VERSION 5.8 ;
BUSBITCHARS "[]" ;
DIVIDERCHAR "/" ;

UNITS
  DATABASE MICRONS 1000 ;
END UNITS
MANUFACTURINGGRID 0.001 ;

SITE FSFET
  CLASS CORE ;
  SIZE 0.050 BY 0.168 ;
  SYMMETRY X Y ;
END FSFET

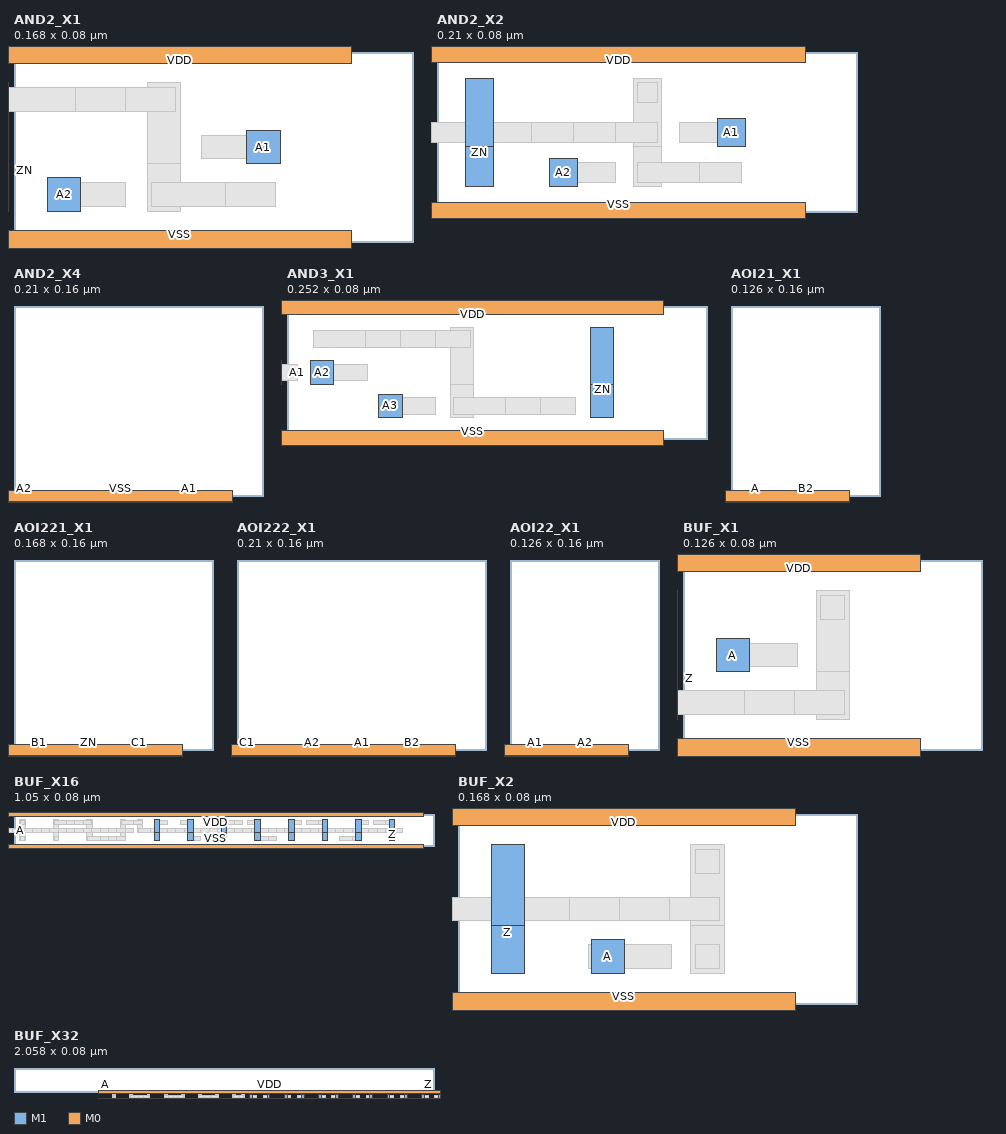
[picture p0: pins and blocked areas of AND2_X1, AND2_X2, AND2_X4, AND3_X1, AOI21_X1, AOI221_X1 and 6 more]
MACRO AND2_X1
  CLASS CORE ;
  FOREIGN AND2_X1 0 0 ;
  ORIGIN -0.0210 0.0000 ;
  SIZE 0.1680 BY 0.0800 ;
  SITE FSFET ;
  SYMMETRY X Y ;
  PIN A1
    DIRECTION INPUT ;
    USE SIGNAL ;
    PORT
      LAYER M1 ;
        RECT 0.1190 0.0330 0.1330 0.0470 ;
    END
  END A1
  PIN A2
    DIRECTION INPUT ;
    USE SIGNAL ;
    PORT
      LAYER M1 ;
        RECT 0.0350 0.0130 0.0490 0.0270 ;
    END
  END A2
  PIN ZN
    DIRECTION OUTPUT ;
    USE SIGNAL ;
    PORT
      LAYER M1 ;
        RECT -0.0070 0.0130 0.0070 0.0470 ;
        RECT -0.0070 0.0330 0.0070 0.0670 ;
    END
  END ZN
  PIN VSS
    DIRECTION INOUT ;
    USE GROUND ;
    PORT
      LAYER M0 ;
        RECT -0.0370 -0.0050 0.1630 0.0050 ;
    END
  END VSS
  PIN VDD
    DIRECTION INOUT ;
    USE POWER ;
    PORT
      LAYER M0 ;
        RECT -0.0370 0.0750 0.1630 0.0850 ;
    END
  END VDD
  OBS
    LAYER M1 ;
      RECT 0.0770 0.0130 0.0910 0.0470 ;
      RECT 0.0770 0.0330 0.0910 0.0670 ;
    LAYER M0 ;
      RECT 0.1000 0.0350 0.1310 0.0450 ;
      RECT 0.0370 0.0150 0.0680 0.0250 ;
      RECT -0.0050 0.0150 0.0050 0.0250 ;
      RECT -0.0050 0.0550 0.0050 0.0650 ;
      RECT 0.1000 0.0150 0.1310 0.0250 ;
      RECT 0.0790 0.0150 0.1100 0.0250 ;
      RECT 0.0580 0.0550 0.0890 0.0650 ;
      RECT 0.0370 0.0550 0.0680 0.0650 ;
      RECT 0.0160 0.0550 0.0470 0.0650 ;
  END
END AND2_X1

MACRO AND2_X2
  CLASS CORE ;
  FOREIGN AND2_X2 0 0 ;
  ORIGIN -0.0210 0.0000 ;
  SIZE 0.2100 BY 0.0800 ;
  SITE FSFET ;
  SYMMETRY X Y ;
  PIN A1
    DIRECTION INPUT ;
    USE SIGNAL ;
    PORT
      LAYER M1 ;
        RECT 0.1610 0.0330 0.1750 0.0470 ;
    END
  END A1
  PIN A2
    DIRECTION INPUT ;
    USE SIGNAL ;
    PORT
      LAYER M1 ;
        RECT 0.0770 0.0130 0.0910 0.0270 ;
    END
  END A2
  PIN ZN
    DIRECTION OUTPUT ;
    USE SIGNAL ;
    PORT
      LAYER M1 ;
        RECT 0.0350 0.0130 0.0490 0.0470 ;
        RECT 0.0350 0.0330 0.0490 0.0670 ;
    END
  END ZN
  PIN VDD
    DIRECTION INOUT ;
    USE POWER ;
    PORT
      LAYER M0 ;
        RECT -0.0370 0.0750 0.2050 0.0850 ;
    END
  END VDD
  PIN VSS
    DIRECTION INOUT ;
    USE GROUND ;
    PORT
      LAYER M0 ;
        RECT -0.0370 -0.0050 0.2050 0.0050 ;
    END
  END VSS
  OBS
    LAYER M1 ;
      RECT 0.1190 0.0130 0.1330 0.0470 ;
      RECT 0.1190 0.0330 0.1330 0.0670 ;
    LAYER M0 ;
      RECT 0.1420 0.0350 0.1730 0.0450 ;
      RECT 0.0790 0.0150 0.1100 0.0250 ;
      RECT 0.1210 0.0550 0.1310 0.0650 ;
      RECT 0.0370 0.0150 0.0470 0.0250 ;
      RECT 0.0370 0.0550 0.0470 0.0650 ;
      RECT 0.1420 0.0150 0.1730 0.0250 ;
      RECT 0.1210 0.0150 0.1520 0.0250 ;
      RECT 0.1000 0.0350 0.1310 0.0450 ;
      RECT 0.0790 0.0350 0.1100 0.0450 ;
      RECT 0.0580 0.0350 0.0890 0.0450 ;
      RECT 0.0370 0.0350 0.0680 0.0450 ;
      RECT 0.0160 0.0350 0.0470 0.0450 ;
  END
END AND2_X2

MACRO AND2_X4
  CLASS CORE ;
  FOREIGN AND2_X4 0 0 ;
  ORIGIN -0.0210 -0.0800 ;
  SIZE 0.2100 BY 0.1600 ;
  SITE FSFET ;
  SYMMETRY X Y ;
  PIN ZN
    DIRECTION OUTPUT ;
    USE SIGNAL ;
    PORT
      LAYER M1 ;
        RECT -0.0070 -0.0670 0.0070 -0.0330 ;
        RECT -0.0070 -0.0470 0.0070 -0.0130 ;
    END
  END ZN
  PIN A1
    DIRECTION INPUT ;
    USE SIGNAL ;
    PORT
      LAYER M1 ;
        RECT 0.1610 0.0130 0.1750 0.0270 ;
    END
  END A1
  PIN A2
    DIRECTION INPUT ;
    USE SIGNAL ;
    PORT
      LAYER M1 ;
        RECT -0.0070 0.0330 0.0070 0.0470 ;
    END
  END A2
  PIN VSS
    DIRECTION INOUT ;
    USE GROUND ;
    PORT
      LAYER M0 ;
        RECT -0.0370 -0.0050 0.2050 0.0050 ;
    END
  END VSS
  PIN VDD
    DIRECTION INOUT ;
    USE POWER ;
    PORT
      LAYER M0 ;
        RECT -0.0370 -0.0850 0.2050 -0.0750 ;
    END
  END VDD
  PIN VDD
    DIRECTION INOUT ;
    USE POWER ;
    PORT
      LAYER M0 ;
        RECT -0.0370 0.0750 0.2050 0.0850 ;
    END
  END VDD
  OBS
    LAYER M1 ;
      RECT 0.1190 -0.0470 0.1330 -0.0130 ;
      RECT 0.1190 -0.0270 0.1330 0.0070 ;
      RECT 0.1190 -0.0070 0.1330 0.0270 ;
      RECT 0.1190 0.0130 0.1330 0.0470 ;
      RECT 0.1190 0.0330 0.1330 0.0670 ;
      RECT 0.0770 -0.0470 0.0910 -0.0130 ;
      RECT 0.0770 -0.0270 0.0910 0.0070 ;
      RECT 0.0770 -0.0070 0.0910 0.0270 ;
      RECT 0.0350 -0.0470 0.0490 -0.0130 ;
      RECT 0.0350 -0.0270 0.0490 0.0070 ;
      RECT 0.0350 -0.0070 0.0490 0.0270 ;
      RECT 0.0350 0.0130 0.0490 0.0470 ;
      RECT 0.0350 0.0330 0.0490 0.0670 ;
    LAYER M0 ;
      RECT 0.1000 0.0150 0.1730 0.0250 ;
      RECT 0.0790 0.0150 0.0890 0.0250 ;
      RECT 0.1210 0.0550 0.1310 0.0650 ;
      RECT 0.0370 0.0550 0.0470 0.0650 ;
      RECT 0.0790 0.0550 0.1100 0.0650 ;
      RECT 0.0580 0.0550 0.0890 0.0650 ;
      RECT 0.1210 0.0350 0.1520 0.0450 ;
      RECT 0.1000 0.0350 0.1310 0.0450 ;
      RECT 0.0790 0.0350 0.1100 0.0450 ;
      RECT 0.0580 0.0350 0.0890 0.0450 ;
      RECT 0.0370 0.0350 0.0680 0.0450 ;
      RECT -0.0050 0.0350 0.0470 0.0450 ;
      RECT 0.1000 -0.0650 0.1310 -0.0550 ;
      RECT 0.0790 -0.0650 0.1100 -0.0550 ;
      RECT 0.0580 -0.0650 0.0890 -0.0550 ;
      RECT 0.0370 -0.0650 0.0680 -0.0550 ;
      RECT 0.0160 -0.0650 0.0470 -0.0550 ;
      RECT -0.0050 -0.0650 0.0260 -0.0550 ;
      RECT 0.1000 -0.0250 0.1310 -0.0150 ;
      RECT 0.0790 -0.0250 0.1100 -0.0150 ;
      RECT 0.0580 -0.0250 0.0890 -0.0150 ;
      RECT 0.0370 -0.0250 0.0680 -0.0150 ;
      RECT 0.0160 -0.0250 0.0470 -0.0150 ;
      RECT -0.0050 -0.0250 0.0260 -0.0150 ;
      RECT 0.1210 -0.0450 0.1520 -0.0350 ;
      RECT 0.1000 -0.0450 0.1310 -0.0350 ;
      RECT 0.0790 -0.0450 0.1100 -0.0350 ;
      RECT 0.0580 -0.0450 0.0890 -0.0350 ;
      RECT 0.0370 -0.0450 0.0680 -0.0350 ;
      RECT 0.0160 -0.0450 0.0470 -0.0350 ;
  END
END AND2_X4

MACRO AND3_X1
  CLASS CORE ;
  FOREIGN AND3_X1 0 0 ;
  ORIGIN -0.0210 0.0000 ;
  SIZE 0.2520 BY 0.0800 ;
  SITE FSFET ;
  SYMMETRY X Y ;
  PIN A3
    DIRECTION INPUT ;
    USE SIGNAL ;
    PORT
      LAYER M1 ;
        RECT 0.0760 0.0130 0.0900 0.0270 ;
    END
  END A3
  PIN A2
    DIRECTION INPUT ;
    USE SIGNAL ;
    PORT
      LAYER M1 ;
        RECT 0.0350 0.0330 0.0490 0.0470 ;
    END
  END A2
  PIN A1
    DIRECTION INPUT ;
    USE SIGNAL ;
    PORT
      LAYER M1 ;
        RECT -0.0070 0.0330 0.0070 0.0470 ;
    END
  END A1
  PIN ZN
    DIRECTION OUTPUT ;
    USE SIGNAL ;
    PORT
      LAYER M1 ;
        RECT 0.2030 0.0130 0.2170 0.0470 ;
        RECT 0.2030 0.0330 0.2170 0.0670 ;
    END
  END ZN
  PIN VSS
    DIRECTION INOUT ;
    USE GROUND ;
    PORT
      LAYER M0 ;
        RECT -0.0370 -0.0050 0.2470 0.0050 ;
    END
  END VSS
  PIN VDD
    DIRECTION INOUT ;
    USE POWER ;
    PORT
      LAYER M0 ;
        RECT -0.0370 0.0750 0.2470 0.0850 ;
    END
  END VDD
  OBS
    LAYER M1 ;
      RECT 0.1190 0.0130 0.1330 0.0470 ;
      RECT 0.1190 0.0330 0.1330 0.0670 ;
    LAYER M0 ;
      RECT 0.0780 0.0150 0.1100 0.0250 ;
      RECT 0.0370 0.0350 0.0690 0.0450 ;
      RECT -0.0050 0.0350 0.0270 0.0450 ;
      RECT 0.2050 0.0150 0.2150 0.0250 ;
      RECT 0.2050 0.0550 0.2150 0.0650 ;
      RECT 0.1630 0.0150 0.1940 0.0250 ;
      RECT 0.1420 0.0150 0.1730 0.0250 ;
      RECT 0.1210 0.0150 0.1520 0.0250 ;
      RECT 0.1000 0.0550 0.1310 0.0650 ;
      RECT 0.0790 0.0550 0.1100 0.0650 ;
      RECT 0.0580 0.0550 0.0890 0.0650 ;
      RECT 0.0370 0.0550 0.0680 0.0650 ;
  END
END AND3_X1

MACRO AOI21_X1
  CLASS CORE ;
  FOREIGN AOI21_X1 0 0 ;
  ORIGIN -0.0210 -0.0800 ;
  SIZE 0.1260 BY 0.1600 ;
  SITE FSFET ;
  SYMMETRY X Y ;
  PIN A
    DIRECTION INPUT ;
    USE SIGNAL ;
    PORT
      LAYER M1 ;
        RECT 0.0350 -0.0470 0.0490 -0.0330 ;
    END
  END A
  PIN ZN
    DIRECTION OUTPUT ;
    USE SIGNAL ;
    PORT
      LAYER M1 ;
        RECT 0.0770 0.0130 0.0910 0.0470 ;
    END
  END ZN
  PIN B2
    DIRECTION INPUT ;
    USE SIGNAL ;
    PORT
      LAYER M1 ;
        RECT 0.0770 0.0530 0.0910 0.0670 ;
    END
  END B2
  PIN B1
    DIRECTION INPUT ;
    USE SIGNAL ;
    PORT
      LAYER M1 ;
        RECT 0.0350 0.0530 0.0490 0.0670 ;
    END
  END B1
  PIN VDD
    DIRECTION INOUT ;
    USE POWER ;
    PORT
      LAYER M0 ;
        RECT -0.0370 -0.0050 0.1210 0.0050 ;
    END
  END VDD
  PIN VSS
    DIRECTION INOUT ;
    USE GROUND ;
    PORT
      LAYER M0 ;
        RECT -0.0370 -0.0850 0.1210 -0.0750 ;
    END
  END VSS
  PIN VSS
    DIRECTION INOUT ;
    USE GROUND ;
    PORT
      LAYER M0 ;
        RECT -0.0370 0.0750 0.1210 0.0850 ;
    END
  END VSS
  OBS
    LAYER M1 ;
      RECT -0.0070 -0.0670 0.0070 -0.0330 ;
      RECT -0.0070 -0.0470 0.0070 -0.0130 ;
      RECT -0.0070 -0.0270 0.0070 0.0070 ;
      RECT -0.0070 -0.0070 0.0070 0.0270 ;
      RECT -0.0070 0.0130 0.0070 0.0470 ;
      RECT -0.0070 0.0330 0.0070 0.0670 ;
      RECT 0.0350 -0.0270 0.0490 0.0070 ;
      RECT 0.0350 -0.0070 0.0490 0.0270 ;
    LAYER M0 ;
      RECT 0.0160 -0.0450 0.0470 -0.0350 ;
      RECT 0.0580 0.0550 0.0890 0.0650 ;
      RECT 0.0160 0.0550 0.0470 0.0650 ;
      RECT -0.0050 -0.0650 0.0050 -0.0550 ;
      RECT 0.0790 0.0150 0.0890 0.0250 ;
      RECT -0.0050 0.0150 0.0050 0.0250 ;
      RECT -0.0050 0.0550 0.0050 0.0650 ;
      RECT 0.0370 -0.0250 0.0470 -0.0150 ;
      RECT 0.0370 0.0150 0.0470 0.0250 ;
      RECT 0.0580 0.0350 0.0890 0.0450 ;
      RECT 0.0370 0.0350 0.0680 0.0450 ;
      RECT 0.0160 0.0350 0.0470 0.0450 ;
      RECT -0.0050 0.0350 0.0260 0.0450 ;
  END
END AOI21_X1

MACRO AOI221_X1
  CLASS CORE ;
  FOREIGN AOI221_X1 0 0 ;
  ORIGIN -0.0210 -0.0800 ;
  SIZE 0.1680 BY 0.1600 ;
  SITE FSFET ;
  SYMMETRY X Y ;
  PIN ZN
    DIRECTION OUTPUT ;
    USE SIGNAL ;
    PORT
      LAYER M1 ;
        RECT 0.0770 0.0330 0.0910 0.0670 ;
    END
  END ZN
  PIN C2
    DIRECTION INPUT ;
    USE SIGNAL ;
    PORT
      LAYER M1 ;
        RECT 0.0350 -0.0670 0.0490 -0.0530 ;
    END
  END C2
  PIN B2
    DIRECTION INPUT ;
    USE SIGNAL ;
    PORT
      LAYER M1 ;
        RECT -0.0070 0.0530 0.0070 0.0670 ;
    END
  END B2
  PIN B1
    DIRECTION INPUT ;
    USE SIGNAL ;
    PORT
      LAYER M1 ;
        RECT 0.0350 0.0530 0.0490 0.0670 ;
    END
  END B1
  PIN A
    DIRECTION INPUT ;
    USE SIGNAL ;
    PORT
      LAYER M1 ;
        RECT 0.1190 0.0530 0.1330 0.0670 ;
    END
  END A
  PIN C1
    DIRECTION INPUT ;
    USE SIGNAL ;
    PORT
      LAYER M1 ;
        RECT 0.1190 -0.0470 0.1330 -0.0330 ;
    END
  END C1
  PIN VDD
    DIRECTION INOUT ;
    USE POWER ;
    PORT
      LAYER M0 ;
        RECT -0.0370 -0.0050 0.1630 0.0050 ;
    END
  END VDD
  PIN VSS
    DIRECTION INOUT ;
    USE GROUND ;
    PORT
      LAYER M0 ;
        RECT -0.0370 -0.0850 0.1630 -0.0750 ;
    END
  END VSS
  PIN VSS
    DIRECTION INOUT ;
    USE GROUND ;
    PORT
      LAYER M0 ;
        RECT -0.0370 0.0750 0.1630 0.0850 ;
    END
  END VSS
  OBS
    LAYER M1 ;
      RECT 0.0770 -0.0670 0.0910 -0.0330 ;
      RECT 0.0770 -0.0470 0.0910 -0.0130 ;
      RECT 0.0770 -0.0270 0.0910 0.0070 ;
      RECT 0.0770 -0.0070 0.0910 0.0270 ;
      RECT 0.0770 0.0130 0.0910 0.0470 ;
      RECT 0.1190 0.0130 0.1330 0.0470 ;
      RECT 0.1190 -0.0270 0.1330 0.0070 ;
      RECT 0.1190 -0.0070 0.1330 0.0270 ;
      RECT 0.0350 -0.0270 0.0490 0.0470 ;
    LAYER M0 ;
      RECT 0.0370 -0.0650 0.0680 -0.0550 ;
      RECT -0.0050 0.0550 0.0260 0.0650 ;
      RECT 0.0370 0.0550 0.0680 0.0650 ;
      RECT 0.1000 0.0550 0.1310 0.0650 ;
      RECT 0.0790 -0.0250 0.0890 -0.0150 ;
      RECT 0.0790 0.0550 0.0890 0.0650 ;
      RECT 0.1210 -0.0250 0.1310 -0.0150 ;
      RECT 0.0370 -0.0250 0.0470 -0.0150 ;
      RECT 0.1210 0.0150 0.1310 0.0250 ;
      RECT 0.1000 -0.0650 0.1310 -0.0550 ;
      RECT 0.0790 -0.0650 0.1100 -0.0550 ;
      RECT 0.1000 0.0350 0.1310 0.0450 ;
      RECT 0.0790 0.0350 0.1100 0.0450 ;
      RECT 0.0580 0.0350 0.0890 0.0450 ;
      RECT 0.0370 0.0350 0.0680 0.0450 ;
      RECT 0.0580 0.0150 0.0890 0.0250 ;
      RECT 0.0370 0.0150 0.0680 0.0250 ;
      RECT 0.0160 0.0150 0.0470 0.0250 ;
      RECT -0.0050 0.0150 0.0260 0.0250 ;
      RECT 0.1000 -0.0450 0.1310 -0.0350 ;
  END
END AOI221_X1

MACRO AOI222_X1
  CLASS CORE ;
  FOREIGN AOI222_X1 0 0 ;
  ORIGIN -0.0210 -0.0800 ;
  SIZE 0.2100 BY 0.1600 ;
  SITE FSFET ;
  SYMMETRY X Y ;
  PIN A2
    DIRECTION INPUT ;
    USE SIGNAL ;
    PORT
      LAYER M1 ;
        RECT 0.0770 -0.0670 0.0910 -0.0530 ;
    END
  END A2
  PIN ZN
    DIRECTION OUTPUT ;
    USE SIGNAL ;
    PORT
      LAYER M1 ;
        RECT 0.0350 0.0330 0.0490 0.0670 ;
    END
  END ZN
  PIN A1
    DIRECTION INPUT ;
    USE SIGNAL ;
    PORT
      LAYER M1 ;
        RECT 0.1190 -0.0670 0.1330 -0.0530 ;
    END
  END A1
  PIN B2
    DIRECTION INPUT ;
    USE SIGNAL ;
    PORT
      LAYER M1 ;
        RECT 0.1610 0.0530 0.1750 0.0670 ;
    END
  END B2
  PIN B1
    DIRECTION INPUT ;
    USE SIGNAL ;
    PORT
      LAYER M1 ;
        RECT 0.1190 0.0530 0.1330 0.0670 ;
    END
  END B1
  PIN C1
    DIRECTION INPUT ;
    USE SIGNAL ;
    PORT
      LAYER M1 ;
        RECT -0.0070 0.0330 0.0070 0.0470 ;
    END
  END C1
  PIN C2
    DIRECTION INPUT ;
    USE SIGNAL ;
    PORT
      LAYER M1 ;
        RECT -0.0070 0.0530 0.0070 0.0670 ;
    END
  END C2
  PIN VDD
    DIRECTION INOUT ;
    USE POWER ;
    PORT
      LAYER M0 ;
        RECT -0.0370 -0.0050 0.2050 0.0050 ;
    END
  END VDD
  PIN VSS
    DIRECTION INOUT ;
    USE GROUND ;
    PORT
      LAYER M0 ;
        RECT -0.0370 0.0750 0.2050 0.0850 ;
    END
  END VSS
  PIN VSS
    DIRECTION INOUT ;
    USE GROUND ;
    PORT
      LAYER M0 ;
        RECT -0.0370 -0.0850 0.2050 -0.0750 ;
    END
  END VSS
  OBS
    LAYER M1 ;
      RECT 0.1610 -0.0670 0.1750 -0.0330 ;
      RECT 0.1610 -0.0470 0.1750 -0.0130 ;
      RECT 0.0770 -0.0470 0.0910 -0.0130 ;
      RECT 0.0350 -0.0270 0.0490 0.0070 ;
      RECT 0.0350 -0.0070 0.0490 0.0270 ;
      RECT 0.0350 0.0130 0.0490 0.0470 ;
      RECT 0.1190 -0.0270 0.1330 0.0070 ;
      RECT 0.1190 -0.0070 0.1330 0.0270 ;
      RECT 0.1610 0.0130 0.1750 0.0470 ;
      RECT 0.0770 0.0130 0.0910 0.0470 ;
    LAYER M0 ;
      RECT 0.0790 -0.0650 0.1100 -0.0550 ;
      RECT 0.1210 -0.0650 0.1520 -0.0550 ;
      RECT 0.1420 0.0550 0.1730 0.0650 ;
      RECT 0.1000 0.0550 0.1310 0.0650 ;
      RECT -0.0050 0.0350 0.0680 0.0450 ;
      RECT 0.1630 -0.0650 0.1730 -0.0550 ;
      RECT 0.1630 -0.0250 0.1730 -0.0150 ;
      RECT 0.1210 -0.0250 0.1310 -0.0150 ;
      RECT 0.1210 0.0150 0.1310 0.0250 ;
      RECT 0.1630 0.0150 0.1730 0.0250 ;
      RECT 0.1420 -0.0450 0.1730 -0.0350 ;
      RECT 0.1210 -0.0450 0.1520 -0.0350 ;
      RECT 0.1000 -0.0450 0.1310 -0.0350 ;
      RECT 0.0790 -0.0450 0.1100 -0.0350 ;
      RECT 0.0580 -0.0250 0.0890 -0.0150 ;
      RECT 0.0370 -0.0250 0.0680 -0.0150 ;
      RECT 0.0580 0.0550 0.0890 0.0650 ;
      RECT 0.0370 0.0550 0.0680 0.0650 ;
      RECT 0.0580 0.0150 0.0890 0.0250 ;
      RECT 0.0370 0.0150 0.0680 0.0250 ;
      RECT 0.0160 0.0150 0.0470 0.0250 ;
      RECT -0.0050 0.0150 0.0260 0.0250 ;
      RECT 0.1420 0.0350 0.1730 0.0450 ;
      RECT 0.1210 0.0350 0.1520 0.0450 ;
      RECT 0.1000 0.0350 0.1310 0.0450 ;
      RECT 0.0790 0.0350 0.1100 0.0450 ;
      RECT -0.0050 0.0550 0.0260 0.0650 ;
  END
END AOI222_X1

MACRO AOI22_X1
  CLASS CORE ;
  FOREIGN AOI22_X1 0 0 ;
  ORIGIN -0.0210 -0.0800 ;
  SIZE 0.1260 BY 0.1600 ;
  SITE FSFET ;
  SYMMETRY X Y ;
  PIN A2
    DIRECTION INPUT ;
    USE SIGNAL ;
    PORT
      LAYER M1 ;
        RECT 0.0770 -0.0670 0.0910 -0.0530 ;
    END
  END A2
  PIN A1
    DIRECTION INPUT ;
    USE SIGNAL ;
    PORT
      LAYER M1 ;
        RECT 0.0350 -0.0670 0.0490 -0.0530 ;
    END
  END A1
  PIN ZN
    DIRECTION OUTPUT ;
    USE SIGNAL ;
    PORT
      LAYER M1 ;
        RECT 0.0770 0.0330 0.0910 0.0670 ;
    END
  END ZN
  PIN B1
    DIRECTION INPUT ;
    USE SIGNAL ;
    PORT
      LAYER M1 ;
        RECT 0.0350 0.0530 0.0490 0.0670 ;
    END
  END B1
  PIN B2
    DIRECTION INPUT ;
    USE SIGNAL ;
    PORT
      LAYER M1 ;
        RECT -0.0070 0.0530 0.0070 0.0670 ;
    END
  END B2
  PIN VDD
    DIRECTION INOUT ;
    USE POWER ;
    PORT
      LAYER M0 ;
        RECT -0.0370 -0.0050 0.1210 0.0050 ;
    END
  END VDD
  PIN VSS
    DIRECTION INOUT ;
    USE GROUND ;
    PORT
      LAYER M0 ;
        RECT -0.0370 -0.0850 0.1210 -0.0750 ;
    END
  END VSS
  PIN VSS
    DIRECTION INOUT ;
    USE GROUND ;
    PORT
      LAYER M0 ;
        RECT -0.0370 0.0750 0.1210 0.0850 ;
    END
  END VSS
  OBS
    LAYER M1 ;
      RECT 0.0770 -0.0470 0.0910 -0.0130 ;
      RECT 0.0770 -0.0270 0.0910 0.0070 ;
      RECT 0.0770 -0.0070 0.0910 0.0270 ;
      RECT 0.0770 0.0130 0.0910 0.0470 ;
      RECT -0.0070 -0.0670 0.0070 -0.0330 ;
      RECT -0.0070 -0.0470 0.0070 -0.0130 ;
      RECT 0.0350 -0.0270 0.0490 0.0070 ;
      RECT 0.0350 -0.0070 0.0490 0.0270 ;
    LAYER M0 ;
      RECT 0.0580 -0.0650 0.0890 -0.0550 ;
      RECT 0.0160 -0.0650 0.0470 -0.0550 ;
      RECT 0.0370 0.0550 0.0680 0.0650 ;
      RECT -0.0050 0.0550 0.0260 0.0650 ;
      RECT -0.0050 -0.0650 0.0050 -0.0550 ;
      RECT 0.0790 -0.0250 0.0890 -0.0150 ;
      RECT -0.0050 -0.0250 0.0050 -0.0150 ;
      RECT 0.0790 0.0550 0.0890 0.0650 ;
      RECT 0.0370 -0.0250 0.0470 -0.0150 ;
      RECT 0.0370 0.0150 0.0470 0.0250 ;
      RECT 0.0580 -0.0450 0.0890 -0.0350 ;
      RECT 0.0370 -0.0450 0.0680 -0.0350 ;
      RECT 0.0160 -0.0450 0.0470 -0.0350 ;
      RECT -0.0050 -0.0450 0.0260 -0.0350 ;
  END
END AOI22_X1

MACRO BUF_X1
  CLASS CORE ;
  FOREIGN BUF_X1 0 0 ;
  ORIGIN -0.0210 0.0000 ;
  SIZE 0.1260 BY 0.0800 ;
  SITE FSFET ;
  SYMMETRY X Y ;
  PIN A
    DIRECTION INPUT ;
    USE SIGNAL ;
    PORT
      LAYER M1 ;
        RECT 0.0350 0.0330 0.0490 0.0470 ;
    END
  END A
  PIN Z
    DIRECTION OUTPUT ;
    USE SIGNAL ;
    PORT
      LAYER M1 ;
        RECT -0.0070 0.0130 0.0070 0.0470 ;
        RECT -0.0070 0.0330 0.0070 0.0670 ;
    END
  END Z
  PIN VSS
    DIRECTION INOUT ;
    USE GROUND ;
    PORT
      LAYER M0 ;
        RECT -0.0370 -0.0050 0.1210 0.0050 ;
    END
  END VSS
  PIN VDD
    DIRECTION INOUT ;
    USE POWER ;
    PORT
      LAYER M0 ;
        RECT -0.0370 0.0750 0.1210 0.0850 ;
    END
  END VDD
  OBS
    LAYER M1 ;
      RECT 0.0770 0.0130 0.0910 0.0470 ;
      RECT 0.0770 0.0330 0.0910 0.0670 ;
    LAYER M0 ;
      RECT 0.0370 0.0350 0.0690 0.0450 ;
      RECT 0.0790 0.0550 0.0890 0.0650 ;
      RECT -0.0050 0.0150 0.0050 0.0250 ;
      RECT -0.0050 0.0550 0.0050 0.0650 ;
      RECT 0.0580 0.0150 0.0890 0.0250 ;
      RECT 0.0370 0.0150 0.0680 0.0250 ;
      RECT 0.0160 0.0150 0.0470 0.0250 ;
  END
END BUF_X1

MACRO BUF_X16
  CLASS CORE ;
  FOREIGN BUF_X16 0 0 ;
  ORIGIN -0.0210 0.0000 ;
  SIZE 1.0500 BY 0.0800 ;
  SITE FSFET ;
  SYMMETRY X Y ;
  PIN Z
    DIRECTION OUTPUT ;
    USE SIGNAL ;
    PORT
      LAYER M1 ;
        RECT 0.9590 0.0130 0.9730 0.0470 ;
        RECT 0.9590 0.0330 0.9730 0.0670 ;
        RECT 0.8750 0.0130 0.8890 0.0470 ;
        RECT 0.8750 0.0330 0.8890 0.0670 ;
        RECT 0.7910 0.0130 0.8050 0.0470 ;
        RECT 0.7910 0.0330 0.8050 0.0670 ;
        RECT 0.7070 0.0130 0.7210 0.0470 ;
        RECT 0.7070 0.0330 0.7210 0.0670 ;
        RECT 0.6230 0.0130 0.6370 0.0470 ;
        RECT 0.6230 0.0330 0.6370 0.0670 ;
        RECT 0.5390 0.0130 0.5530 0.0470 ;
        RECT 0.5390 0.0330 0.5530 0.0670 ;
        RECT 0.4550 0.0130 0.4690 0.0470 ;
        RECT 0.4550 0.0330 0.4690 0.0670 ;
        RECT 0.3710 0.0130 0.3850 0.0470 ;
        RECT 0.3710 0.0330 0.3850 0.0670 ;
    END
  END Z
  PIN A
    DIRECTION INPUT ;
    USE SIGNAL ;
    PORT
      LAYER M1 ;
        RECT -0.0060 0.0330 0.0080 0.0470 ;
    END
  END A
  PIN VSS
    DIRECTION INOUT ;
    USE GROUND ;
    PORT
      LAYER M0 ;
        RECT -0.0370 -0.0050 1.0450 0.0050 ;
    END
  END VSS
  PIN VDD
    DIRECTION INOUT ;
    USE POWER ;
    PORT
      LAYER M0 ;
        RECT -0.0370 0.0750 1.0450 0.0850 ;
    END
  END VDD
  OBS
    LAYER M1 ;
      RECT 0.3290 0.0330 0.3430 0.0670 ;
      RECT 0.2870 0.0130 0.3010 0.0470 ;
      RECT 0.2870 0.0330 0.3010 0.0670 ;
      RECT 0.2030 0.0130 0.2170 0.0470 ;
      RECT 0.2030 0.0330 0.2170 0.0670 ;
      RECT 0.1190 0.0130 0.1330 0.0470 ;
      RECT 0.1190 0.0330 0.1330 0.0670 ;
      RECT 0.0350 0.0130 0.0490 0.0470 ;
      RECT 0.0350 0.0330 0.0490 0.0670 ;
    LAYER M0 ;
      RECT -0.0080 0.0350 0.0280 0.0450 ;
      RECT 0.9610 0.0150 0.9710 0.0250 ;
      RECT 0.3730 0.0150 0.3830 0.0250 ;
      RECT 0.1210 0.0150 0.1310 0.0250 ;
      RECT 0.0370 0.0150 0.0470 0.0250 ;
      RECT 0.0370 0.0550 0.0470 0.0650 ;
      RECT 0.2890 0.0350 0.3200 0.0450 ;
      RECT 0.2680 0.0350 0.2990 0.0450 ;
      RECT 0.2470 0.0350 0.2780 0.0450 ;
      RECT 0.2260 0.0350 0.2570 0.0450 ;
      RECT 0.2050 0.0350 0.2360 0.0450 ;
      RECT 0.1840 0.0350 0.2150 0.0450 ;
      RECT 0.1630 0.0350 0.1940 0.0450 ;
      RECT 0.1420 0.0350 0.1730 0.0450 ;
      RECT 0.1210 0.0350 0.1520 0.0450 ;
      RECT 0.1000 0.0350 0.1310 0.0450 ;
      RECT 0.0790 0.0350 0.1100 0.0450 ;
      RECT 0.0580 0.0350 0.0890 0.0450 ;
      RECT 0.0370 0.0350 0.0680 0.0450 ;
      RECT 0.0160 0.0350 0.0470 0.0450 ;
      RECT 0.8560 0.0150 0.8870 0.0250 ;
      RECT 0.8350 0.0150 0.8660 0.0250 ;
      RECT 0.6460 0.0150 0.6770 0.0250 ;
      RECT 0.6250 0.0150 0.6560 0.0250 ;
      RECT 0.5200 0.0150 0.5510 0.0250 ;
      RECT 0.4990 0.0150 0.5300 0.0250 ;
      RECT 0.4570 0.0150 0.4880 0.0250 ;
      RECT 0.9400 0.0550 0.9710 0.0650 ;
      RECT 0.9190 0.0550 0.9500 0.0650 ;
      RECT 0.8770 0.0550 0.9080 0.0650 ;
      RECT 0.7720 0.0550 0.8030 0.0650 ;
      RECT 0.7510 0.0550 0.7820 0.0650 ;
      RECT 0.7090 0.0550 0.7400 0.0650 ;
      RECT 0.6040 0.0550 0.6350 0.0650 ;
      RECT 0.5620 0.0550 0.5930 0.0650 ;
      RECT 0.5410 0.0550 0.5720 0.0650 ;
      RECT 0.4360 0.0550 0.4670 0.0650 ;
      RECT 0.3730 0.0550 0.4040 0.0650 ;
      RECT 0.2680 0.0150 0.2990 0.0250 ;
      RECT 0.2470 0.0150 0.2780 0.0250 ;
      RECT 0.2260 0.0150 0.2570 0.0250 ;
      RECT 0.2050 0.0150 0.2360 0.0250 ;
      RECT 0.9610 0.0350 0.9920 0.0450 ;
      RECT 0.9400 0.0350 0.9710 0.0450 ;
      RECT 0.9190 0.0350 0.9500 0.0450 ;
      RECT 0.8980 0.0350 0.9290 0.0450 ;
      RECT 0.8770 0.0350 0.9080 0.0450 ;
      RECT 0.8560 0.0350 0.8870 0.0450 ;
      RECT 0.8350 0.0350 0.8660 0.0450 ;
      RECT 0.8140 0.0350 0.8450 0.0450 ;
      RECT 0.7930 0.0350 0.8240 0.0450 ;
      RECT 0.7720 0.0350 0.8030 0.0450 ;
      RECT 0.7510 0.0350 0.7820 0.0450 ;
      RECT 0.7300 0.0350 0.7610 0.0450 ;
      RECT 0.7090 0.0350 0.7400 0.0450 ;
      RECT 0.6880 0.0350 0.7190 0.0450 ;
      RECT 0.6670 0.0350 0.6980 0.0450 ;
      RECT 0.6460 0.0350 0.6770 0.0450 ;
      RECT 0.6250 0.0350 0.6560 0.0450 ;
      RECT 0.6040 0.0350 0.6350 0.0450 ;
      RECT 0.5830 0.0350 0.6140 0.0450 ;
      RECT 0.5620 0.0350 0.5930 0.0450 ;
      RECT 0.5410 0.0350 0.5720 0.0450 ;
      RECT 0.5200 0.0350 0.5510 0.0450 ;
      RECT 0.4990 0.0350 0.5300 0.0450 ;
      RECT 0.4780 0.0350 0.5090 0.0450 ;
      RECT 0.4570 0.0350 0.4880 0.0450 ;
      RECT 0.4360 0.0350 0.4670 0.0450 ;
      RECT 0.4150 0.0350 0.4460 0.0450 ;
      RECT 0.3940 0.0350 0.4250 0.0450 ;
      RECT 0.3730 0.0350 0.4040 0.0450 ;
      RECT 0.3520 0.0350 0.3830 0.0450 ;
      RECT 0.3310 0.0350 0.3620 0.0450 ;
      RECT 0.3100 0.0550 0.3410 0.0650 ;
      RECT 0.2890 0.0550 0.3200 0.0650 ;
      RECT 0.1840 0.0550 0.2150 0.0650 ;
      RECT 0.1630 0.0550 0.1940 0.0650 ;
      RECT 0.1420 0.0550 0.1730 0.0650 ;
      RECT 0.1210 0.0550 0.1520 0.0650 ;
  END
END BUF_X16

MACRO BUF_X2
  CLASS CORE ;
  FOREIGN BUF_X2 0 0 ;
  ORIGIN -0.0210 0.0000 ;
  SIZE 0.1680 BY 0.0800 ;
  SITE FSFET ;
  SYMMETRY X Y ;
  PIN A
    DIRECTION INPUT ;
    USE SIGNAL ;
    PORT
      LAYER M1 ;
        RECT 0.0770 0.0130 0.0910 0.0270 ;
    END
  END A
  PIN Z
    DIRECTION OUTPUT ;
    USE SIGNAL ;
    PORT
      LAYER M1 ;
        RECT 0.0350 0.0130 0.0490 0.0470 ;
        RECT 0.0350 0.0330 0.0490 0.0670 ;
    END
  END Z
  PIN VSS
    DIRECTION INOUT ;
    USE GROUND ;
    PORT
      LAYER M0 ;
        RECT -0.0370 -0.0050 0.1630 0.0050 ;
    END
  END VSS
  PIN VDD
    DIRECTION INOUT ;
    USE POWER ;
    PORT
      LAYER M0 ;
        RECT -0.0370 0.0750 0.1630 0.0850 ;
    END
  END VDD
  OBS
    LAYER M1 ;
      RECT 0.1190 0.0130 0.1330 0.0470 ;
      RECT 0.1190 0.0330 0.1330 0.0670 ;
    LAYER M0 ;
      RECT 0.0760 0.0150 0.1110 0.0250 ;
      RECT 0.1210 0.0150 0.1310 0.0250 ;
      RECT 0.1210 0.0550 0.1310 0.0650 ;
      RECT 0.0370 0.0150 0.0470 0.0250 ;
      RECT 0.0370 0.0550 0.0470 0.0650 ;
      RECT 0.1000 0.0350 0.1310 0.0450 ;
      RECT 0.0790 0.0350 0.1100 0.0450 ;
      RECT 0.0580 0.0350 0.0890 0.0450 ;
      RECT 0.0370 0.0350 0.0680 0.0450 ;
      RECT 0.0160 0.0350 0.0470 0.0450 ;
  END
END BUF_X2

MACRO BUF_X32
  CLASS CORE ;
  FOREIGN BUF_X32 0 0 ;
  ORIGIN 0.2140 -0.0400 ;
  SIZE 2.0580 BY 0.0800 ;
  SITE FSFET ;
  SYMMETRY X Y ;
  PIN Z
    DIRECTION OUTPUT ;
    USE SIGNAL ;
    PORT
      LAYER M1 ;
        RECT 1.2780 -0.0270 1.2920 0.0070 ;
        RECT 1.2780 -0.0070 1.2920 0.0270 ;
        RECT 1.3620 -0.0070 1.3760 0.0270 ;
        RECT 1.3620 -0.0270 1.3760 0.0070 ;
        RECT 1.4460 -0.0070 1.4600 0.0270 ;
        RECT 1.4460 -0.0270 1.4600 0.0070 ;
        RECT 1.5300 -0.0070 1.5440 0.0270 ;
        RECT 1.5300 -0.0270 1.5440 0.0070 ;
        RECT 1.6140 -0.0070 1.6280 0.0270 ;
        RECT 1.6140 -0.0270 1.6280 0.0070 ;
        RECT 1.6980 -0.0070 1.7120 0.0270 ;
        RECT 1.6980 -0.0270 1.7120 0.0070 ;
        RECT 1.7820 -0.0070 1.7960 0.0270 ;
        RECT 1.7820 -0.0270 1.7960 0.0070 ;
        RECT 1.8660 -0.0070 1.8800 0.0270 ;
        RECT 1.8660 -0.0270 1.8800 0.0070 ;
        RECT 1.9500 -0.0070 1.9640 0.0270 ;
        RECT 1.9500 -0.0270 1.9640 0.0070 ;
        RECT 2.0340 -0.0070 2.0480 0.0270 ;
        RECT 2.0340 -0.0270 2.0480 0.0070 ;
        RECT 2.1180 -0.0070 2.1320 0.0270 ;
        RECT 2.1180 -0.0270 2.1320 0.0070 ;
        RECT 2.2020 -0.0070 2.2160 0.0270 ;
        RECT 2.2020 -0.0270 2.2160 0.0070 ;
        RECT 1.1940 -0.0270 1.2080 0.0070 ;
        RECT 1.1940 -0.0070 1.2080 0.0270 ;
        RECT 1.1100 -0.0270 1.1240 0.0070 ;
        RECT 1.1100 -0.0070 1.1240 0.0270 ;
        RECT 1.0260 -0.0270 1.0400 0.0070 ;
        RECT 1.0260 -0.0070 1.0400 0.0270 ;
        RECT 0.9420 -0.0270 0.9560 0.0070 ;
        RECT 0.9420 -0.0070 0.9560 0.0270 ;
    END
  END Z
  PIN A
    DIRECTION INPUT ;
    USE SIGNAL ;
    PORT
      LAYER M1 ;
        RECT 0.2290 -0.0070 0.2430 0.0070 ;
    END
  END A
  PIN VSS
    DIRECTION INOUT ;
    USE GROUND ;
    PORT
      LAYER M0 ;
        RECT 0.1980 -0.0450 2.2880 -0.0350 ;
    END
  END VSS
  PIN VDD
    DIRECTION INOUT ;
    USE POWER ;
    PORT
      LAYER M0 ;
        RECT 0.1980 0.0350 2.2880 0.0450 ;
    END
  END VDD
  OBS
    LAYER M1 ;
      RECT 0.9000 -0.0070 0.9140 0.0270 ;
      RECT 0.8580 -0.0070 0.8720 0.0270 ;
      RECT 0.3540 -0.0270 0.3680 0.0070 ;
      RECT 0.3540 -0.0070 0.3680 0.0270 ;
      RECT 0.2700 -0.0270 0.2840 0.0070 ;
      RECT 0.2700 -0.0070 0.2840 0.0270 ;
      RECT 0.8580 -0.0270 0.8720 0.0070 ;
      RECT 0.4380 -0.0070 0.4520 0.0270 ;
      RECT 0.4380 -0.0270 0.4520 0.0070 ;
      RECT 0.5220 -0.0070 0.5360 0.0270 ;
      RECT 0.5220 -0.0270 0.5360 0.0070 ;
      RECT 0.6060 -0.0070 0.6200 0.0270 ;
      RECT 0.6060 -0.0270 0.6200 0.0070 ;
      RECT 0.6900 -0.0070 0.7040 0.0270 ;
      RECT 0.6900 -0.0270 0.7040 0.0070 ;
      RECT 0.7740 -0.0070 0.7880 0.0270 ;
      RECT 0.7740 -0.0270 0.7880 0.0070 ;
    LAYER M0 ;
      RECT 0.6920 0.0150 0.7230 0.0250 ;
      RECT 1.3430 0.0150 1.3740 0.0250 ;
      RECT 1.5320 -0.0250 1.5630 -0.0150 ;
      RECT 1.2800 0.0150 1.3110 0.0250 ;
      RECT 0.8810 0.0150 0.9120 0.0250 ;
      RECT 0.9440 -0.0250 0.9540 -0.0150 ;
      RECT 0.2920 -0.0250 0.3230 -0.0150 ;
      RECT 0.2710 -0.0250 0.3020 -0.0150 ;
      RECT 1.7000 -0.0050 1.7310 0.0050 ;
      RECT 1.6790 -0.0050 1.7100 0.0050 ;
      RECT 1.9940 -0.0050 2.0250 0.0050 ;
      RECT 1.9730 -0.0050 2.0040 0.0050 ;
      RECT 1.9520 -0.0050 1.9830 0.0050 ;
      RECT 1.9310 -0.0050 1.9620 0.0050 ;
      RECT 1.9100 -0.0050 1.9410 0.0050 ;
      RECT 1.7840 0.0150 1.8150 0.0250 ;
      RECT 1.7840 -0.0050 1.8150 0.0050 ;
      RECT 2.1830 0.0150 2.2140 0.0250 ;
      RECT 1.8890 -0.0050 1.9200 0.0050 ;
      RECT 1.8680 -0.0050 1.8990 0.0050 ;
      RECT 1.8470 -0.0050 1.8780 0.0050 ;
      RECT 1.3640 -0.0250 1.3950 -0.0150 ;
      RECT 1.3640 0.0150 1.3740 0.0250 ;
      RECT 1.7000 -0.0250 1.7100 -0.0150 ;
      RECT 1.4480 -0.0250 1.4580 -0.0150 ;
      RECT 1.3640 -0.0250 1.3740 -0.0150 ;
      RECT 1.6580 -0.0050 1.6890 0.0050 ;
      RECT 1.5530 -0.0050 1.5840 0.0050 ;
      RECT 1.5740 -0.0050 1.6050 0.0050 ;
      RECT 1.5950 -0.0050 1.6260 0.0050 ;
      RECT 1.6160 -0.0050 1.6470 0.0050 ;
      RECT 1.7630 -0.0250 1.7940 -0.0150 ;
      RECT 1.7000 -0.0250 1.7310 -0.0150 ;
      RECT 1.4270 -0.0050 1.4580 0.0050 ;
      RECT 1.4060 -0.0050 1.4370 0.0050 ;
      RECT 1.3850 -0.0050 1.4160 0.0050 ;
      RECT 1.3640 -0.0050 1.3950 0.0050 ;
      RECT 1.3430 -0.0050 1.3740 0.0050 ;
      RECT 1.5950 -0.0250 1.6260 -0.0150 ;
      RECT 1.5320 -0.0250 1.5630 -0.0150 ;
      RECT 1.7630 -0.0050 1.7940 0.0050 ;
      RECT 1.7420 -0.0050 1.7730 0.0050 ;
      RECT 1.7210 -0.0050 1.7520 0.0050 ;
      RECT 1.4270 -0.0250 1.4580 -0.0150 ;
      RECT 2.0150 -0.0050 2.0460 0.0050 ;
      RECT 2.0360 -0.0050 2.0670 0.0050 ;
      RECT 2.0570 -0.0050 2.0880 0.0050 ;
      RECT 2.0780 -0.0050 2.1090 0.0050 ;
      RECT 2.0990 -0.0050 2.1300 0.0050 ;
      RECT 2.1200 -0.0050 2.1510 0.0050 ;
      RECT 2.1410 -0.0050 2.1720 0.0050 ;
      RECT 2.1620 -0.0050 2.1930 0.0050 ;
      RECT 2.1830 -0.0050 2.2140 0.0050 ;
      RECT 2.2040 -0.0050 2.2350 0.0050 ;
      RECT 2.2250 -0.0050 2.2560 0.0050 ;
      RECT 0.3340 -0.0250 0.3650 -0.0150 ;
      RECT 1.8680 -0.0250 1.8990 -0.0150 ;
      RECT 1.9310 -0.0250 1.9620 -0.0150 ;
      RECT 2.0360 -0.0250 2.0670 -0.0150 ;
      RECT 2.0990 -0.0250 2.1300 -0.0150 ;
      RECT 0.5240 0.0150 0.5550 0.0250 ;
      RECT 0.8600 0.0150 0.8910 0.0250 ;
      RECT 0.5450 0.0150 0.5760 0.0250 ;
      RECT 0.5660 0.0150 0.5970 0.0250 ;
      RECT 1.8260 -0.0050 1.8570 0.0050 ;
      RECT 1.8050 -0.0050 1.8360 0.0050 ;
      RECT 1.8470 0.0150 1.8780 0.0250 ;
      RECT 1.9520 0.0150 1.9830 0.0250 ;
      RECT 2.0150 0.0150 2.0460 0.0250 ;
      RECT 2.1200 0.0150 2.1510 0.0250 ;
      RECT 1.5320 -0.0050 1.5630 0.0050 ;
      RECT 1.5110 -0.0050 1.5420 0.0050 ;
      RECT 1.4900 -0.0050 1.5210 0.0050 ;
      RECT 1.4690 -0.0050 1.5000 0.0050 ;
      RECT 1.4480 -0.0050 1.4790 0.0050 ;
      RECT 1.4480 0.0150 1.4790 0.0250 ;
      RECT 1.5110 0.0150 1.5420 0.0250 ;
      RECT 0.7340 0.0150 0.7650 0.0250 ;
      RECT 1.6370 -0.0050 1.6680 0.0050 ;
      RECT 1.3190 -0.0050 1.3550 0.0050 ;
      RECT 0.7550 0.0150 0.7860 0.0250 ;
      RECT 0.7130 0.0150 0.7440 0.0250 ;
      RECT 0.3130 -0.0250 0.3440 -0.0150 ;
      RECT 2.2040 -0.0250 2.2140 -0.0150 ;
      RECT 1.6790 0.0150 1.7100 0.0250 ;
      RECT 1.1960 -0.0250 1.2270 -0.0150 ;
      RECT 0.5450 -0.0050 0.5760 0.0050 ;
      RECT 1.3010 -0.0050 1.3320 0.0050 ;
      RECT 1.2800 -0.0250 1.2900 -0.0150 ;
      RECT 0.2270 -0.0050 0.2630 0.0050 ;
      RECT 0.5660 -0.0050 0.5970 0.0050 ;
      RECT 0.5870 -0.0050 0.6180 0.0050 ;
      RECT 0.6080 -0.0050 0.6390 0.0050 ;
      RECT 0.6290 -0.0050 0.6600 0.0050 ;
      RECT 0.6500 -0.0050 0.6810 0.0050 ;
      RECT 0.6710 -0.0050 0.7020 0.0050 ;
      RECT 0.6920 -0.0050 0.7230 0.0050 ;
      RECT 0.4400 -0.0250 0.4710 -0.0150 ;
      RECT 1.1120 0.0150 1.1430 0.0250 ;
      RECT 0.7760 -0.0250 0.8070 -0.0150 ;
      RECT 0.7970 -0.0250 0.8280 -0.0150 ;
      RECT 0.8180 -0.0250 0.8490 -0.0150 ;
      RECT 0.8390 -0.0250 0.8700 -0.0150 ;
      RECT 0.9020 -0.0050 0.9330 0.0050 ;
      RECT 0.5870 0.0150 0.6180 0.0250 ;
      RECT 0.6710 -0.0250 0.7020 -0.0150 ;
      RECT 0.6500 -0.0250 0.6810 -0.0150 ;
      RECT 0.6290 -0.0250 0.6600 -0.0150 ;
      RECT 0.6080 -0.0250 0.6390 -0.0150 ;
      RECT 1.1540 -0.0050 1.1850 0.0050 ;
      RECT 1.1330 -0.0050 1.1640 0.0050 ;
      RECT 1.1120 -0.0050 1.1430 0.0050 ;
      RECT 1.0910 -0.0050 1.1220 0.0050 ;
      RECT 1.0700 -0.0050 1.1010 0.0050 ;
      RECT 1.0490 -0.0050 1.0800 0.0050 ;
      RECT 1.0280 -0.0050 1.0590 0.0050 ;
      RECT 1.0070 -0.0050 1.0380 0.0050 ;
      RECT 0.9860 -0.0050 1.0170 0.0050 ;
      RECT 0.9650 -0.0050 0.9960 0.0050 ;
      RECT 0.9440 -0.0050 0.9750 0.0050 ;
      RECT 0.9230 -0.0050 0.9540 0.0050 ;
      RECT 1.2170 -0.0050 1.2480 0.0050 ;
      RECT 1.2380 -0.0050 1.2690 0.0050 ;
      RECT 0.8600 -0.0050 0.8910 0.0050 ;
      RECT 0.8390 -0.0050 0.8700 0.0050 ;
      RECT 0.8180 -0.0050 0.8490 0.0050 ;
      RECT 0.3350 -0.0050 0.3660 0.0050 ;
      RECT 0.3140 -0.0050 0.3450 0.0050 ;
      RECT 0.2930 -0.0050 0.3240 0.0050 ;
      RECT 0.2720 -0.0050 0.3030 0.0050 ;
      RECT 0.2510 -0.0050 0.2820 0.0050 ;
      RECT 0.9440 0.0150 0.9750 0.0250 ;
      RECT 0.5030 -0.0250 0.5340 -0.0150 ;
      RECT 0.4820 -0.0250 0.5130 -0.0150 ;
      RECT 0.4610 -0.0250 0.4920 -0.0150 ;
      RECT 1.2590 -0.0250 1.2900 -0.0150 ;
      RECT 1.0280 -0.0250 1.0590 -0.0150 ;
      RECT 1.0070 0.0150 1.0380 0.0250 ;
      RECT 0.3560 -0.0050 0.3870 0.0050 ;
      RECT 0.3770 -0.0050 0.4080 0.0050 ;
      RECT 0.3980 -0.0050 0.4290 0.0050 ;
      RECT 0.4190 -0.0050 0.4500 0.0050 ;
      RECT 0.4400 -0.0050 0.4710 0.0050 ;
      RECT 0.4610 -0.0050 0.4920 0.0050 ;
      RECT 0.7760 -0.0050 0.8070 0.0050 ;
      RECT 0.7550 -0.0050 0.7860 0.0050 ;
      RECT 0.3560 0.0150 0.3870 0.0250 ;
      RECT 0.3770 0.0150 0.4080 0.0250 ;
      RECT 0.3980 0.0150 0.4290 0.0250 ;
      RECT 0.4190 0.0150 0.4500 0.0250 ;
      RECT 1.2590 -0.0050 1.2900 0.0050 ;
      RECT 1.2800 -0.0050 1.3110 0.0050 ;
      RECT 1.1750 -0.0050 1.2060 0.0050 ;
      RECT 1.1960 -0.0050 1.2270 0.0050 ;
      RECT 0.7970 -0.0050 0.8280 0.0050 ;
      RECT 1.1960 -0.0250 1.2060 -0.0150 ;
      RECT 1.0910 -0.0250 1.1220 -0.0150 ;
      RECT 1.1750 0.0150 1.2060 0.0250 ;
      RECT 0.2720 0.0150 0.2820 0.0250 ;
      RECT 0.7340 -0.0050 0.7650 0.0050 ;
      RECT 0.7130 -0.0050 0.7440 0.0050 ;
      RECT 0.6080 -0.0250 0.6180 -0.0150 ;
      RECT 0.3560 -0.0250 0.3660 -0.0150 ;
      RECT 0.2720 -0.0250 0.2820 -0.0150 ;
      RECT 0.5240 -0.0050 0.5550 0.0050 ;
      RECT 0.5030 -0.0050 0.5340 0.0050 ;
      RECT 0.4820 -0.0050 0.5130 0.0050 ;
      RECT 1.5950 -0.0250 1.6260 -0.0150 ;
      RECT 1.6160 0.0150 1.6470 0.0250 ;
  END
END BUF_X32

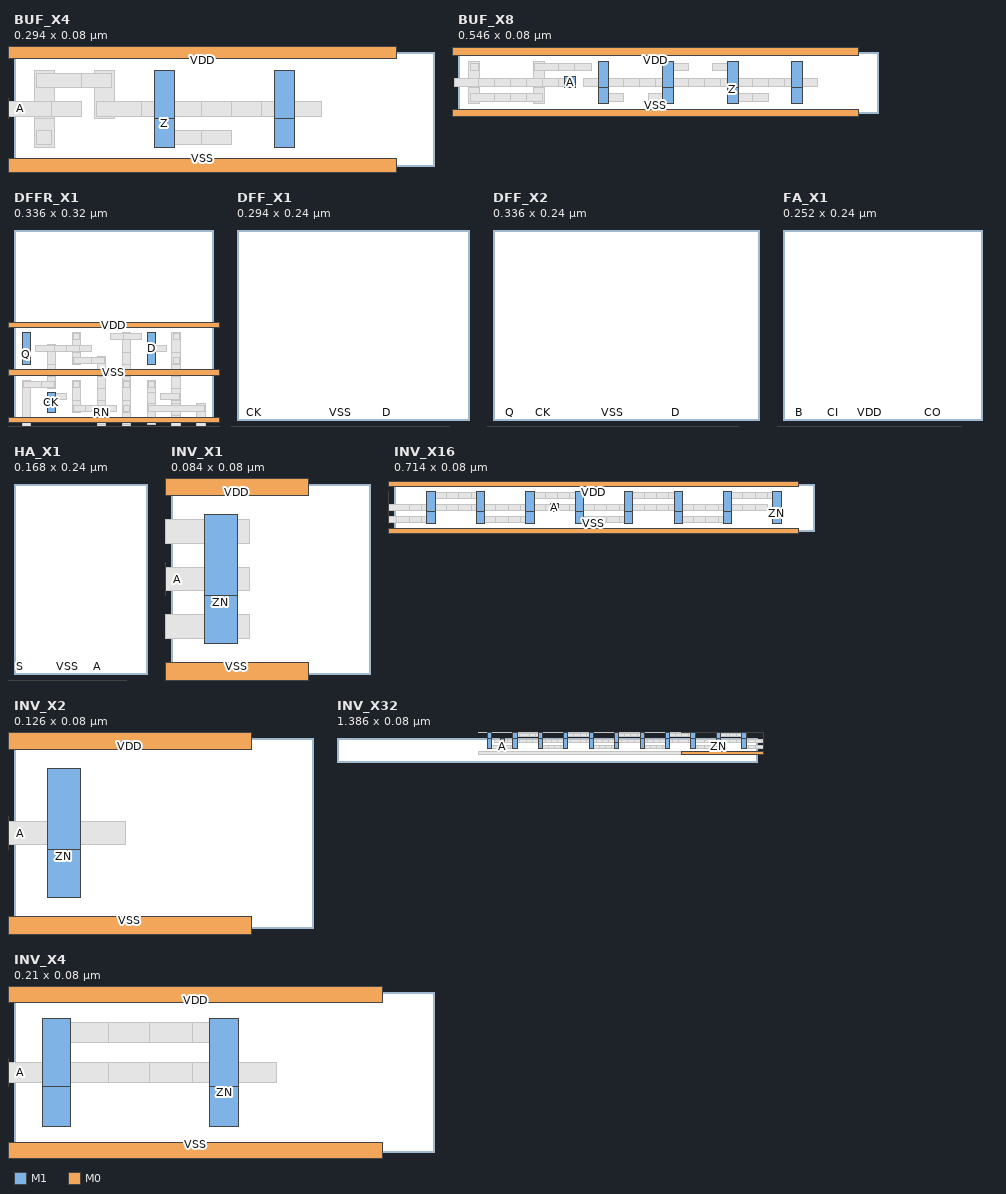
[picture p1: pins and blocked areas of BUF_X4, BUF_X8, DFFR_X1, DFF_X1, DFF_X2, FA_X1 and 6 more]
MACRO BUF_X4
  CLASS CORE ;
  FOREIGN BUF_X4 0 0 ;
  ORIGIN -0.0210 0.0000 ;
  SIZE 0.2940 BY 0.0800 ;
  SITE FSFET ;
  SYMMETRY X Y ;
  PIN A
    DIRECTION INPUT ;
    USE SIGNAL ;
    PORT
      LAYER M1 ;
        RECT -0.0060 0.0330 0.0080 0.0470 ;
    END
  END A
  PIN Z
    DIRECTION OUTPUT ;
    USE SIGNAL ;
    PORT
      LAYER M1 ;
        RECT 0.2030 0.0130 0.2170 0.0470 ;
        RECT 0.2030 0.0330 0.2170 0.0670 ;
        RECT 0.1190 0.0130 0.1330 0.0470 ;
        RECT 0.1190 0.0330 0.1330 0.0670 ;
    END
  END Z
  PIN VSS
    DIRECTION INOUT ;
    USE GROUND ;
    PORT
      LAYER M0 ;
        RECT -0.0370 -0.0050 0.2890 0.0050 ;
    END
  END VSS
  PIN VDD
    DIRECTION INOUT ;
    USE POWER ;
    PORT
      LAYER M0 ;
        RECT -0.0370 0.0750 0.2890 0.0850 ;
    END
  END VDD
  OBS
    LAYER M1 ;
      RECT 0.0770 0.0330 0.0910 0.0670 ;
      RECT 0.0350 0.0130 0.0490 0.0470 ;
      RECT 0.0350 0.0330 0.0490 0.0670 ;
    LAYER M0 ;
      RECT -0.0060 0.0350 0.0510 0.0450 ;
      RECT 0.2050 0.0550 0.2150 0.0650 ;
      RECT 0.1210 0.0550 0.1310 0.0650 ;
      RECT 0.0370 0.0150 0.0470 0.0250 ;
      RECT 0.0370 0.0350 0.0680 0.0450 ;
      RECT 0.0160 0.0350 0.0470 0.0450 ;
      RECT 0.1420 0.0150 0.1730 0.0250 ;
      RECT 0.1210 0.0150 0.1520 0.0250 ;
      RECT 0.2050 0.0350 0.2360 0.0450 ;
      RECT 0.1840 0.0350 0.2150 0.0450 ;
      RECT 0.1630 0.0350 0.1940 0.0450 ;
      RECT 0.1420 0.0350 0.1730 0.0450 ;
      RECT 0.1210 0.0350 0.1520 0.0450 ;
      RECT 0.1000 0.0350 0.1310 0.0450 ;
      RECT 0.0790 0.0350 0.1100 0.0450 ;
      RECT 0.0580 0.0550 0.0890 0.0650 ;
      RECT 0.0370 0.0550 0.0680 0.0650 ;
  END
END BUF_X4

MACRO BUF_X8
  CLASS CORE ;
  FOREIGN BUF_X8 0 0 ;
  ORIGIN -0.0210 0.0000 ;
  SIZE 0.5460 BY 0.0800 ;
  SITE FSFET ;
  SYMMETRY X Y ;
  PIN Z
    DIRECTION OUTPUT ;
    USE SIGNAL ;
    PORT
      LAYER M1 ;
        RECT 0.4550 0.0130 0.4690 0.0470 ;
        RECT 0.4550 0.0330 0.4690 0.0670 ;
        RECT 0.3710 0.0130 0.3850 0.0470 ;
        RECT 0.3710 0.0330 0.3850 0.0670 ;
        RECT 0.2870 0.0130 0.3010 0.0470 ;
        RECT 0.2870 0.0330 0.3010 0.0670 ;
        RECT 0.2030 0.0130 0.2170 0.0470 ;
        RECT 0.2030 0.0330 0.2170 0.0670 ;
    END
  END Z
  PIN A
    DIRECTION INPUT ;
    USE SIGNAL ;
    PORT
      LAYER M1 ;
        RECT 0.1600 0.0330 0.1740 0.0470 ;
    END
  END A
  PIN VSS
    DIRECTION INOUT ;
    USE GROUND ;
    PORT
      LAYER M0 ;
        RECT -0.0370 -0.0050 0.5410 0.0050 ;
    END
  END VSS
  PIN VDD
    DIRECTION INOUT ;
    USE POWER ;
    PORT
      LAYER M0 ;
        RECT -0.0370 0.0750 0.5410 0.0850 ;
    END
  END VDD
  OBS
    LAYER M1 ;
      RECT 0.1190 0.0130 0.1330 0.0470 ;
      RECT 0.1190 0.0330 0.1330 0.0670 ;
      RECT 0.0350 0.0130 0.0490 0.0470 ;
      RECT 0.0350 0.0330 0.0490 0.0670 ;
    LAYER M0 ;
      RECT 0.1410 0.0350 0.1740 0.0450 ;
      RECT 0.4570 0.0550 0.4670 0.0650 ;
      RECT 0.2050 0.0550 0.2150 0.0650 ;
      RECT 0.0370 0.0550 0.0470 0.0650 ;
      RECT 0.1210 0.0350 0.1520 0.0450 ;
      RECT 0.1000 0.0350 0.1310 0.0450 ;
      RECT 0.0790 0.0350 0.1100 0.0450 ;
      RECT 0.0580 0.0350 0.0890 0.0450 ;
      RECT 0.0370 0.0350 0.0680 0.0450 ;
      RECT 0.0160 0.0350 0.0470 0.0450 ;
      RECT 0.3940 0.0150 0.4250 0.0250 ;
      RECT 0.3730 0.0150 0.4040 0.0250 ;
      RECT 0.2680 0.0150 0.2990 0.0250 ;
      RECT 0.2050 0.0150 0.2360 0.0250 ;
      RECT 0.3520 0.0550 0.3830 0.0650 ;
      RECT 0.2890 0.0550 0.3200 0.0650 ;
      RECT 0.1000 0.0150 0.1310 0.0250 ;
      RECT 0.0790 0.0150 0.1100 0.0250 ;
      RECT 0.0580 0.0150 0.0890 0.0250 ;
      RECT 0.0370 0.0150 0.0680 0.0250 ;
      RECT 0.4570 0.0350 0.4880 0.0450 ;
      RECT 0.4360 0.0350 0.4670 0.0450 ;
      RECT 0.4150 0.0350 0.4460 0.0450 ;
      RECT 0.3940 0.0350 0.4250 0.0450 ;
      RECT 0.3730 0.0350 0.4040 0.0450 ;
      RECT 0.3520 0.0350 0.3830 0.0450 ;
      RECT 0.3310 0.0350 0.3620 0.0450 ;
      RECT 0.3100 0.0350 0.3410 0.0450 ;
      RECT 0.2890 0.0350 0.3200 0.0450 ;
      RECT 0.2680 0.0350 0.2990 0.0450 ;
      RECT 0.2470 0.0350 0.2780 0.0450 ;
      RECT 0.2260 0.0350 0.2570 0.0450 ;
      RECT 0.2050 0.0350 0.2360 0.0450 ;
      RECT 0.1840 0.0350 0.2150 0.0450 ;
      RECT 0.1630 0.0550 0.1940 0.0650 ;
      RECT 0.1420 0.0550 0.1730 0.0650 ;
      RECT 0.1210 0.0550 0.1520 0.0650 ;
  END
END BUF_X8

MACRO DFFR_X1
  CLASS CORE ;
  FOREIGN DFFR_X1 0 0 ;
  ORIGIN 0.0000 -0.0800 ;
  SIZE 0.3360 BY 0.3200 ;
  SITE FSFET ;
  SYMMETRY X Y ;
  PIN Q
    DIRECTION OUTPUT ;
    USE SIGNAL ;
    PORT
      LAYER M1 ;
        RECT 0.0140 0.1730 0.0280 0.2070 ;
        RECT 0.0140 0.1930 0.0280 0.2270 ;
    END
  END Q
  PIN QN
    DIRECTION OUTPUT ;
    USE SIGNAL ;
    PORT
      LAYER M1 ;
        RECT 0.0560 0.0130 0.0700 0.0670 ;
    END
  END QN
  PIN CK
    DIRECTION INPUT ;
    USE CLOCK ;
    PORT
      LAYER M1 ;
        RECT 0.0560 0.0930 0.0700 0.1270 ;
    END
  END CK
  PIN D
    DIRECTION INPUT ;
    USE SIGNAL ;
    PORT
      LAYER M1 ;
        RECT 0.2240 0.1730 0.2380 0.2270 ;
    END
  END D
  PIN RN
    DIRECTION INPUT ;
    USE SIGNAL ;
    PORT
      LAYER M1 ;
        RECT 0.1400 -0.0670 0.1540 -0.0130 ;
    END
  END RN
  PIN VSS
    DIRECTION INOUT ;
    USE GROUND ;
    PORT
      LAYER M0 ;
        RECT -0.0160 0.1550 0.3520 0.1650 ;
    END
  END VSS
  PIN VSS
    DIRECTION INOUT ;
    USE GROUND ;
    PORT
      LAYER M0 ;
        RECT -0.0160 -0.0050 0.3520 0.0050 ;
    END
  END VSS
  PIN VDD
    DIRECTION INOUT ;
    USE POWER ;
    PORT
      LAYER M0 ;
        RECT -0.0160 0.0750 0.3520 0.0850 ;
    END
  END VDD
  PIN VDD
    DIRECTION INOUT ;
    USE POWER ;
    PORT
      LAYER M0 ;
        RECT -0.0160 0.2350 0.3520 0.2450 ;
    END
  END VDD
  PIN VDD_3
    DIRECTION INOUT ;
    USE POWER ;
    PORT
      LAYER M0 ;
        RECT -0.0160 -0.0850 0.3520 -0.0750 ;
    END
  END VDD_3
  OBS
    LAYER M1 ;
      RECT 0.1820 -0.0670 0.1960 -0.0330 ;
      RECT 0.1820 0.1330 0.1960 0.1670 ;
      RECT 0.1820 0.1530 0.1960 0.1870 ;
      RECT 0.1820 0.1730 0.1960 0.2070 ;
      RECT 0.1820 0.1930 0.1960 0.2270 ;
      RECT 0.2660 0.0930 0.2800 0.1270 ;
      RECT 0.2660 0.0730 0.2800 0.1070 ;
      RECT 0.2660 0.0530 0.2800 0.0870 ;
      RECT 0.2660 0.0330 0.2800 0.0670 ;
      RECT 0.2660 -0.0670 0.2800 0.0470 ;
      RECT 0.2240 0.1130 0.2380 0.1470 ;
      RECT 0.2240 0.0930 0.2380 0.1270 ;
      RECT 0.2660 0.1130 0.2800 0.1470 ;
      RECT 0.2660 0.1330 0.2800 0.1670 ;
      RECT 0.2660 0.1530 0.2800 0.1870 ;
      RECT 0.2660 0.1730 0.2800 0.2070 ;
      RECT 0.2660 0.1930 0.2800 0.2270 ;
      RECT 0.0560 0.1330 0.0700 0.1670 ;
      RECT 0.0560 0.1530 0.0700 0.1870 ;
      RECT 0.0560 0.1730 0.0700 0.2070 ;
      RECT 0.0140 -0.0670 0.0280 0.1470 ;
      RECT 0.0980 0.0930 0.1120 0.1270 ;
      RECT 0.0980 0.1130 0.1120 0.1470 ;
      RECT 0.1820 0.0130 0.1960 0.0470 ;
      RECT 0.1820 0.0330 0.1960 0.0670 ;
      RECT 0.1820 0.0530 0.1960 0.0870 ;
      RECT 0.1820 0.0730 0.1960 0.1070 ;
      RECT 0.1820 0.0930 0.1960 0.1270 ;
      RECT 0.1820 0.1130 0.1960 0.1470 ;
      RECT 0.1400 0.0530 0.1540 0.0870 ;
      RECT 0.1400 0.0730 0.1540 0.1070 ;
      RECT 0.1400 0.0930 0.1540 0.1270 ;
      RECT 0.1400 0.1130 0.1540 0.1470 ;
      RECT 0.1400 0.1330 0.1540 0.1670 ;
      RECT 0.1400 0.1530 0.1540 0.1870 ;
      RECT 0.0980 -0.0310 0.1120 0.0470 ;
      RECT 0.0980 0.0330 0.1120 0.0670 ;
      RECT 0.0980 0.1730 0.1120 0.2070 ;
      RECT 0.0980 0.1930 0.1120 0.2270 ;
      RECT 0.2240 -0.0670 0.2380 0.0670 ;
      RECT 0.2240 0.0730 0.2380 0.1070 ;
      RECT 0.3080 0.0530 0.3220 0.1070 ;
    LAYER M0 ;
      RECT 0.2260 0.0350 0.2570 0.0450 ;
      RECT 0.2680 0.2150 0.2780 0.2250 ;
      RECT 0.2680 0.1750 0.2780 0.1850 ;
      RECT 0.1840 0.0150 0.1940 0.0250 ;
      RECT 0.1420 0.0350 0.1730 0.0450 ;
      RECT 0.1630 0.0350 0.1940 0.0450 ;
      RECT 0.1840 0.0350 0.2150 0.0450 ;
      RECT 0.0580 0.1150 0.0890 0.1250 ;
      RECT 0.2260 0.1950 0.2570 0.2050 ;
      RECT 0.1210 0.1750 0.1520 0.1850 ;
      RECT 0.1000 0.1750 0.1310 0.1850 ;
      RECT 0.2470 0.1150 0.2780 0.1250 ;
      RECT 0.0370 0.1350 0.0680 0.1450 ;
      RECT 0.0160 0.1350 0.0470 0.1450 ;
      RECT 0.1000 0.1950 0.1310 0.2050 ;
      RECT 0.0790 0.1950 0.1100 0.2050 ;
      RECT 0.0580 0.1950 0.0890 0.2050 ;
      RECT 0.2050 0.0350 0.2360 0.0450 ;
      RECT 0.1630 0.2150 0.1940 0.2250 ;
      RECT 0.1840 0.2150 0.2150 0.2250 ;
      RECT 0.2470 0.0350 0.2780 0.0450 ;
      RECT 0.2260 0.1350 0.2360 0.1450 ;
      RECT 0.1840 -0.0650 0.1940 -0.0550 ;
      RECT 0.0160 0.2150 0.0260 0.2250 ;
      RECT 0.0160 0.0150 0.0680 0.0250 ;
      RECT 0.1000 0.0950 0.1310 0.1050 ;
      RECT 0.1210 0.0950 0.1520 0.1050 ;
      RECT 0.1420 0.0950 0.1730 0.1050 ;
      RECT 0.1630 0.0150 0.1940 0.0250 ;
      RECT 0.0160 0.1750 0.0260 0.1850 ;
      RECT 0.1840 0.1350 0.1940 0.1450 ;
      RECT 0.1000 0.1350 0.1100 0.1450 ;
      RECT 0.0370 0.1950 0.0680 0.2050 ;
      RECT 0.1630 0.0550 0.2150 0.0650 ;
      RECT 0.1000 0.0550 0.1310 0.0650 ;
      RECT 0.1210 0.0350 0.1520 0.0450 ;
      RECT 0.1210 0.0550 0.1520 0.0650 ;
      RECT 0.0160 0.0550 0.0680 0.0650 ;
      RECT 0.1840 -0.0450 0.2780 -0.0350 ;
      RECT 0.2680 -0.0250 0.2780 -0.0150 ;
      RECT 0.2260 0.0950 0.3200 0.1050 ;
      RECT 0.1000 0.2150 0.1100 0.2250 ;
      RECT 0.0370 -0.0250 0.1100 -0.0150 ;
      RECT 0.1840 0.0950 0.1940 0.1050 ;
      RECT 0.2470 0.0550 0.3200 0.0650 ;
      RECT 0.0160 -0.0250 0.0260 -0.0150 ;
      RECT 0.0160 -0.0650 0.0260 -0.0550 ;
      RECT 0.0160 -0.0650 0.1100 -0.0550 ;
      RECT 0.2260 0.0550 0.2360 0.0650 ;
      RECT 0.2260 -0.0650 0.2360 -0.0550 ;
      RECT 0.2680 -0.0650 0.2780 -0.0550 ;
      RECT 0.1420 -0.0250 0.2150 -0.0150 ;
      RECT 0.0790 -0.0450 0.1520 -0.0350 ;
      RECT 0.1000 0.0150 0.1100 0.0250 ;
  END
END DFFR_X1

MACRO DFF_X1
  CLASS CORE ;
  FOREIGN DFF_X1 0 0 ;
  ORIGIN -0.0210 -0.1600 ;
  SIZE 0.2940 BY 0.2400 ;
  SITE FSFET ;
  SYMMETRY X Y ;
  PIN Q
    DIRECTION OUTPUT ;
    USE SIGNAL ;
    PORT
      LAYER M1 ;
        RECT -0.0070 0.0130 0.0070 0.0470 ;
        RECT -0.0070 0.0330 0.0070 0.0670 ;
    END
  END Q
  PIN QN
    DIRECTION OUTPUT ;
    USE SIGNAL ;
    PORT
      LAYER M1 ;
        RECT -0.0070 -0.1470 0.0070 -0.1130 ;
        RECT -0.0070 -0.1270 0.0070 -0.0930 ;
    END
  END QN
  PIN CK
    DIRECTION INPUT ;
    USE CLOCK ;
    PORT
      LAYER M1 ;
        RECT 0.0350 -0.0670 0.0490 -0.0330 ;
    END
  END CK
  PIN D
    DIRECTION INPUT ;
    USE SIGNAL ;
    PORT
      LAYER M1 ;
        RECT 0.2030 0.0130 0.2170 0.0670 ;
    END
  END D
  PIN VSS
    DIRECTION INOUT ;
    USE GROUND ;
    PORT
      LAYER M0 ;
        RECT -0.0370 -0.0050 0.2890 0.0050 ;
    END
  END VSS
  PIN VSS
    DIRECTION INOUT ;
    USE GROUND ;
    PORT
      LAYER M0 ;
        RECT -0.0370 -0.1650 0.2890 -0.1550 ;
    END
  END VSS
  PIN VDD
    DIRECTION INOUT ;
    USE POWER ;
    PORT
      LAYER M0 ;
        RECT -0.0370 -0.0850 0.2890 -0.0750 ;
    END
  END VDD
  PIN VDD
    DIRECTION INOUT ;
    USE POWER ;
    PORT
      LAYER M0 ;
        RECT -0.0370 0.0750 0.2890 0.0850 ;
    END
  END VDD
  OBS
    LAYER M1 ;
      RECT 0.1190 -0.1070 0.1330 -0.0730 ;
      RECT 0.1190 -0.0870 0.1330 -0.0530 ;
      RECT 0.1190 -0.0670 0.1330 -0.0330 ;
      RECT 0.1190 -0.0470 0.1330 -0.0130 ;
      RECT 0.1190 -0.0270 0.1330 0.0070 ;
      RECT 0.1190 -0.0070 0.1330 0.0270 ;
      RECT 0.0770 -0.1470 0.0910 -0.1130 ;
      RECT 0.0770 -0.1270 0.0910 -0.0930 ;
      RECT 0.0770 0.0130 0.0910 0.0470 ;
      RECT 0.0770 0.0330 0.0910 0.0670 ;
      RECT 0.2030 -0.1070 0.2170 -0.0730 ;
      RECT 0.2030 -0.0870 0.2170 -0.0530 ;
      RECT 0.2030 -0.0670 0.2170 -0.0330 ;
      RECT 0.2030 -0.0470 0.2170 -0.0130 ;
      RECT 0.2450 -0.1470 0.2590 -0.1130 ;
      RECT 0.2450 -0.1270 0.2590 -0.0930 ;
      RECT 0.2450 -0.1070 0.2590 -0.0730 ;
      RECT 0.2450 -0.0870 0.2590 -0.0530 ;
      RECT 0.2450 -0.0670 0.2590 -0.0330 ;
      RECT 0.2450 -0.0470 0.2590 -0.0130 ;
      RECT 0.2450 -0.0270 0.2590 0.0070 ;
      RECT 0.2450 -0.0070 0.2590 0.0270 ;
      RECT 0.2450 0.0130 0.2590 0.0470 ;
      RECT 0.2450 0.0330 0.2590 0.0670 ;
      RECT 0.0350 -0.0270 0.0490 0.0070 ;
      RECT 0.0350 -0.0070 0.0490 0.0270 ;
      RECT 0.0350 0.0130 0.0490 0.0470 ;
      RECT -0.0070 -0.0670 0.0070 -0.0330 ;
      RECT -0.0070 -0.0470 0.0070 -0.0130 ;
      RECT 0.0770 -0.0670 0.0910 -0.0330 ;
      RECT 0.0770 -0.0470 0.0910 -0.0130 ;
      RECT 0.1610 -0.1470 0.1750 -0.1130 ;
      RECT 0.1610 -0.1270 0.1750 -0.0930 ;
      RECT 0.1610 -0.1070 0.1750 -0.0730 ;
      RECT 0.1610 -0.0870 0.1750 -0.0530 ;
      RECT 0.1610 -0.0670 0.1750 -0.0330 ;
      RECT 0.1610 -0.0470 0.1750 -0.0130 ;
      RECT 0.1610 -0.0270 0.1750 0.0070 ;
      RECT 0.1610 -0.0070 0.1750 0.0270 ;
      RECT 0.1610 0.0130 0.1750 0.0470 ;
      RECT 0.1610 0.0330 0.1750 0.0670 ;
    LAYER M0 ;
      RECT 0.1420 -0.1050 0.1940 -0.0950 ;
      RECT 0.0370 -0.0450 0.0680 -0.0350 ;
      RECT 0.2050 0.0350 0.2360 0.0450 ;
      RECT 0.0790 0.0550 0.0890 0.0650 ;
      RECT 0.2050 -0.0650 0.2150 -0.0550 ;
      RECT 0.2050 -0.0250 0.2150 -0.0150 ;
      RECT 0.2470 -0.1450 0.2570 -0.1350 ;
      RECT 0.2470 -0.1050 0.2570 -0.0950 ;
      RECT 0.2470 0.0150 0.2570 0.0250 ;
      RECT 0.2470 0.0550 0.2570 0.0650 ;
      RECT -0.0050 -0.0650 0.0050 -0.0550 ;
      RECT 0.0790 -0.0250 0.0890 -0.0150 ;
      RECT 0.1630 -0.0650 0.1730 -0.0550 ;
      RECT 0.1630 -0.0250 0.1730 -0.0150 ;
      RECT -0.0050 -0.1450 0.0050 -0.1350 ;
      RECT -0.0050 -0.1050 0.0050 -0.0950 ;
      RECT -0.0050 0.0150 0.0050 0.0250 ;
      RECT -0.0050 0.0550 0.0050 0.0650 ;
      RECT 0.0580 -0.1450 0.0890 -0.1350 ;
      RECT 0.0370 -0.1450 0.0680 -0.1350 ;
      RECT 0.0160 -0.1450 0.0470 -0.1350 ;
      RECT 0.1000 -0.1050 0.1310 -0.0950 ;
      RECT 0.0790 -0.1050 0.1100 -0.0950 ;
      RECT 0.1000 0.0150 0.1310 0.0250 ;
      RECT 0.0790 0.0150 0.1100 0.0250 ;
      RECT 0.2050 -0.1050 0.2360 -0.0950 ;
      RECT 0.2260 -0.1250 0.2570 -0.1150 ;
      RECT 0.2050 -0.1250 0.2360 -0.1150 ;
      RECT 0.1840 -0.1250 0.2150 -0.1150 ;
      RECT 0.1630 -0.1250 0.1940 -0.1150 ;
      RECT 0.1420 -0.1250 0.1730 -0.1150 ;
      RECT 0.1210 -0.1250 0.1520 -0.1150 ;
      RECT 0.1000 -0.1250 0.1310 -0.1150 ;
      RECT 0.2260 -0.0450 0.2570 -0.0350 ;
      RECT 0.0160 -0.0250 0.0470 -0.0150 ;
      RECT -0.0050 -0.0250 0.0260 -0.0150 ;
      RECT 0.0790 0.0350 0.1100 0.0450 ;
      RECT 0.0580 0.0350 0.0890 0.0450 ;
      RECT 0.0370 0.0350 0.0680 0.0450 ;
      RECT 0.0160 0.0350 0.0470 0.0450 ;
      RECT 0.1210 -0.0650 0.1520 -0.0550 ;
      RECT 0.1000 -0.0650 0.1310 -0.0550 ;
      RECT 0.0790 -0.0650 0.1100 -0.0550 ;
      RECT 0.1630 -0.1450 0.1940 -0.1350 ;
      RECT 0.1420 -0.1450 0.1730 -0.1350 ;
      RECT 0.1630 0.0550 0.1940 0.0650 ;
      RECT 0.1420 0.0550 0.1730 0.0650 ;
  END
END DFF_X1

MACRO DFF_X2
  CLASS CORE ;
  FOREIGN DFF_X2 0 0 ;
  ORIGIN -0.0210 -0.1600 ;
  SIZE 0.3360 BY 0.2400 ;
  SITE FSFET ;
  SYMMETRY X Y ;
  PIN QN
    DIRECTION OUTPUT ;
    USE SIGNAL ;
    PORT
      LAYER M1 ;
        RECT 0.0350 -0.1470 0.0490 -0.1130 ;
        RECT 0.0350 -0.1270 0.0490 -0.0930 ;
    END
  END QN
  PIN Q
    DIRECTION OUTPUT ;
    USE SIGNAL ;
    PORT
      LAYER M1 ;
        RECT 0.0350 0.0130 0.0490 0.0470 ;
        RECT 0.0350 0.0330 0.0490 0.0670 ;
    END
  END Q
  PIN CK
    DIRECTION INPUT ;
    USE CLOCK ;
    PORT
      LAYER M1 ;
        RECT 0.0770 -0.0470 0.0910 -0.0330 ;
    END
  END CK
  PIN D
    DIRECTION INPUT ;
    USE SIGNAL ;
    PORT
      LAYER M1 ;
        RECT 0.2450 0.0330 0.2590 0.0670 ;
    END
  END D
  PIN VDD
    DIRECTION INOUT ;
    USE POWER ;
    PORT
      LAYER M0 ;
        RECT -0.0370 0.0750 0.3310 0.0850 ;
    END
  END VDD
  PIN VDD
    DIRECTION INOUT ;
    USE POWER ;
    PORT
      LAYER M0 ;
        RECT -0.0370 -0.0850 0.3310 -0.0750 ;
    END
  END VDD
  PIN VSS
    DIRECTION INOUT ;
    USE GROUND ;
    PORT
      LAYER M0 ;
        RECT -0.0370 -0.1650 0.3310 -0.1550 ;
    END
  END VSS
  PIN VSS
    DIRECTION INOUT ;
    USE GROUND ;
    PORT
      LAYER M0 ;
        RECT -0.0370 -0.0050 0.3310 0.0050 ;
    END
  END VSS
  OBS
    LAYER M1 ;
      RECT 0.1610 -0.1070 0.1750 -0.0730 ;
      RECT 0.1610 -0.0870 0.1750 -0.0530 ;
      RECT 0.1610 -0.0670 0.1750 -0.0330 ;
      RECT 0.1610 -0.0470 0.1750 -0.0130 ;
      RECT 0.1610 -0.0270 0.1750 0.0070 ;
      RECT 0.1610 -0.0070 0.1750 0.0270 ;
      RECT 0.1190 -0.1470 0.1330 -0.1130 ;
      RECT 0.1190 -0.1270 0.1330 -0.0930 ;
      RECT 0.1190 0.0130 0.1330 0.0470 ;
      RECT 0.1190 0.0330 0.1330 0.0670 ;
      RECT 0.2450 -0.1070 0.2590 -0.0730 ;
      RECT 0.2450 -0.0870 0.2590 -0.0530 ;
      RECT 0.2450 -0.0670 0.2590 -0.0330 ;
      RECT 0.2450 -0.0470 0.2590 -0.0130 ;
      RECT 0.2870 -0.1470 0.3010 -0.1130 ;
      RECT 0.2870 -0.1270 0.3010 -0.0930 ;
      RECT 0.2870 -0.1070 0.3010 -0.0730 ;
      RECT 0.2870 -0.0870 0.3010 -0.0530 ;
      RECT 0.2870 -0.0670 0.3010 -0.0330 ;
      RECT 0.2870 -0.0470 0.3010 -0.0130 ;
      RECT 0.2870 -0.0270 0.3010 0.0070 ;
      RECT 0.2870 -0.0070 0.3010 0.0270 ;
      RECT 0.2870 0.0130 0.3010 0.0470 ;
      RECT 0.2870 0.0330 0.3010 0.0670 ;
      RECT 0.0770 -0.0270 0.0910 0.0070 ;
      RECT 0.0770 -0.0070 0.0910 0.0270 ;
      RECT 0.0770 0.0130 0.0910 0.0470 ;
      RECT 0.0350 -0.0670 0.0490 -0.0330 ;
      RECT 0.0350 -0.0470 0.0490 -0.0130 ;
      RECT 0.1190 -0.0670 0.1330 -0.0330 ;
      RECT 0.1190 -0.0470 0.1330 -0.0130 ;
      RECT 0.2030 -0.1470 0.2170 -0.1130 ;
      RECT 0.2030 -0.1270 0.2170 -0.0930 ;
      RECT 0.2030 -0.1070 0.2170 -0.0730 ;
      RECT 0.2030 -0.0870 0.2170 -0.0530 ;
      RECT 0.2030 -0.0670 0.2170 -0.0330 ;
      RECT 0.2030 -0.0470 0.2170 -0.0130 ;
      RECT 0.2030 -0.0270 0.2170 0.0070 ;
      RECT 0.2030 -0.0070 0.2170 0.0270 ;
      RECT 0.2030 0.0130 0.2170 0.0470 ;
      RECT 0.2030 0.0330 0.2170 0.0670 ;
    LAYER M0 ;
      RECT 0.0790 -0.0450 0.1100 -0.0350 ;
      RECT 0.2470 0.0550 0.2780 0.0650 ;
      RECT 0.1210 0.0550 0.1310 0.0650 ;
      RECT 0.2470 -0.0650 0.2570 -0.0550 ;
      RECT 0.2470 -0.0250 0.2570 -0.0150 ;
      RECT 0.2890 -0.1450 0.2990 -0.1350 ;
      RECT 0.2890 -0.1050 0.2990 -0.0950 ;
      RECT 0.2890 0.0150 0.2990 0.0250 ;
      RECT 0.2890 0.0550 0.2990 0.0650 ;
      RECT 0.0370 -0.0650 0.0470 -0.0550 ;
      RECT 0.1210 -0.0250 0.1310 -0.0150 ;
      RECT 0.2050 -0.0650 0.2150 -0.0550 ;
      RECT 0.2050 -0.0250 0.2150 -0.0150 ;
      RECT 0.0370 -0.1450 0.0470 -0.1350 ;
      RECT 0.0370 -0.1050 0.0470 -0.0950 ;
      RECT 0.0370 0.0150 0.0470 0.0250 ;
      RECT 0.0370 0.0550 0.0470 0.0650 ;
      RECT 0.1000 -0.1450 0.1310 -0.1350 ;
      RECT 0.0790 -0.1450 0.1100 -0.1350 ;
      RECT 0.0580 -0.1450 0.0890 -0.1350 ;
      RECT 0.0370 -0.1250 0.0680 -0.1150 ;
      RECT 0.0160 -0.1250 0.0470 -0.1150 ;
      RECT 0.1420 -0.1050 0.1730 -0.0950 ;
      RECT 0.1210 -0.1050 0.1520 -0.0950 ;
      RECT 0.1420 0.0150 0.1730 0.0250 ;
      RECT 0.1210 0.0150 0.1520 0.0250 ;
      RECT 0.2470 -0.1050 0.2780 -0.0950 ;
      RECT 0.2680 -0.1250 0.2990 -0.1150 ;
      RECT 0.2470 -0.1250 0.2780 -0.1150 ;
      RECT 0.2260 -0.1250 0.2570 -0.1150 ;
      RECT 0.2050 -0.1250 0.2360 -0.1150 ;
      RECT 0.1840 -0.1250 0.2150 -0.1150 ;
      RECT 0.1630 -0.1250 0.1940 -0.1150 ;
      RECT 0.1420 -0.1250 0.1730 -0.1150 ;
      RECT 0.2680 -0.0450 0.2990 -0.0350 ;
      RECT 0.0580 -0.0250 0.0890 -0.0150 ;
      RECT 0.0370 -0.0250 0.0680 -0.0150 ;
      RECT 0.1210 0.0350 0.1520 0.0450 ;
      RECT 0.1000 0.0350 0.1310 0.0450 ;
      RECT 0.0790 0.0350 0.1100 0.0450 ;
      RECT 0.0580 0.0350 0.0890 0.0450 ;
      RECT 0.0370 0.0350 0.0680 0.0450 ;
      RECT 0.0160 0.0350 0.0470 0.0450 ;
      RECT 0.1630 -0.0650 0.1940 -0.0550 ;
      RECT 0.1420 -0.0650 0.1730 -0.0550 ;
      RECT 0.1210 -0.0650 0.1520 -0.0550 ;
      RECT 0.2050 -0.1450 0.2360 -0.1350 ;
      RECT 0.1840 -0.1450 0.2150 -0.1350 ;
      RECT 0.2050 0.0550 0.2360 0.0650 ;
      RECT 0.1840 0.0550 0.2150 0.0650 ;
      RECT 0.1840 -0.0450 0.2360 -0.0350 ;
  END
END DFF_X2

MACRO FA_X1
  CLASS CORE ;
  FOREIGN FA_X1 0 0 ;
  ORIGIN -0.0210 -0.1600 ;
  SIZE 0.2520 BY 0.2400 ;
  SITE FSFET ;
  SYMMETRY X Y ;
  PIN B
    DIRECTION INPUT ;
    USE SIGNAL ;
    PORT
      LAYER M1 ;
        RECT 0.0350 0.0330 0.0490 0.0470 ;
    END
  END B
  PIN A
    DIRECTION INPUT ;
    USE SIGNAL ;
    PORT
      LAYER M1 ;
        RECT -0.0070 0.0330 0.0070 0.0470 ;
    END
  END A
  PIN S
    DIRECTION OUTPUT ;
    USE SIGNAL ;
    PORT
      LAYER M1 ;
        RECT 0.2030 -0.1470 0.2170 -0.1130 ;
        RECT 0.2030 -0.1270 0.2170 -0.0930 ;
    END
  END S
  PIN CO
    DIRECTION OUTPUT ;
    USE SIGNAL ;
    PORT
      LAYER M1 ;
        RECT 0.2030 0.0130 0.2170 0.0470 ;
        RECT 0.2030 0.0330 0.2170 0.0670 ;
    END
  END CO
  PIN CI
    DIRECTION INPUT ;
    USE SIGNAL ;
    PORT
      LAYER M1 ;
        RECT 0.0770 0.0330 0.0910 0.0470 ;
    END
  END CI
  PIN VDD
    DIRECTION INOUT ;
    USE POWER ;
    PORT
      LAYER M0 ;
        RECT -0.0370 -0.1650 0.2470 -0.1550 ;
    END
  END VDD
  PIN VDD
    DIRECTION INOUT ;
    USE POWER ;
    PORT
      LAYER M0 ;
        RECT -0.0370 -0.0050 0.2470 0.0050 ;
    END
  END VDD
  PIN VSS
    DIRECTION INOUT ;
    USE GROUND ;
    PORT
      LAYER M0 ;
        RECT -0.0370 -0.0850 0.2470 -0.0750 ;
    END
  END VSS
  PIN VSS
    DIRECTION INOUT ;
    USE GROUND ;
    PORT
      LAYER M0 ;
        RECT -0.0370 0.0750 0.2470 0.0850 ;
    END
  END VSS
  OBS
    LAYER M1 ;
      RECT 0.1610 -0.1070 0.1750 -0.0730 ;
      RECT 0.1610 -0.0870 0.1750 -0.0530 ;
      RECT 0.1610 -0.0670 0.1750 -0.0330 ;
      RECT 0.1610 -0.0470 0.1750 -0.0130 ;
      RECT 0.1190 -0.1470 0.1330 -0.1130 ;
      RECT 0.1190 -0.1270 0.1330 -0.0930 ;
      RECT 0.1190 -0.0470 0.1330 -0.0130 ;
      RECT 0.1190 -0.0270 0.1330 0.0070 ;
      RECT 0.1190 -0.0070 0.1330 0.0270 ;
      RECT 0.1190 0.0130 0.1330 0.0470 ;
      RECT 0.1190 0.0330 0.1330 0.0670 ;
      RECT 0.0770 -0.1270 0.0910 -0.0330 ;
      RECT 0.0770 -0.1470 0.0910 -0.1130 ;
    LAYER M0 ;
      RECT 0.2050 -0.1450 0.2150 -0.1350 ;
      RECT 0.2050 -0.1050 0.2150 -0.0950 ;
      RECT 0.1210 -0.1450 0.1310 -0.1350 ;
      RECT 0.1630 -0.0650 0.1730 -0.0550 ;
      RECT 0.1630 -0.0250 0.1730 -0.0150 ;
      RECT 0.1210 0.0550 0.1310 0.0650 ;
      RECT 0.2050 0.0150 0.2150 0.0250 ;
      RECT 0.2050 0.0550 0.2150 0.0650 ;
      RECT 0.1630 -0.1050 0.1940 -0.0950 ;
      RECT 0.1420 -0.1050 0.1730 -0.0950 ;
      RECT 0.1210 -0.1050 0.1520 -0.0950 ;
      RECT 0.1000 -0.0650 0.1310 -0.0550 ;
      RECT 0.0790 -0.0650 0.1100 -0.0550 ;
      RECT 0.0580 -0.0650 0.0890 -0.0550 ;
      RECT 0.0370 -0.0650 0.0680 -0.0550 ;
      RECT 0.1000 -0.0250 0.1310 -0.0150 ;
      RECT 0.0790 -0.0250 0.1100 -0.0150 ;
      RECT 0.0580 -0.0250 0.0890 -0.0150 ;
      RECT 0.0370 -0.0250 0.0680 -0.0150 ;
      RECT 0.0370 0.0350 0.0680 0.0450 ;
      RECT 0.0580 0.0150 0.0890 0.0250 ;
      RECT 0.0370 0.0150 0.0680 0.0250 ;
      RECT 0.0160 0.0150 0.0470 0.0250 ;
      RECT -0.0050 0.0150 0.0260 0.0250 ;
      RECT 0.0790 -0.0450 0.1520 -0.0350 ;
      RECT 0.1630 0.0150 0.1940 0.0250 ;
      RECT 0.1420 0.0150 0.1730 0.0250 ;
      RECT 0.1210 0.0150 0.1520 0.0250 ;
      RECT 0.0580 0.0550 0.0890 0.0650 ;
      RECT 0.0370 0.0550 0.0680 0.0650 ;
      RECT 0.0160 0.0550 0.0470 0.0650 ;
      RECT -0.0050 0.0550 0.0260 0.0650 ;
      RECT -0.0050 0.0350 0.0260 0.0450 ;
      RECT 0.0790 0.0350 0.1100 0.0450 ;
      RECT 0.0790 -0.1450 0.0890 -0.1350 ;
  END
END FA_X1

MACRO HA_X1
  CLASS CORE ;
  FOREIGN HA_X1 0 0 ;
  ORIGIN -0.0210 -0.1600 ;
  SIZE 0.1680 BY 0.2400 ;
  SITE FSFET ;
  SYMMETRY X Y ;
  PIN S
    DIRECTION OUTPUT ;
    USE SIGNAL ;
    PORT
      LAYER M1 ;
        RECT -0.0070 -0.1470 0.0070 -0.1330 ;
    END
  END S
  PIN CO
    DIRECTION OUTPUT ;
    USE SIGNAL ;
    PORT
      LAYER M1 ;
        RECT 0.0350 -0.0670 0.0490 -0.0330 ;
        RECT 0.0350 -0.0470 0.0490 -0.0130 ;
    END
  END CO
  PIN B
    DIRECTION INPUT ;
    USE SIGNAL ;
    PORT
      LAYER M1 ;
        RECT 0.0350 0.0330 0.0490 0.0470 ;
    END
  END B
  PIN A
    DIRECTION INPUT ;
    USE SIGNAL ;
    PORT
      LAYER M1 ;
        RECT 0.1190 0.0330 0.1330 0.0470 ;
    END
  END A
  PIN VSS
    DIRECTION INOUT ;
    USE GROUND ;
    PORT
      LAYER M0 ;
        RECT -0.0370 -0.1650 0.1630 -0.1550 ;
    END
  END VSS
  PIN VSS
    DIRECTION INOUT ;
    USE GROUND ;
    PORT
      LAYER M0 ;
        RECT -0.0370 -0.0050 0.1630 0.0050 ;
    END
  END VSS
  PIN VDD
    DIRECTION INOUT ;
    USE POWER ;
    PORT
      LAYER M0 ;
        RECT -0.0370 -0.0850 0.1630 -0.0750 ;
    END
  END VDD
  PIN VDD
    DIRECTION INOUT ;
    USE POWER ;
    PORT
      LAYER M0 ;
        RECT -0.0370 0.0750 0.1630 0.0850 ;
    END
  END VDD
  OBS
    LAYER M1 ;
      RECT 0.0770 0.0130 0.0910 0.0470 ;
      RECT 0.0770 0.0330 0.0910 0.0670 ;
      RECT -0.0070 -0.1070 0.0070 -0.0730 ;
      RECT -0.0070 -0.0870 0.0070 -0.0530 ;
      RECT -0.0070 -0.0670 0.0070 -0.0330 ;
      RECT -0.0070 -0.0470 0.0070 -0.0130 ;
      RECT -0.0070 -0.0270 0.0070 0.0070 ;
      RECT -0.0070 -0.0070 0.0070 0.0270 ;
      RECT 0.0770 -0.1470 0.0910 -0.1130 ;
      RECT 0.0770 -0.1270 0.0910 -0.0930 ;
      RECT 0.1190 -0.1270 0.1330 -0.0930 ;
      RECT 0.0350 -0.1270 0.0490 -0.0930 ;
      RECT 0.0770 -0.0670 0.0910 -0.0330 ;
      RECT 0.0770 -0.0470 0.0910 -0.0130 ;
    LAYER M0 ;
      RECT 0.0370 0.0350 0.0680 0.0450 ;
      RECT 0.0790 -0.1050 0.0890 -0.0950 ;
      RECT 0.1210 -0.1050 0.1310 -0.0950 ;
      RECT 0.0370 -0.1050 0.0470 -0.0950 ;
      RECT 0.0790 -0.0650 0.0890 -0.0550 ;
      RECT -0.0050 -0.1050 0.0260 -0.0950 ;
      RECT 0.0580 0.0150 0.0890 0.0250 ;
      RECT 0.0370 0.0150 0.0680 0.0250 ;
      RECT 0.0160 0.0150 0.0470 0.0250 ;
      RECT -0.0050 0.0150 0.0260 0.0250 ;
      RECT 0.1000 0.0550 0.1310 0.0650 ;
      RECT 0.0790 0.0550 0.1100 0.0650 ;
      RECT 0.1000 -0.1450 0.1310 -0.1350 ;
      RECT 0.0790 -0.1450 0.1100 -0.1350 ;
      RECT 0.0580 -0.1450 0.0890 -0.1350 ;
      RECT 0.0370 -0.1450 0.0680 -0.1350 ;
      RECT 0.0160 -0.1450 0.0470 -0.1350 ;
      RECT -0.0050 -0.1450 0.0260 -0.1350 ;
      RECT 0.1000 -0.1250 0.1310 -0.1150 ;
      RECT 0.0790 -0.1250 0.1100 -0.1150 ;
      RECT 0.0580 -0.1250 0.0890 -0.1150 ;
      RECT 0.0370 -0.1250 0.0680 -0.1150 ;
      RECT 0.0160 -0.0650 0.0470 -0.0550 ;
      RECT -0.0050 -0.0650 0.0260 -0.0550 ;
      RECT 0.0160 -0.0250 0.0470 -0.0150 ;
      RECT -0.0050 -0.0250 0.0260 -0.0150 ;
      RECT 0.0580 -0.0450 0.0890 -0.0350 ;
      RECT 0.0370 -0.0450 0.0680 -0.0350 ;
      RECT 0.0160 -0.0450 0.0470 -0.0350 ;
      RECT 0.1000 -0.0250 0.1310 -0.0150 ;
      RECT 0.0790 -0.0250 0.1100 -0.0150 ;
      RECT 0.1000 0.0350 0.1310 0.0450 ;
  END
END HA_X1

MACRO INV_X1
  CLASS CORE ;
  FOREIGN INV_X1 0 0 ;
  ORIGIN -0.0210 0.0000 ;
  SIZE 0.0840 BY 0.0800 ;
  SITE FSFET ;
  SYMMETRY X Y ;
  PIN ZN
    DIRECTION OUTPUT ;
    USE SIGNAL ;
    PORT
      LAYER M1 ;
        RECT 0.0350 0.0130 0.0490 0.0470 ;
        RECT 0.0350 0.0330 0.0490 0.0670 ;
    END
  END ZN
  PIN A
    DIRECTION INPUT ;
    USE SIGNAL ;
    PORT
      LAYER M1 ;
        RECT -0.0070 0.0330 0.0070 0.0470 ;
    END
  END A
  PIN VDD
    DIRECTION INOUT ;
    USE POWER ;
    PORT
      LAYER M0 ;
        RECT -0.0370 0.0750 0.0790 0.0850 ;
    END
  END VDD
  PIN VSS
    DIRECTION INOUT ;
    USE GROUND ;
    PORT
      LAYER M0 ;
        RECT -0.0370 -0.0050 0.0790 0.0050 ;
    END
  END VSS
  OBS
    LAYER M0 ;
      RECT -0.0120 0.0150 0.0540 0.0250 ;
      RECT -0.0120 0.0350 0.0540 0.0450 ;
      RECT -0.0120 0.0550 0.0540 0.0650 ;
      RECT 0.0370 0.0150 0.0470 0.0250 ;
      RECT 0.0370 0.0550 0.0470 0.0650 ;
  END
END INV_X1

MACRO INV_X16
  CLASS CORE ;
  FOREIGN INV_X16 0 0 ;
  ORIGIN -0.0210 0.0000 ;
  SIZE 0.7140 BY 0.0800 ;
  SITE FSFET ;
  SYMMETRY X Y ;
  PIN A
    DIRECTION INPUT ;
    USE SIGNAL ;
    PORT
      LAYER M1 ;
        RECT 0.2870 0.0330 0.3010 0.0470 ;
    END
  END A
  PIN ZN
    DIRECTION OUTPUT ;
    USE SIGNAL ;
    PORT
      LAYER M1 ;
        RECT 0.6650 0.0130 0.6790 0.0470 ;
        RECT 0.6650 0.0330 0.6790 0.0670 ;
        RECT 0.5810 0.0130 0.5950 0.0470 ;
        RECT 0.5810 0.0330 0.5950 0.0670 ;
        RECT 0.4970 0.0130 0.5110 0.0470 ;
        RECT 0.4970 0.0330 0.5110 0.0670 ;
        RECT 0.4130 0.0130 0.4270 0.0470 ;
        RECT 0.4130 0.0330 0.4270 0.0670 ;
        RECT 0.3290 0.0130 0.3430 0.0470 ;
        RECT 0.3290 0.0330 0.3430 0.0670 ;
        RECT 0.2450 0.0130 0.2590 0.0470 ;
        RECT 0.2450 0.0330 0.2590 0.0670 ;
        RECT 0.1610 0.0130 0.1750 0.0470 ;
        RECT 0.1610 0.0330 0.1750 0.0670 ;
        RECT 0.0770 0.0130 0.0910 0.0470 ;
        RECT 0.0770 0.0330 0.0910 0.0670 ;
        RECT -0.0070 0.0130 0.0070 0.0470 ;
        RECT -0.0070 0.0330 0.0070 0.0670 ;
    END
  END ZN
  PIN VSS
    DIRECTION INOUT ;
    USE GROUND ;
    PORT
      LAYER M0 ;
        RECT -0.0370 -0.0050 0.7090 0.0050 ;
    END
  END VSS
  PIN VDD
    DIRECTION INOUT ;
    USE POWER ;
    PORT
      LAYER M0 ;
        RECT -0.0370 0.0750 0.7090 0.0850 ;
    END
  END VDD
  OBS
    LAYER M0 ;
      RECT 0.6670 0.0150 0.6770 0.0250 ;
      RECT -0.0050 0.0550 0.0050 0.0650 ;
      RECT 0.6250 0.0350 0.6560 0.0450 ;
      RECT 0.6040 0.0350 0.6350 0.0450 ;
      RECT 0.5830 0.0350 0.6140 0.0450 ;
      RECT 0.5620 0.0350 0.5930 0.0450 ;
      RECT 0.5410 0.0350 0.5720 0.0450 ;
      RECT 0.5200 0.0350 0.5510 0.0450 ;
      RECT 0.4990 0.0350 0.5300 0.0450 ;
      RECT 0.4780 0.0350 0.5090 0.0450 ;
      RECT 0.4570 0.0350 0.4880 0.0450 ;
      RECT 0.4360 0.0350 0.4670 0.0450 ;
      RECT 0.4150 0.0350 0.4460 0.0450 ;
      RECT 0.3940 0.0350 0.4250 0.0450 ;
      RECT 0.3730 0.0350 0.4040 0.0450 ;
      RECT 0.3520 0.0350 0.3830 0.0450 ;
      RECT 0.3310 0.0350 0.3620 0.0450 ;
      RECT 0.3100 0.0350 0.3410 0.0450 ;
      RECT 0.2890 0.0350 0.3200 0.0450 ;
      RECT 0.2680 0.0350 0.2990 0.0450 ;
      RECT 0.2470 0.0350 0.2780 0.0450 ;
      RECT 0.2260 0.0350 0.2570 0.0450 ;
      RECT 0.2050 0.0350 0.2360 0.0450 ;
      RECT 0.1840 0.0350 0.2150 0.0450 ;
      RECT 0.1630 0.0350 0.1940 0.0450 ;
      RECT 0.1420 0.0350 0.1730 0.0450 ;
      RECT 0.1210 0.0350 0.1520 0.0450 ;
      RECT 0.1000 0.0350 0.1310 0.0450 ;
      RECT 0.0790 0.0350 0.1100 0.0450 ;
      RECT 0.0580 0.0350 0.0890 0.0450 ;
      RECT 0.0370 0.0350 0.0680 0.0450 ;
      RECT -0.0060 0.0350 0.0470 0.0450 ;
      RECT 0.5620 0.0150 0.5930 0.0250 ;
      RECT 0.5410 0.0150 0.5720 0.0250 ;
      RECT 0.5200 0.0150 0.5510 0.0250 ;
      RECT 0.4990 0.0150 0.5300 0.0250 ;
      RECT 0.3940 0.0150 0.4250 0.0250 ;
      RECT 0.3730 0.0150 0.4040 0.0250 ;
      RECT 0.3520 0.0150 0.3830 0.0250 ;
      RECT 0.3310 0.0150 0.3620 0.0250 ;
      RECT 0.2260 0.0150 0.2570 0.0250 ;
      RECT 0.2050 0.0150 0.2360 0.0250 ;
      RECT 0.1840 0.0150 0.2150 0.0250 ;
      RECT 0.1630 0.0150 0.1940 0.0250 ;
      RECT 0.0580 0.0150 0.0890 0.0250 ;
      RECT 0.0370 0.0150 0.0680 0.0250 ;
      RECT 0.0160 0.0150 0.0470 0.0250 ;
      RECT -0.0050 0.0150 0.0260 0.0250 ;
      RECT 0.6460 0.0550 0.6770 0.0650 ;
      RECT 0.6250 0.0550 0.6560 0.0650 ;
      RECT 0.6040 0.0550 0.6350 0.0650 ;
      RECT 0.5830 0.0550 0.6140 0.0650 ;
      RECT 0.4780 0.0550 0.5090 0.0650 ;
      RECT 0.4570 0.0550 0.4880 0.0650 ;
      RECT 0.4360 0.0550 0.4670 0.0650 ;
      RECT 0.4150 0.0550 0.4460 0.0650 ;
      RECT 0.3100 0.0550 0.3410 0.0650 ;
      RECT 0.2890 0.0550 0.3200 0.0650 ;
      RECT 0.2680 0.0550 0.2990 0.0650 ;
      RECT 0.2470 0.0550 0.2780 0.0650 ;
      RECT 0.1420 0.0550 0.1730 0.0650 ;
      RECT 0.1210 0.0550 0.1520 0.0650 ;
      RECT 0.1000 0.0550 0.1310 0.0650 ;
      RECT 0.0790 0.0550 0.1100 0.0650 ;
  END
END INV_X16

MACRO INV_X2
  CLASS CORE ;
  FOREIGN INV_X2 0 0 ;
  ORIGIN -0.0210 0.0000 ;
  SIZE 0.1260 BY 0.0800 ;
  SITE FSFET ;
  SYMMETRY X Y ;
  PIN ZN
    DIRECTION OUTPUT ;
    USE SIGNAL ;
    PORT
      LAYER M1 ;
        RECT 0.0350 0.0130 0.0490 0.0470 ;
        RECT 0.0350 0.0330 0.0490 0.0670 ;
    END
  END ZN
  PIN A
    DIRECTION INPUT ;
    USE SIGNAL ;
    PORT
      LAYER M1 ;
        RECT -0.0070 0.0330 0.0070 0.0470 ;
    END
  END A
  PIN VDD
    DIRECTION INOUT ;
    USE POWER ;
    PORT
      LAYER M0 ;
        RECT -0.0370 0.0750 0.1210 0.0850 ;
    END
  END VDD
  PIN VSS
    DIRECTION INOUT ;
    USE GROUND ;
    PORT
      LAYER M0 ;
        RECT -0.0370 -0.0050 0.1210 0.0050 ;
    END
  END VSS
  OBS
    LAYER M0 ;
      RECT 0.0370 0.0150 0.0470 0.0250 ;
      RECT 0.0370 0.0550 0.0470 0.0650 ;
      RECT 0.0370 0.0350 0.0680 0.0450 ;
      RECT -0.0050 0.0350 0.0470 0.0450 ;
  END
END INV_X2

MACRO INV_X32
  CLASS CORE ;
  FOREIGN INV_X32 0 0 ;
  ORIGIN 0.2410 0.0150 ;
  SIZE 1.3860 BY 0.0800 ;
  SITE FSFET ;
  SYMMETRY X Y ;
  PIN ZN
    DIRECTION OUTPUT ;
    USE SIGNAL ;
    PORT
      LAYER M1 ;
        RECT 0.9270 0.0480 0.9410 0.0820 ;
        RECT 0.9270 0.0280 0.9410 0.0620 ;
        RECT 1.0110 0.0480 1.0250 0.0820 ;
        RECT 1.0110 0.0280 1.0250 0.0620 ;
        RECT 1.0950 0.0480 1.1090 0.0820 ;
        RECT 1.0950 0.0280 1.1090 0.0620 ;
        RECT 1.1790 0.0480 1.1930 0.0820 ;
        RECT 1.1790 0.0280 1.1930 0.0620 ;
        RECT 1.2630 0.0480 1.2770 0.0820 ;
        RECT 1.2630 0.0280 1.2770 0.0620 ;
        RECT 1.3470 0.0480 1.3610 0.0820 ;
        RECT 1.3470 0.0280 1.3610 0.0620 ;
        RECT 1.4310 0.0480 1.4450 0.0820 ;
        RECT 1.4310 0.0280 1.4450 0.0620 ;
        RECT 1.5150 0.0480 1.5290 0.0820 ;
        RECT 1.5150 0.0280 1.5290 0.0620 ;
        RECT 1.5990 0.0480 1.6130 0.0820 ;
        RECT 1.5990 0.0280 1.6130 0.0620 ;
        RECT 0.6750 0.0280 0.6890 0.0620 ;
        RECT 0.7590 0.0480 0.7730 0.0820 ;
        RECT 0.7590 0.0280 0.7730 0.0620 ;
        RECT 0.8430 0.0480 0.8570 0.0820 ;
        RECT 0.8430 0.0280 0.8570 0.0620 ;
        RECT 0.9270 0.0480 0.9410 0.0820 ;
        RECT 0.9270 0.0280 0.9410 0.0620 ;
        RECT 0.2550 0.0480 0.2690 0.0820 ;
        RECT 0.2550 0.0280 0.2690 0.0620 ;
        RECT 0.3390 0.0480 0.3530 0.0820 ;
        RECT 0.3390 0.0280 0.3530 0.0620 ;
        RECT 0.4230 0.0480 0.4370 0.0820 ;
        RECT 0.4230 0.0280 0.4370 0.0620 ;
        RECT 0.5070 0.0480 0.5210 0.0820 ;
        RECT 0.5070 0.0280 0.5210 0.0620 ;
        RECT 0.5910 0.0480 0.6050 0.0820 ;
        RECT 0.5910 0.0280 0.6050 0.0620 ;
        RECT 0.6750 0.0480 0.6890 0.0820 ;
    END
  END ZN
  PIN A
    DIRECTION INPUT ;
    USE SIGNAL ;
    PORT
      LAYER M1 ;
        RECT 0.2970 0.0480 0.3110 0.0620 ;
    END
  END A
  PIN VSS
    DIRECTION INOUT ;
    USE GROUND ;
    PORT
      LAYER M0 ;
        RECT 0.8970 0.0100 1.6430 0.0200 ;
    END
  END VSS
  PIN VDD
    DIRECTION INOUT ;
    USE POWER ;
    PORT
      LAYER M0 ;
        RECT 0.8970 0.0900 1.6430 0.1000 ;
    END
  END VDD
  OBS
    LAYER M0 ;
      RECT 1.1600 0.0300 1.1910 0.0400 ;
      RECT 1.2650 0.0300 1.2960 0.0400 ;
      RECT 1.0340 0.0700 1.0650 0.0800 ;
      RECT 0.9290 0.0700 0.9390 0.0800 ;
      RECT 1.0550 0.0700 1.0860 0.0800 ;
      RECT 1.0760 0.0700 1.1070 0.0800 ;
      RECT 1.1810 0.0700 1.2120 0.0800 ;
      RECT 1.2020 0.0700 1.2330 0.0800 ;
      RECT 1.2230 0.0700 1.2540 0.0800 ;
      RECT 1.2440 0.0700 1.2750 0.0800 ;
      RECT 1.3490 0.0700 1.3800 0.0800 ;
      RECT 1.3700 0.0700 1.4010 0.0800 ;
      RECT 1.3910 0.0700 1.4220 0.0800 ;
      RECT 1.4120 0.0700 1.4430 0.0800 ;
      RECT 1.5170 0.0700 1.5480 0.0800 ;
      RECT 1.5380 0.0700 1.5690 0.0800 ;
      RECT 1.5590 0.0700 1.5900 0.0800 ;
      RECT 1.5800 0.0700 1.6110 0.0800 ;
      RECT 0.9290 0.0300 0.9600 0.0400 ;
      RECT 0.9500 0.0300 0.9810 0.0400 ;
      RECT 0.9710 0.0300 1.0020 0.0400 ;
      RECT 0.9920 0.0300 1.0230 0.0400 ;
      RECT 1.0970 0.0300 1.1280 0.0400 ;
      RECT 1.1180 0.0300 1.1490 0.0400 ;
      RECT 1.1390 0.0300 1.1700 0.0400 ;
      RECT 1.6010 0.0300 1.6110 0.0400 ;
      RECT 1.0130 0.0700 1.0440 0.0800 ;
      RECT 0.9160 0.0500 0.9810 0.0600 ;
      RECT 0.9710 0.0500 1.0020 0.0600 ;
      RECT 0.9920 0.0500 1.0230 0.0600 ;
      RECT 1.0130 0.0500 1.0440 0.0600 ;
      RECT 1.0340 0.0500 1.0650 0.0600 ;
      RECT 1.0550 0.0500 1.0860 0.0600 ;
      RECT 1.0760 0.0500 1.1070 0.0600 ;
      RECT 1.0970 0.0500 1.1280 0.0600 ;
      RECT 1.1180 0.0500 1.1490 0.0600 ;
      RECT 1.1390 0.0500 1.1700 0.0600 ;
      RECT 1.1600 0.0500 1.1910 0.0600 ;
      RECT 1.1810 0.0500 1.2120 0.0600 ;
      RECT 1.2020 0.0500 1.2330 0.0600 ;
      RECT 1.2230 0.0500 1.2540 0.0600 ;
      RECT 1.2440 0.0500 1.2750 0.0600 ;
      RECT 1.2650 0.0500 1.2960 0.0600 ;
      RECT 1.2860 0.0500 1.3170 0.0600 ;
      RECT 1.3070 0.0500 1.3380 0.0600 ;
      RECT 1.3280 0.0500 1.3590 0.0600 ;
      RECT 1.3490 0.0500 1.3800 0.0600 ;
      RECT 1.3700 0.0500 1.4010 0.0600 ;
      RECT 1.3910 0.0500 1.4220 0.0600 ;
      RECT 1.4120 0.0500 1.4430 0.0600 ;
      RECT 1.4330 0.0500 1.4640 0.0600 ;
      RECT 1.4540 0.0500 1.4850 0.0600 ;
      RECT 1.4750 0.0500 1.5060 0.0600 ;
      RECT 1.4960 0.0500 1.5270 0.0600 ;
      RECT 1.5170 0.0500 1.5480 0.0600 ;
      RECT 1.5380 0.0500 1.5690 0.0600 ;
      RECT 1.5590 0.0500 1.5900 0.0600 ;
      RECT 0.2250 0.0900 0.9710 0.1000 ;
      RECT 0.2250 0.0100 0.9710 0.0200 ;
      RECT 0.3410 0.0700 0.3720 0.0800 ;
      RECT 0.2780 0.0500 0.3090 0.0600 ;
      RECT 0.2990 0.0500 0.3300 0.0600 ;
      RECT 0.3200 0.0500 0.3510 0.0600 ;
      RECT 0.3410 0.0500 0.3720 0.0600 ;
      RECT 0.3620 0.0500 0.3930 0.0600 ;
      RECT 0.3830 0.0500 0.4140 0.0600 ;
      RECT 0.4040 0.0500 0.4350 0.0600 ;
      RECT 0.4250 0.0500 0.4560 0.0600 ;
      RECT 0.4460 0.0500 0.4770 0.0600 ;
      RECT 0.5720 0.0500 0.6030 0.0600 ;
      RECT 0.5930 0.0500 0.6240 0.0600 ;
      RECT 0.6140 0.0500 0.6450 0.0600 ;
      RECT 0.6350 0.0500 0.6660 0.0600 ;
      RECT 0.9290 0.0300 0.9390 0.0400 ;
      RECT 0.8240 0.0300 0.8550 0.0400 ;
      RECT 0.8030 0.0300 0.8340 0.0400 ;
      RECT 0.6560 0.0500 0.6870 0.0600 ;
      RECT 0.6770 0.0500 0.7080 0.0600 ;
      RECT 0.6980 0.0500 0.7290 0.0600 ;
      RECT 0.7190 0.0500 0.7500 0.0600 ;
      RECT 0.7820 0.0300 0.8130 0.0400 ;
      RECT 0.7610 0.0300 0.7920 0.0400 ;
      RECT 0.6560 0.0300 0.6870 0.0400 ;
      RECT 0.6350 0.0300 0.6660 0.0400 ;
      RECT 0.6140 0.0300 0.6450 0.0400 ;
      RECT 0.7400 0.0500 0.7710 0.0600 ;
      RECT 0.7610 0.0500 0.7920 0.0600 ;
      RECT 0.7820 0.0500 0.8130 0.0600 ;
      RECT 0.8030 0.0500 0.8340 0.0600 ;
      RECT 0.4670 0.0500 0.4980 0.0600 ;
      RECT 0.5930 0.0300 0.6240 0.0400 ;
      RECT 0.4880 0.0300 0.5190 0.0400 ;
      RECT 0.4670 0.0300 0.4980 0.0400 ;
      RECT 0.4460 0.0300 0.4770 0.0400 ;
      RECT 0.4250 0.0300 0.4560 0.0400 ;
      RECT 0.8240 0.0500 0.8550 0.0600 ;
      RECT 0.8450 0.0500 0.8760 0.0600 ;
      RECT 0.2570 0.0700 0.2670 0.0800 ;
      RECT 0.3200 0.0300 0.3510 0.0400 ;
      RECT 0.2990 0.0300 0.3300 0.0400 ;
      RECT 0.8660 0.0500 0.8970 0.0600 ;
      RECT 0.8870 0.0500 0.9180 0.0600 ;
      RECT 0.5510 0.0500 0.5820 0.0600 ;
      RECT 0.2780 0.0300 0.3090 0.0400 ;
      RECT 0.2570 0.0300 0.2880 0.0400 ;
      RECT 0.9080 0.0700 0.9390 0.0800 ;
      RECT 0.8870 0.0700 0.9180 0.0800 ;
      RECT 0.8660 0.0700 0.8970 0.0800 ;
      RECT 0.8450 0.0700 0.8760 0.0800 ;
      RECT 0.7400 0.0700 0.7710 0.0800 ;
      RECT 0.7190 0.0700 0.7500 0.0800 ;
      RECT 0.6980 0.0700 0.7290 0.0800 ;
      RECT 0.6770 0.0700 0.7080 0.0800 ;
      RECT 0.5720 0.0700 0.6030 0.0800 ;
      RECT 0.5510 0.0700 0.5820 0.0800 ;
      RECT 0.5300 0.0700 0.5610 0.0800 ;
      RECT 0.5090 0.0700 0.5400 0.0800 ;
      RECT 0.4040 0.0700 0.4350 0.0800 ;
      RECT 0.3830 0.0700 0.4140 0.0800 ;
      RECT 0.3620 0.0700 0.3930 0.0800 ;
      RECT 0.4880 0.0500 0.5190 0.0600 ;
      RECT 0.5090 0.0500 0.5400 0.0600 ;
      RECT 0.5300 0.0500 0.5610 0.0600 ;
      RECT 1.2860 0.0300 1.3170 0.0400 ;
      RECT 1.3070 0.0300 1.3380 0.0400 ;
      RECT 1.3280 0.0300 1.3590 0.0400 ;
      RECT 1.4330 0.0300 1.4640 0.0400 ;
      RECT 1.4540 0.0300 1.4850 0.0400 ;
      RECT 1.4750 0.0300 1.5060 0.0400 ;
      RECT 1.4960 0.0300 1.5270 0.0400 ;
  END
END INV_X32

MACRO INV_X4
  CLASS CORE ;
  FOREIGN INV_X4 0 0 ;
  ORIGIN -0.0210 0.0000 ;
  SIZE 0.2100 BY 0.0800 ;
  SITE FSFET ;
  SYMMETRY X Y ;
  PIN A
    DIRECTION INPUT ;
    USE SIGNAL ;
    PORT
      LAYER M1 ;
        RECT -0.0070 0.0330 0.0070 0.0470 ;
    END
  END A
  PIN ZN
    DIRECTION OUTPUT ;
    USE SIGNAL ;
    PORT
      LAYER M1 ;
        RECT 0.1190 0.0130 0.1330 0.0470 ;
        RECT 0.1190 0.0330 0.1330 0.0670 ;
        RECT 0.0350 0.0130 0.0490 0.0470 ;
        RECT 0.0350 0.0330 0.0490 0.0670 ;
    END
  END ZN
  PIN VDD
    DIRECTION INOUT ;
    USE POWER ;
    PORT
      LAYER M0 ;
        RECT -0.0370 0.0750 0.2050 0.0850 ;
    END
  END VDD
  PIN VSS
    DIRECTION INOUT ;
    USE GROUND ;
    PORT
      LAYER M0 ;
        RECT -0.0370 -0.0050 0.2050 0.0050 ;
    END
  END VSS
  OBS
    LAYER M0 ;
      RECT 0.1210 0.0150 0.1310 0.0250 ;
      RECT 0.0370 0.0150 0.0470 0.0250 ;
      RECT 0.1210 0.0350 0.1520 0.0450 ;
      RECT 0.1000 0.0350 0.1310 0.0450 ;
      RECT 0.0790 0.0350 0.1100 0.0450 ;
      RECT 0.0580 0.0350 0.0890 0.0450 ;
      RECT 0.0370 0.0350 0.0680 0.0450 ;
      RECT -0.0060 0.0350 0.0470 0.0450 ;
      RECT 0.1000 0.0550 0.1310 0.0650 ;
      RECT 0.0790 0.0550 0.1100 0.0650 ;
      RECT 0.0580 0.0550 0.0890 0.0650 ;
      RECT 0.0370 0.0550 0.0680 0.0650 ;
  END
END INV_X4

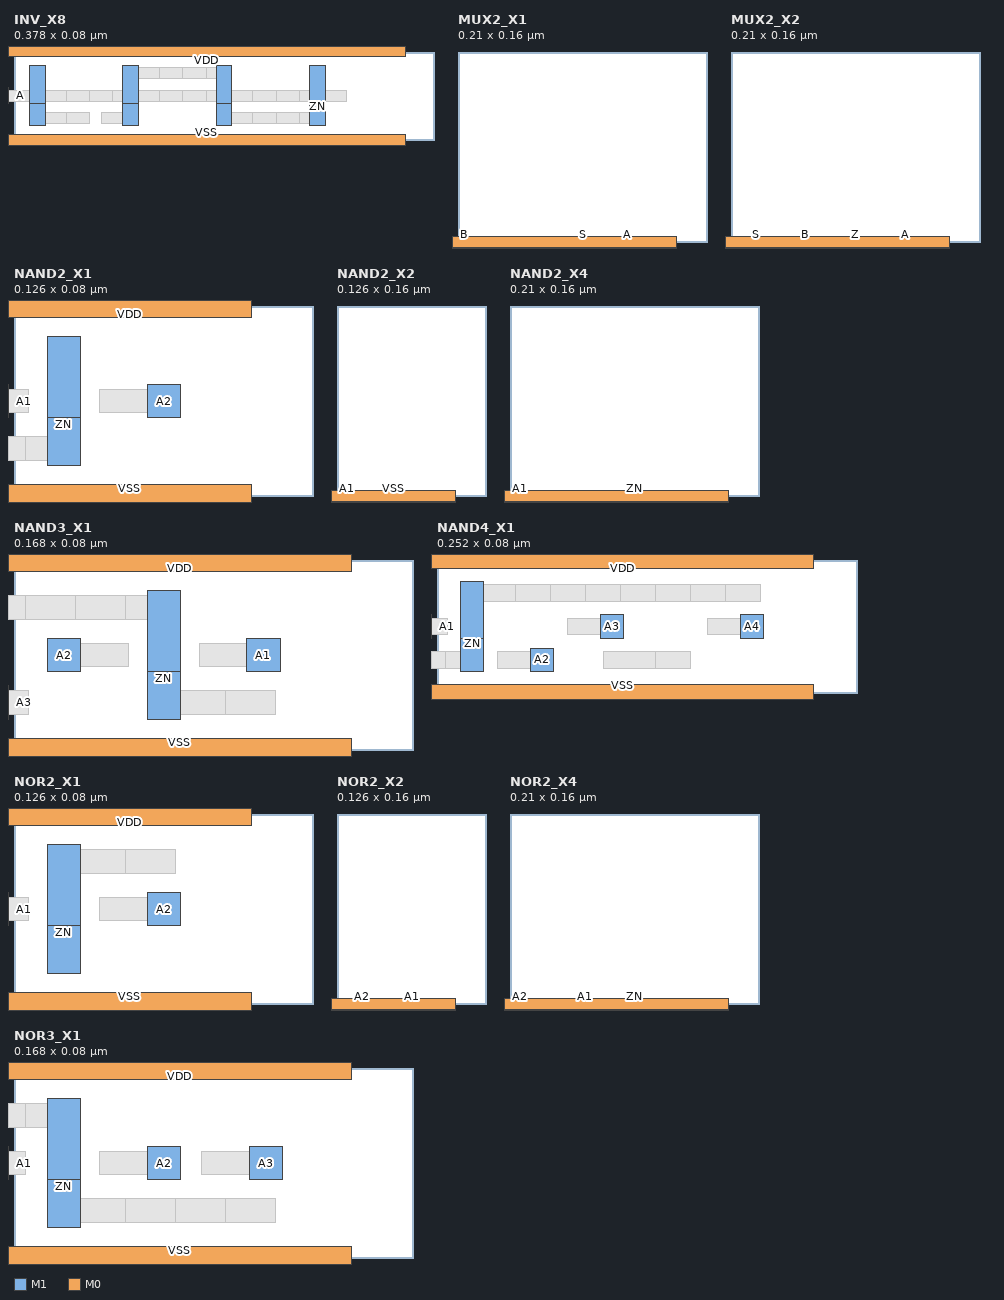
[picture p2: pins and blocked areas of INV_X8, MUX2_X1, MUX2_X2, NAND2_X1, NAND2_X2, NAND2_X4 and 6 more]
MACRO INV_X8
  CLASS CORE ;
  FOREIGN INV_X8 0 0 ;
  ORIGIN -0.0210 0.0000 ;
  SIZE 0.3780 BY 0.0800 ;
  SITE FSFET ;
  SYMMETRY X Y ;
  PIN A
    DIRECTION INPUT ;
    USE SIGNAL ;
    PORT
      LAYER M1 ;
        RECT -0.0070 0.0330 0.0070 0.0470 ;
    END
  END A
  PIN ZN
    DIRECTION OUTPUT ;
    USE SIGNAL ;
    PORT
      LAYER M1 ;
        RECT 0.2870 0.0130 0.3010 0.0470 ;
        RECT 0.2870 0.0330 0.3010 0.0670 ;
        RECT 0.2030 0.0130 0.2170 0.0470 ;
        RECT 0.2030 0.0330 0.2170 0.0670 ;
        RECT 0.1190 0.0130 0.1330 0.0470 ;
        RECT 0.1190 0.0330 0.1330 0.0670 ;
        RECT 0.0350 0.0130 0.0490 0.0470 ;
        RECT 0.0350 0.0330 0.0490 0.0670 ;
    END
  END ZN
  PIN VSS
    DIRECTION INOUT ;
    USE GROUND ;
    PORT
      LAYER M0 ;
        RECT -0.0370 -0.0050 0.3730 0.0050 ;
    END
  END VSS
  PIN VDD
    DIRECTION INOUT ;
    USE POWER ;
    PORT
      LAYER M0 ;
        RECT -0.0370 0.0750 0.3730 0.0850 ;
    END
  END VDD
  OBS
    LAYER M0 ;
      RECT 0.2890 0.0550 0.2990 0.0650 ;
      RECT 0.0370 0.0550 0.0470 0.0650 ;
      RECT 0.2890 0.0350 0.3200 0.0450 ;
      RECT 0.2680 0.0350 0.2990 0.0450 ;
      RECT 0.2470 0.0350 0.2780 0.0450 ;
      RECT 0.2260 0.0350 0.2570 0.0450 ;
      RECT 0.2050 0.0350 0.2360 0.0450 ;
      RECT 0.1840 0.0350 0.2150 0.0450 ;
      RECT 0.1630 0.0350 0.1940 0.0450 ;
      RECT 0.1420 0.0350 0.1730 0.0450 ;
      RECT 0.1210 0.0350 0.1520 0.0450 ;
      RECT 0.1000 0.0350 0.1310 0.0450 ;
      RECT 0.0790 0.0350 0.1100 0.0450 ;
      RECT 0.0580 0.0350 0.0890 0.0450 ;
      RECT 0.0370 0.0350 0.0680 0.0450 ;
      RECT -0.0050 0.0350 0.0470 0.0450 ;
      RECT 0.2680 0.0150 0.2990 0.0250 ;
      RECT 0.2470 0.0150 0.2780 0.0250 ;
      RECT 0.2260 0.0150 0.2570 0.0250 ;
      RECT 0.2050 0.0150 0.2360 0.0250 ;
      RECT 0.1000 0.0150 0.1310 0.0250 ;
      RECT 0.0580 0.0150 0.0890 0.0250 ;
      RECT 0.0370 0.0150 0.0680 0.0250 ;
      RECT 0.1840 0.0550 0.2150 0.0650 ;
      RECT 0.1630 0.0550 0.1940 0.0650 ;
      RECT 0.1420 0.0550 0.1730 0.0650 ;
      RECT 0.1210 0.0550 0.1520 0.0650 ;
  END
END INV_X8

MACRO MUX2_X1
  CLASS CORE ;
  FOREIGN MUX2_X1 0 0 ;
  ORIGIN -0.0210 -0.0800 ;
  SIZE 0.2100 BY 0.1600 ;
  SITE FSFET ;
  SYMMETRY X Y ;
  PIN B
    DIRECTION INPUT ;
    USE SIGNAL ;
    PORT
      LAYER M1 ;
        RECT -0.0010 -0.0470 0.0130 -0.0330 ;
    END
  END B
  PIN A
    DIRECTION INPUT ;
    USE SIGNAL ;
    PORT
      LAYER M1 ;
        RECT 0.1570 0.0330 0.1710 0.0470 ;
    END
  END A
  PIN S
    DIRECTION INPUT ;
    USE SIGNAL ;
    PORT
      LAYER M1 ;
        RECT 0.1190 0.0330 0.1330 0.0670 ;
        RECT -0.0070 -0.0270 0.0070 0.0070 ;
        RECT -0.0070 -0.0070 0.0070 0.0270 ;
    END
  END S
  PIN Z
    DIRECTION OUTPUT ;
    USE SIGNAL ;
    PORT
      LAYER M1 ;
        RECT 0.1610 -0.0670 0.1750 -0.0330 ;
        RECT 0.1610 -0.0470 0.1750 -0.0130 ;
    END
  END Z
  PIN VDD
    DIRECTION INOUT ;
    USE POWER ;
    PORT
      LAYER M0 ;
        RECT -0.0370 -0.0850 0.2050 -0.0750 ;
    END
  END VDD
  PIN VSS
    DIRECTION INOUT ;
    USE GROUND ;
    PORT
      LAYER M0 ;
        RECT -0.0370 -0.0050 0.2050 0.0050 ;
    END
  END VSS
  PIN VDD
    DIRECTION INOUT ;
    USE POWER ;
    PORT
      LAYER M0 ;
        RECT -0.0370 0.0750 0.2050 0.0850 ;
    END
  END VDD
  OBS
    LAYER M1 ;
      RECT 0.1190 -0.0470 0.1330 -0.0130 ;
      RECT 0.1190 -0.0270 0.1330 0.0070 ;
      RECT 0.1190 -0.0070 0.1330 0.0270 ;
      RECT 0.0350 -0.0670 0.0490 -0.0330 ;
      RECT 0.0350 -0.0470 0.0490 -0.0130 ;
      RECT 0.0350 -0.0270 0.0490 0.0070 ;
      RECT 0.0350 -0.0070 0.0490 0.0270 ;
      RECT 0.0350 0.0130 0.0490 0.0470 ;
      RECT 0.0350 0.0330 0.0490 0.0670 ;
      RECT 0.0770 -0.0670 0.0910 -0.0330 ;
      RECT 0.0770 -0.0470 0.0910 -0.0130 ;
      RECT 0.0770 -0.0270 0.0910 0.0070 ;
      RECT 0.0770 -0.0070 0.0910 0.0270 ;
      RECT 0.0770 0.0130 0.0910 0.0470 ;
      RECT 0.0770 0.0330 0.0910 0.0670 ;
    LAYER M0 ;
      RECT -0.0010 -0.0450 0.0260 -0.0350 ;
      RECT 0.1420 0.0350 0.1690 0.0450 ;
      RECT 0.1630 -0.0650 0.1730 -0.0550 ;
      RECT 0.1630 -0.0250 0.1730 -0.0150 ;
      RECT 0.0370 0.0150 0.0470 0.0250 ;
      RECT 0.0370 0.0550 0.0470 0.0650 ;
      RECT 0.0790 -0.0250 0.0890 -0.0150 ;
      RECT 0.0790 0.0150 0.0890 0.0250 ;
      RECT 0.0790 0.0550 0.0890 0.0650 ;
      RECT 0.0370 -0.0250 0.0680 -0.0150 ;
      RECT 0.0160 -0.0250 0.0470 -0.0150 ;
      RECT -0.0050 -0.0250 0.0260 -0.0150 ;
      RECT -0.0050 0.0150 0.0260 0.0250 ;
      RECT 0.1000 0.0350 0.1310 0.0450 ;
      RECT 0.0790 0.0350 0.1100 0.0450 ;
      RECT 0.0580 0.0350 0.0890 0.0450 ;
      RECT 0.0370 0.0350 0.0680 0.0450 ;
      RECT 0.0160 0.0350 0.0470 0.0450 ;
      RECT 0.1000 0.0550 0.1310 0.0650 ;
      RECT 0.0370 -0.0650 0.0680 -0.0550 ;
      RECT 0.1000 -0.0450 0.1310 -0.0350 ;
      RECT 0.0790 -0.0450 0.1100 -0.0350 ;
      RECT 0.0580 -0.0450 0.0890 -0.0350 ;
      RECT 0.0370 -0.0450 0.0680 -0.0350 ;
      RECT 0.1000 0.0150 0.1310 0.0250 ;
      RECT 0.1210 -0.0650 0.1520 -0.0550 ;
      RECT 0.1000 -0.0650 0.1310 -0.0550 ;
      RECT 0.0790 -0.0650 0.1100 -0.0550 ;
  END
END MUX2_X1

MACRO MUX2_X2
  CLASS CORE ;
  FOREIGN MUX2_X2 0 0 ;
  ORIGIN -0.0210 -0.0800 ;
  SIZE 0.2100 BY 0.1600 ;
  SITE FSFET ;
  SYMMETRY X Y ;
  PIN A
    DIRECTION INPUT ;
    USE SIGNAL ;
    PORT
      LAYER M1 ;
        RECT 0.1610 0.0330 0.1750 0.0470 ;
    END
  END A
  PIN B
    DIRECTION INPUT ;
    USE SIGNAL ;
    PORT
      LAYER M1 ;
        RECT 0.0770 -0.0670 0.0910 -0.0530 ;
    END
  END B
  PIN Z
    DIRECTION OUTPUT ;
    USE SIGNAL ;
    PORT
      LAYER M1 ;
        RECT 0.1190 -0.0670 0.1330 -0.0330 ;
        RECT 0.1190 -0.0470 0.1330 -0.0130 ;
    END
  END Z
  PIN S
    DIRECTION INPUT ;
    USE SIGNAL ;
    PORT
      LAYER M1 ;
        RECT 0.0350 -0.0670 0.0490 -0.0530 ;
    END
  END S
  PIN VSS
    DIRECTION INOUT ;
    USE GROUND ;
    PORT
      LAYER M0 ;
        RECT -0.0370 -0.0050 0.2050 0.0050 ;
    END
  END VSS
  PIN VDD
    DIRECTION INOUT ;
    USE POWER ;
    PORT
      LAYER M0 ;
        RECT -0.0370 -0.0850 0.2050 -0.0750 ;
    END
  END VDD
  PIN VDD
    DIRECTION INOUT ;
    USE POWER ;
    PORT
      LAYER M0 ;
        RECT -0.0370 0.0750 0.2050 0.0850 ;
    END
  END VDD
  OBS
    LAYER M1 ;
      RECT 0.0770 -0.0470 0.0910 -0.0130 ;
      RECT 0.0770 -0.0270 0.0910 0.0070 ;
      RECT 0.0770 -0.0070 0.0910 0.0270 ;
      RECT -0.0070 -0.0670 0.0070 -0.0330 ;
      RECT -0.0070 -0.0470 0.0070 -0.0130 ;
      RECT 0.1610 -0.0470 0.1750 -0.0130 ;
      RECT 0.1610 -0.0270 0.1750 0.0070 ;
      RECT 0.1610 -0.0070 0.1750 0.0270 ;
      RECT 0.0350 -0.0270 0.0490 0.0070 ;
      RECT 0.0350 -0.0070 0.0490 0.0270 ;
      RECT 0.0350 0.0130 0.0490 0.0470 ;
      RECT 0.0350 0.0330 0.0490 0.0670 ;
      RECT 0.0770 0.0330 0.0910 0.0670 ;
      RECT -0.0070 0.0330 0.0070 0.0670 ;
    LAYER M0 ;
      RECT 0.1420 0.0350 0.1730 0.0450 ;
      RECT 0.0580 -0.0650 0.0890 -0.0550 ;
      RECT 0.0160 -0.0650 0.0470 -0.0550 ;
      RECT 0.1210 -0.0650 0.1310 -0.0550 ;
      RECT 0.1210 -0.0250 0.1310 -0.0150 ;
      RECT -0.0050 -0.0650 0.0050 -0.0550 ;
      RECT -0.0050 -0.0250 0.0050 -0.0150 ;
      RECT 0.1630 0.0150 0.1730 0.0250 ;
      RECT 0.0370 0.0550 0.0470 0.0650 ;
      RECT -0.0050 0.0550 0.0050 0.0650 ;
      RECT 0.0580 -0.0450 0.0890 -0.0350 ;
      RECT 0.0370 -0.0450 0.0680 -0.0350 ;
      RECT 0.0160 -0.0450 0.0470 -0.0350 ;
      RECT -0.0050 -0.0450 0.0260 -0.0350 ;
      RECT 0.0790 0.0150 0.1100 0.0250 ;
      RECT 0.1420 -0.0450 0.1730 -0.0350 ;
      RECT 0.1210 -0.0450 0.1520 -0.0350 ;
      RECT 0.1000 -0.0450 0.1310 -0.0350 ;
      RECT 0.0790 -0.0250 0.1100 -0.0150 ;
      RECT 0.0580 -0.0250 0.0890 -0.0150 ;
      RECT 0.0370 -0.0250 0.0680 -0.0150 ;
      RECT 0.0160 0.0150 0.0470 0.0250 ;
      RECT -0.0050 0.0150 0.0260 0.0250 ;
      RECT 0.0580 0.0350 0.0890 0.0450 ;
      RECT 0.0370 0.0350 0.0680 0.0450 ;
      RECT 0.0160 0.0350 0.0470 0.0450 ;
      RECT -0.0050 0.0350 0.0260 0.0450 ;
      RECT 0.1420 0.0550 0.1730 0.0650 ;
      RECT 0.1210 0.0550 0.1520 0.0650 ;
      RECT 0.1000 0.0550 0.1310 0.0650 ;
      RECT 0.0790 0.0550 0.1100 0.0650 ;
  END
END MUX2_X2

MACRO NAND2_X1
  CLASS CORE ;
  FOREIGN NAND2_X1 0 0 ;
  ORIGIN -0.0210 0.0000 ;
  SIZE 0.1260 BY 0.0800 ;
  SITE FSFET ;
  SYMMETRY X Y ;
  PIN A1
    DIRECTION INPUT ;
    USE SIGNAL ;
    PORT
      LAYER M1 ;
        RECT -0.0070 0.0330 0.0070 0.0470 ;
    END
  END A1
  PIN ZN
    DIRECTION OUTPUT ;
    USE SIGNAL ;
    PORT
      LAYER M1 ;
        RECT 0.0350 0.0130 0.0490 0.0470 ;
        RECT 0.0350 0.0330 0.0490 0.0670 ;
    END
  END ZN
  PIN A2
    DIRECTION INPUT ;
    USE SIGNAL ;
    PORT
      LAYER M1 ;
        RECT 0.0770 0.0330 0.0910 0.0470 ;
    END
  END A2
  PIN VSS
    DIRECTION INOUT ;
    USE GROUND ;
    PORT
      LAYER M0 ;
        RECT -0.0370 -0.0050 0.1210 0.0050 ;
    END
  END VSS
  PIN VDD
    DIRECTION INOUT ;
    USE POWER ;
    PORT
      LAYER M0 ;
        RECT -0.0370 0.0750 0.1210 0.0850 ;
    END
  END VDD
  OBS
    LAYER M0 ;
      RECT 0.0570 0.0350 0.0900 0.0450 ;
      RECT -0.0050 0.0350 0.0270 0.0450 ;
      RECT 0.0370 0.0550 0.0470 0.0650 ;
      RECT 0.0160 0.0150 0.0470 0.0250 ;
      RECT -0.0050 0.0150 0.0260 0.0250 ;
  END
END NAND2_X1

MACRO NAND2_X2
  CLASS CORE ;
  FOREIGN NAND2_X2 0 0 ;
  ORIGIN -0.0210 -0.0800 ;
  SIZE 0.1260 BY 0.1600 ;
  SITE FSFET ;
  SYMMETRY X Y ;
  PIN ZN
    DIRECTION OUTPUT ;
    USE SIGNAL ;
    PORT
      LAYER M1 ;
        RECT 0.0350 0.0130 0.0490 0.0470 ;
        RECT 0.0350 0.0330 0.0490 0.0670 ;
    END
  END ZN
  PIN A2
    DIRECTION INPUT ;
    USE SIGNAL ;
    PORT
      LAYER M1 ;
        RECT -0.0070 -0.0470 0.0070 -0.0330 ;
    END
  END A2
  PIN A1
    DIRECTION INPUT ;
    USE SIGNAL ;
    PORT
      LAYER M1 ;
        RECT -0.0070 0.0330 0.0070 0.0470 ;
    END
  END A1
  PIN VDD
    DIRECTION INOUT ;
    USE POWER ;
    PORT
      LAYER M0 ;
        RECT -0.0370 -0.0850 0.1210 -0.0750 ;
    END
  END VDD
  PIN VSS
    DIRECTION INOUT ;
    USE GROUND ;
    PORT
      LAYER M0 ;
        RECT -0.0370 -0.0050 0.1210 0.0050 ;
    END
  END VSS
  PIN VDD
    DIRECTION INOUT ;
    USE POWER ;
    PORT
      LAYER M0 ;
        RECT -0.0370 0.0750 0.1210 0.0850 ;
    END
  END VDD
  OBS
    LAYER M1 ;
      RECT 0.0350 -0.0670 0.0490 -0.0330 ;
      RECT 0.0350 -0.0470 0.0490 -0.0130 ;
      RECT 0.0350 -0.0270 0.0490 0.0070 ;
      RECT 0.0350 -0.0070 0.0490 0.0270 ;
      RECT 0.0770 -0.0270 0.0910 0.0070 ;
      RECT 0.0770 -0.0070 0.0910 0.0270 ;
      RECT -0.0070 -0.0270 0.0070 0.0070 ;
      RECT -0.0070 -0.0070 0.0070 0.0270 ;
    LAYER M0 ;
      RECT 0.0370 -0.0650 0.0470 -0.0550 ;
      RECT 0.0370 -0.0250 0.0470 -0.0150 ;
      RECT 0.0370 0.0550 0.0470 0.0650 ;
      RECT 0.0790 -0.0250 0.0890 -0.0150 ;
      RECT -0.0050 -0.0250 0.0050 -0.0150 ;
      RECT 0.0370 -0.0450 0.0680 -0.0350 ;
      RECT -0.0050 -0.0450 0.0470 -0.0350 ;
      RECT 0.0370 0.0350 0.0680 0.0450 ;
      RECT -0.0050 0.0350 0.0470 0.0450 ;
      RECT 0.0580 0.0150 0.0890 0.0250 ;
      RECT 0.0370 0.0150 0.0680 0.0250 ;
      RECT 0.0160 0.0150 0.0470 0.0250 ;
      RECT -0.0050 0.0150 0.0260 0.0250 ;
  END
END NAND2_X2

MACRO NAND2_X4
  CLASS CORE ;
  FOREIGN NAND2_X4 0 0 ;
  ORIGIN -0.0210 -0.0800 ;
  SIZE 0.2100 BY 0.1600 ;
  SITE FSFET ;
  SYMMETRY X Y ;
  PIN ZN
    DIRECTION OUTPUT ;
    USE SIGNAL ;
    PORT
      LAYER M1 ;
        RECT 0.1190 -0.0270 0.1330 0.0070 ;
        RECT 0.1190 -0.0070 0.1330 0.0270 ;
        RECT 0.0350 -0.0270 0.0490 0.0070 ;
        RECT 0.0350 -0.0070 0.0490 0.0270 ;
    END
  END ZN
  PIN A2
    DIRECTION INPUT ;
    USE SIGNAL ;
    PORT
      LAYER M1 ;
        RECT -0.0070 -0.0470 0.0070 -0.0330 ;
    END
  END A2
  PIN A1
    DIRECTION INPUT ;
    USE SIGNAL ;
    PORT
      LAYER M1 ;
        RECT -0.0070 0.0330 0.0070 0.0470 ;
    END
  END A1
  PIN VDD
    DIRECTION INOUT ;
    USE POWER ;
    PORT
      LAYER M0 ;
        RECT -0.0370 -0.0850 0.2050 -0.0750 ;
    END
  END VDD
  PIN VSS
    DIRECTION INOUT ;
    USE GROUND ;
    PORT
      LAYER M0 ;
        RECT -0.0370 -0.0050 0.2050 0.0050 ;
    END
  END VSS
  PIN VDD
    DIRECTION INOUT ;
    USE POWER ;
    PORT
      LAYER M0 ;
        RECT -0.0370 0.0750 0.2050 0.0850 ;
    END
  END VDD
  OBS
    LAYER M1 ;
      RECT 0.1610 -0.0270 0.1750 0.0070 ;
      RECT 0.1610 -0.0070 0.1750 0.0270 ;
      RECT 0.0770 -0.0270 0.0910 0.0070 ;
      RECT 0.0770 -0.0070 0.0910 0.0270 ;
      RECT -0.0070 -0.0270 0.0070 0.0070 ;
      RECT -0.0070 -0.0070 0.0070 0.0270 ;
      RECT 0.1190 -0.0670 0.1330 -0.0330 ;
      RECT 0.1190 -0.0470 0.1330 -0.0130 ;
      RECT 0.1190 0.0130 0.1330 0.0470 ;
      RECT 0.1190 0.0330 0.1330 0.0670 ;
      RECT 0.0350 -0.0670 0.0490 -0.0330 ;
      RECT 0.0350 -0.0470 0.0490 -0.0130 ;
      RECT 0.0350 0.0130 0.0490 0.0470 ;
      RECT 0.0350 0.0330 0.0490 0.0670 ;
    LAYER M0 ;
      RECT 0.1630 -0.0250 0.1730 -0.0150 ;
      RECT 0.0790 -0.0250 0.0890 -0.0150 ;
      RECT -0.0050 -0.0250 0.0050 -0.0150 ;
      RECT 0.1210 -0.0250 0.1310 -0.0150 ;
      RECT 0.0370 -0.0250 0.0470 -0.0150 ;
      RECT 0.1210 0.0550 0.1310 0.0650 ;
      RECT 0.0370 0.0550 0.0470 0.0650 ;
      RECT 0.1210 -0.0450 0.1520 -0.0350 ;
      RECT 0.1000 -0.0450 0.1310 -0.0350 ;
      RECT 0.0790 -0.0450 0.1100 -0.0350 ;
      RECT 0.0580 -0.0450 0.0890 -0.0350 ;
      RECT 0.0370 -0.0450 0.0680 -0.0350 ;
      RECT -0.0050 -0.0450 0.0470 -0.0350 ;
      RECT 0.1210 0.0350 0.1520 0.0450 ;
      RECT 0.1000 0.0350 0.1310 0.0450 ;
      RECT 0.0790 0.0350 0.1100 0.0450 ;
      RECT 0.0580 0.0350 0.0890 0.0450 ;
      RECT 0.0370 0.0350 0.0680 0.0450 ;
      RECT -0.0050 0.0350 0.0470 0.0450 ;
      RECT 0.1420 0.0150 0.1730 0.0250 ;
      RECT 0.1210 0.0150 0.1520 0.0250 ;
      RECT 0.1000 0.0150 0.1310 0.0250 ;
      RECT 0.0790 0.0150 0.1100 0.0250 ;
      RECT 0.0580 0.0150 0.0890 0.0250 ;
      RECT 0.0370 0.0150 0.0680 0.0250 ;
      RECT 0.0160 0.0150 0.0470 0.0250 ;
      RECT -0.0050 0.0150 0.0260 0.0250 ;
      RECT 0.1000 -0.0650 0.1310 -0.0550 ;
      RECT 0.0790 -0.0650 0.1100 -0.0550 ;
      RECT 0.0580 -0.0650 0.0890 -0.0550 ;
      RECT 0.0370 -0.0650 0.0680 -0.0550 ;
  END
END NAND2_X4

MACRO NAND3_X1
  CLASS CORE ;
  FOREIGN NAND3_X1 0 0 ;
  ORIGIN -0.0210 0.0000 ;
  SIZE 0.1680 BY 0.0800 ;
  SITE FSFET ;
  SYMMETRY X Y ;
  PIN ZN
    DIRECTION OUTPUT ;
    USE SIGNAL ;
    PORT
      LAYER M1 ;
        RECT 0.0770 0.0130 0.0910 0.0470 ;
        RECT 0.0770 0.0330 0.0910 0.0670 ;
    END
  END ZN
  PIN A1
    DIRECTION INPUT ;
    USE SIGNAL ;
    PORT
      LAYER M1 ;
        RECT 0.1190 0.0330 0.1330 0.0470 ;
    END
  END A1
  PIN A2
    DIRECTION INPUT ;
    USE SIGNAL ;
    PORT
      LAYER M1 ;
        RECT 0.0350 0.0330 0.0490 0.0470 ;
    END
  END A2
  PIN A3
    DIRECTION INPUT ;
    USE SIGNAL ;
    PORT
      LAYER M1 ;
        RECT -0.0070 0.0130 0.0070 0.0270 ;
    END
  END A3
  PIN VSS
    DIRECTION INOUT ;
    USE GROUND ;
    PORT
      LAYER M0 ;
        RECT -0.0370 -0.0050 0.1630 0.0050 ;
    END
  END VSS
  PIN VDD
    DIRECTION INOUT ;
    USE POWER ;
    PORT
      LAYER M0 ;
        RECT -0.0370 0.0750 0.1630 0.0850 ;
    END
  END VDD
  OBS
    LAYER M0 ;
      RECT 0.0990 0.0350 0.1310 0.0450 ;
      RECT 0.0370 0.0350 0.0690 0.0450 ;
      RECT -0.0050 0.0150 0.0270 0.0250 ;
      RECT 0.1000 0.0150 0.1310 0.0250 ;
      RECT 0.0790 0.0150 0.1100 0.0250 ;
      RECT 0.0580 0.0550 0.0890 0.0650 ;
      RECT 0.0370 0.0550 0.0680 0.0650 ;
      RECT 0.0160 0.0550 0.0470 0.0650 ;
      RECT -0.0050 0.0550 0.0260 0.0650 ;
  END
END NAND3_X1

MACRO NAND4_X1
  CLASS CORE ;
  FOREIGN NAND4_X1 0 0 ;
  ORIGIN -0.0210 0.0000 ;
  SIZE 0.2520 BY 0.0800 ;
  SITE FSFET ;
  SYMMETRY X Y ;
  PIN ZN
    DIRECTION OUTPUT ;
    USE SIGNAL ;
    PORT
      LAYER M1 ;
        RECT 0.0350 0.0130 0.0490 0.0470 ;
        RECT 0.0350 0.0330 0.0490 0.0670 ;
    END
  END ZN
  PIN A4
    DIRECTION INPUT ;
    USE SIGNAL ;
    PORT
      LAYER M1 ;
        RECT 0.2030 0.0330 0.2170 0.0470 ;
    END
  END A4
  PIN A3
    DIRECTION INPUT ;
    USE SIGNAL ;
    PORT
      LAYER M1 ;
        RECT 0.1190 0.0330 0.1330 0.0470 ;
    END
  END A3
  PIN A2
    DIRECTION INPUT ;
    USE SIGNAL ;
    PORT
      LAYER M1 ;
        RECT 0.0770 0.0130 0.0910 0.0270 ;
    END
  END A2
  PIN A1
    DIRECTION INPUT ;
    USE SIGNAL ;
    PORT
      LAYER M1 ;
        RECT -0.0070 0.0330 0.0070 0.0470 ;
    END
  END A1
  PIN VDD
    DIRECTION INOUT ;
    USE POWER ;
    PORT
      LAYER M0 ;
        RECT -0.0370 0.0750 0.2470 0.0850 ;
    END
  END VDD
  PIN VSS
    DIRECTION INOUT ;
    USE GROUND ;
    PORT
      LAYER M0 ;
        RECT -0.0370 -0.0050 0.2470 0.0050 ;
    END
  END VSS
  OBS
    LAYER M0 ;
      RECT 0.1830 0.0350 0.2150 0.0450 ;
      RECT 0.0990 0.0350 0.1310 0.0450 ;
      RECT 0.0570 0.0150 0.0890 0.0250 ;
      RECT -0.0050 0.0350 0.0270 0.0450 ;
      RECT 0.1420 0.0150 0.1730 0.0250 ;
      RECT 0.1210 0.0150 0.1520 0.0250 ;
      RECT 0.0160 0.0150 0.0470 0.0250 ;
      RECT -0.0050 0.0150 0.0260 0.0250 ;
      RECT 0.1840 0.0550 0.2150 0.0650 ;
      RECT 0.1630 0.0550 0.1940 0.0650 ;
      RECT 0.1420 0.0550 0.1730 0.0650 ;
      RECT 0.1210 0.0550 0.1520 0.0650 ;
      RECT 0.1000 0.0550 0.1310 0.0650 ;
      RECT 0.0790 0.0550 0.1100 0.0650 ;
      RECT 0.0580 0.0550 0.0890 0.0650 ;
      RECT 0.0370 0.0550 0.0680 0.0650 ;
  END
END NAND4_X1

MACRO NOR2_X1
  CLASS CORE ;
  FOREIGN NOR2_X1 0 0 ;
  ORIGIN -0.0210 0.0000 ;
  SIZE 0.1260 BY 0.0800 ;
  SITE FSFET ;
  SYMMETRY X Y ;
  PIN A2
    DIRECTION INPUT ;
    USE SIGNAL ;
    PORT
      LAYER M1 ;
        RECT 0.0770 0.0330 0.0910 0.0470 ;
    END
  END A2
  PIN A1
    DIRECTION INPUT ;
    USE SIGNAL ;
    PORT
      LAYER M1 ;
        RECT -0.0070 0.0330 0.0070 0.0470 ;
    END
  END A1
  PIN ZN
    DIRECTION OUTPUT ;
    USE SIGNAL ;
    PORT
      LAYER M1 ;
        RECT 0.0350 0.0130 0.0490 0.0470 ;
        RECT 0.0350 0.0330 0.0490 0.0670 ;
    END
  END ZN
  PIN VSS
    DIRECTION INOUT ;
    USE GROUND ;
    PORT
      LAYER M0 ;
        RECT -0.0370 -0.0050 0.1210 0.0050 ;
    END
  END VSS
  PIN VDD
    DIRECTION INOUT ;
    USE POWER ;
    PORT
      LAYER M0 ;
        RECT -0.0370 0.0750 0.1210 0.0850 ;
    END
  END VDD
  OBS
    LAYER M0 ;
      RECT 0.0570 0.0350 0.0890 0.0450 ;
      RECT -0.0050 0.0350 0.0270 0.0450 ;
      RECT 0.0370 0.0150 0.0470 0.0250 ;
      RECT 0.0580 0.0550 0.0890 0.0650 ;
      RECT 0.0370 0.0550 0.0680 0.0650 ;
  END
END NOR2_X1

MACRO NOR2_X2
  CLASS CORE ;
  FOREIGN NOR2_X2 0 0 ;
  ORIGIN -0.0210 -0.0800 ;
  SIZE 0.1260 BY 0.1600 ;
  SITE FSFET ;
  SYMMETRY X Y ;
  PIN A1
    DIRECTION INPUT ;
    USE SIGNAL ;
    PORT
      LAYER M1 ;
        RECT 0.0770 -0.0070 0.0910 0.0270 ;
    END
  END A1
  PIN A2
    DIRECTION INPUT ;
    USE SIGNAL ;
    PORT
      LAYER M1 ;
        RECT 0.0350 0.0130 0.0490 0.0470 ;
    END
  END A2
  PIN ZN
    DIRECTION OUTPUT ;
    USE SIGNAL ;
    PORT
      LAYER M1 ;
        RECT -0.0070 0.0130 0.0070 0.0470 ;
        RECT -0.0070 0.0330 0.0070 0.0670 ;
    END
  END ZN
  PIN VDD
    DIRECTION INOUT ;
    USE POWER ;
    PORT
      LAYER M0 ;
        RECT -0.0370 0.0750 0.1210 0.0850 ;
    END
  END VDD
  PIN VSS
    DIRECTION INOUT ;
    USE GROUND ;
    PORT
      LAYER M0 ;
        RECT -0.0370 -0.0050 0.1210 0.0050 ;
    END
  END VSS
  PIN VDD
    DIRECTION INOUT ;
    USE POWER ;
    PORT
      LAYER M0 ;
        RECT -0.0370 -0.0850 0.1210 -0.0750 ;
    END
  END VDD
  OBS
    LAYER M1 ;
      RECT 0.0770 -0.0670 0.0910 -0.0330 ;
      RECT 0.0770 -0.0470 0.0910 -0.0130 ;
      RECT 0.0770 -0.0270 0.0910 0.0070 ;
      RECT 0.0350 -0.0470 0.0490 -0.0130 ;
      RECT 0.0350 -0.0270 0.0490 0.0070 ;
      RECT 0.0350 -0.0070 0.0490 0.0270 ;
      RECT -0.0070 -0.0670 0.0070 -0.0330 ;
      RECT -0.0070 -0.0470 0.0070 -0.0130 ;
      RECT -0.0070 -0.0270 0.0070 0.0070 ;
      RECT -0.0070 -0.0070 0.0070 0.0270 ;
    LAYER M0 ;
      RECT -0.0050 -0.0650 0.0050 -0.0550 ;
      RECT 0.0580 -0.0650 0.0890 -0.0550 ;
      RECT 0.0370 -0.0650 0.0680 -0.0550 ;
      RECT 0.0160 -0.0650 0.0470 -0.0550 ;
      RECT 0.0580 0.0150 0.0890 0.0250 ;
      RECT 0.0370 -0.0450 0.0680 -0.0350 ;
      RECT 0.0160 0.0350 0.0470 0.0450 ;
      RECT 0.0160 -0.0250 0.0470 -0.0150 ;
      RECT -0.0050 -0.0250 0.0260 -0.0150 ;
      RECT 0.0160 0.0150 0.0470 0.0250 ;
      RECT -0.0050 0.0150 0.0260 0.0250 ;
      RECT 0.0580 0.0550 0.0890 0.0650 ;
      RECT 0.0370 0.0550 0.0680 0.0650 ;
      RECT 0.0160 0.0550 0.0470 0.0650 ;
      RECT -0.0050 0.0550 0.0260 0.0650 ;
  END
END NOR2_X2

MACRO NOR2_X4
  CLASS CORE ;
  FOREIGN NOR2_X4 0 0 ;
  ORIGIN -0.0210 -0.0800 ;
  SIZE 0.2100 BY 0.1600 ;
  SITE FSFET ;
  SYMMETRY X Y ;
  PIN A2
    DIRECTION INPUT ;
    USE SIGNAL ;
    PORT
      LAYER M1 ;
        RECT 0.1610 0.0130 0.1750 0.0470 ;
        RECT -0.0070 -0.0070 0.0070 0.0270 ;
    END
  END A2
  PIN ZN
    DIRECTION OUTPUT ;
    USE SIGNAL ;
    PORT
      LAYER M1 ;
        RECT 0.1190 -0.0070 0.1330 0.0270 ;
        RECT 0.0350 -0.0070 0.0490 0.0270 ;
    END
  END ZN
  PIN A1
    DIRECTION INPUT ;
    USE SIGNAL ;
    PORT
      LAYER M1 ;
        RECT 0.0770 -0.0070 0.0910 0.0270 ;
    END
  END A1
  PIN VDD
    DIRECTION INOUT ;
    USE POWER ;
    PORT
      LAYER M0 ;
        RECT -0.0370 0.0750 0.2050 0.0850 ;
    END
  END VDD
  PIN VSS
    DIRECTION INOUT ;
    USE GROUND ;
    PORT
      LAYER M0 ;
        RECT -0.0370 -0.0050 0.2050 0.0050 ;
    END
  END VSS
  PIN VDD
    DIRECTION INOUT ;
    USE POWER ;
    PORT
      LAYER M0 ;
        RECT -0.0370 -0.0850 0.2050 -0.0750 ;
    END
  END VDD
  OBS
    LAYER M1 ;
      RECT 0.0770 -0.0270 0.0910 0.0070 ;
      RECT 0.1610 -0.0270 0.1750 0.0070 ;
      RECT 0.1610 -0.0070 0.1750 0.0270 ;
      RECT -0.0070 -0.0270 0.0070 0.0070 ;
      RECT 0.1190 -0.0470 0.1330 -0.0130 ;
      RECT 0.1190 -0.0270 0.1330 0.0070 ;
      RECT 0.0770 -0.0670 0.0910 -0.0330 ;
      RECT 0.0350 -0.0470 0.0490 -0.0130 ;
      RECT 0.0350 -0.0270 0.0490 0.0070 ;
      RECT 0.0350 0.0130 0.0490 0.0470 ;
      RECT 0.0350 0.0330 0.0490 0.0670 ;
    LAYER M0 ;
      RECT 0.0790 -0.0650 0.0890 -0.0550 ;
      RECT 0.1210 -0.0250 0.1310 -0.0150 ;
      RECT 0.0370 -0.0250 0.0470 -0.0150 ;
      RECT 0.1210 0.0150 0.1310 0.0250 ;
      RECT 0.0370 0.0150 0.0470 0.0250 ;
      RECT 0.0790 -0.0250 0.1100 -0.0150 ;
      RECT 0.0580 -0.0250 0.0890 -0.0150 ;
      RECT 0.0790 0.0150 0.1100 0.0250 ;
      RECT 0.0580 0.0150 0.0890 0.0250 ;
      RECT 0.1420 -0.0250 0.1730 -0.0150 ;
      RECT -0.0050 -0.0250 0.0260 -0.0150 ;
      RECT -0.0050 0.0150 0.0260 0.0250 ;
      RECT 0.1420 0.0350 0.1730 0.0450 ;
      RECT 0.1210 0.0350 0.1520 0.0450 ;
      RECT 0.1000 0.0350 0.1310 0.0450 ;
      RECT 0.0790 0.0350 0.1100 0.0450 ;
      RECT 0.0580 0.0350 0.0890 0.0450 ;
      RECT 0.0370 0.0350 0.0680 0.0450 ;
      RECT 0.0160 0.0350 0.0470 0.0450 ;
      RECT 0.1000 -0.0450 0.1310 -0.0350 ;
      RECT 0.0790 -0.0450 0.1100 -0.0350 ;
      RECT 0.0580 -0.0450 0.0890 -0.0350 ;
      RECT 0.0370 -0.0450 0.0680 -0.0350 ;
      RECT 0.0580 0.0550 0.0890 0.0650 ;
      RECT 0.0370 0.0550 0.0680 0.0650 ;
  END
END NOR2_X4

MACRO NOR3_X1
  CLASS CORE ;
  FOREIGN NOR3_X1 0 0 ;
  ORIGIN -0.0210 0.0000 ;
  SIZE 0.1680 BY 0.0800 ;
  SITE FSFET ;
  SYMMETRY X Y ;
  PIN A3
    DIRECTION INPUT ;
    USE SIGNAL ;
    PORT
      LAYER M1 ;
        RECT 0.1200 0.0330 0.1340 0.0470 ;
    END
  END A3
  PIN A2
    DIRECTION INPUT ;
    USE SIGNAL ;
    PORT
      LAYER M1 ;
        RECT 0.0770 0.0330 0.0910 0.0470 ;
    END
  END A2
  PIN A1
    DIRECTION INPUT ;
    USE SIGNAL ;
    PORT
      LAYER M1 ;
        RECT -0.0070 0.0330 0.0070 0.0470 ;
    END
  END A1
  PIN ZN
    DIRECTION OUTPUT ;
    USE SIGNAL ;
    PORT
      LAYER M1 ;
        RECT 0.0350 0.0130 0.0490 0.0470 ;
        RECT 0.0350 0.0330 0.0490 0.0670 ;
    END
  END ZN
  PIN VSS
    DIRECTION INOUT ;
    USE GROUND ;
    PORT
      LAYER M0 ;
        RECT -0.0370 -0.0050 0.1630 0.0050 ;
    END
  END VSS
  PIN VDD
    DIRECTION INOUT ;
    USE POWER ;
    PORT
      LAYER M0 ;
        RECT -0.0370 0.0750 0.1630 0.0850 ;
    END
  END VDD
  OBS
    LAYER M0 ;
      RECT 0.1000 0.0350 0.1330 0.0450 ;
      RECT 0.0570 0.0350 0.0900 0.0450 ;
      RECT -0.0050 0.0350 0.0260 0.0450 ;
      RECT 0.1000 0.0150 0.1310 0.0250 ;
      RECT 0.0790 0.0150 0.1100 0.0250 ;
      RECT 0.0580 0.0150 0.0890 0.0250 ;
      RECT 0.0370 0.0150 0.0680 0.0250 ;
      RECT 0.0160 0.0550 0.0470 0.0650 ;
      RECT -0.0050 0.0550 0.0260 0.0650 ;
  END
END NOR3_X1

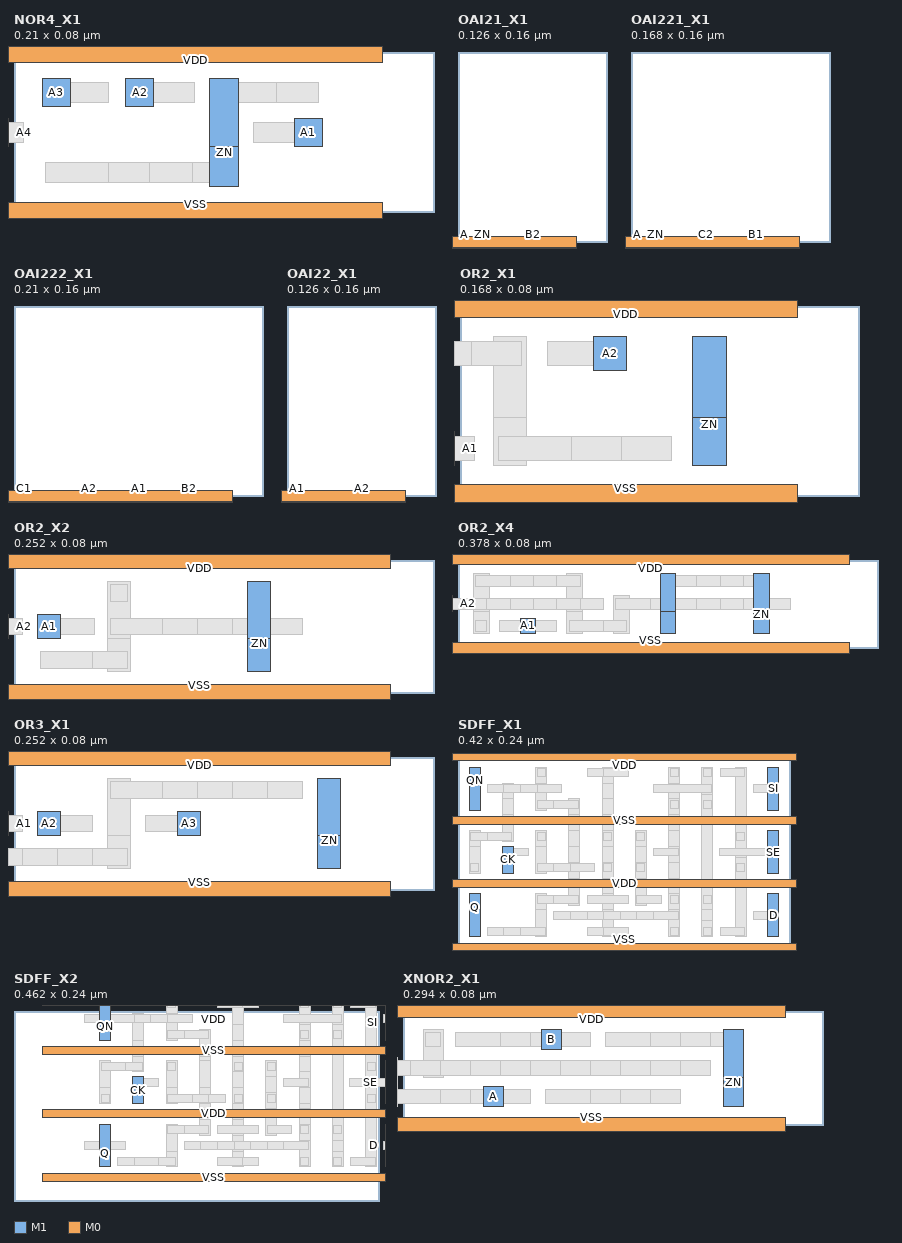
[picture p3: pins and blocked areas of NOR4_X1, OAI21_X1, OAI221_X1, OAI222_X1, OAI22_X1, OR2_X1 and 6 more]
MACRO NOR4_X1
  CLASS CORE ;
  FOREIGN NOR4_X1 0 0 ;
  ORIGIN -0.0210 0.0000 ;
  SIZE 0.2100 BY 0.0800 ;
  SITE FSFET ;
  SYMMETRY X Y ;
  PIN A1
    DIRECTION INPUT ;
    USE SIGNAL ;
    PORT
      LAYER M1 ;
        RECT 0.1610 0.0330 0.1750 0.0470 ;
    END
  END A1
  PIN ZN
    DIRECTION OUTPUT ;
    USE SIGNAL ;
    PORT
      LAYER M1 ;
        RECT 0.1190 0.0130 0.1330 0.0470 ;
        RECT 0.1190 0.0330 0.1330 0.0670 ;
    END
  END ZN
  PIN A2
    DIRECTION INPUT ;
    USE SIGNAL ;
    PORT
      LAYER M1 ;
        RECT 0.0770 0.0530 0.0910 0.0670 ;
    END
  END A2
  PIN A3
    DIRECTION INPUT ;
    USE SIGNAL ;
    PORT
      LAYER M1 ;
        RECT 0.0350 0.0530 0.0490 0.0670 ;
    END
  END A3
  PIN A4
    DIRECTION INPUT ;
    USE SIGNAL ;
    PORT
      LAYER M1 ;
        RECT -0.0070 0.0330 0.0070 0.0470 ;
    END
  END A4
  PIN VSS
    DIRECTION INOUT ;
    USE GROUND ;
    PORT
      LAYER M0 ;
        RECT -0.0370 -0.0050 0.2050 0.0050 ;
    END
  END VSS
  PIN VDD
    DIRECTION INOUT ;
    USE POWER ;
    PORT
      LAYER M0 ;
        RECT -0.0370 0.0750 0.2050 0.0850 ;
    END
  END VDD
  OBS
    LAYER M0 ;
      RECT 0.1410 0.0350 0.1740 0.0450 ;
      RECT 0.0780 0.0550 0.1110 0.0650 ;
      RECT 0.0370 0.0550 0.0680 0.0650 ;
      RECT -0.0060 0.0350 0.0260 0.0450 ;
      RECT 0.1000 0.0150 0.1310 0.0250 ;
      RECT 0.0790 0.0150 0.1100 0.0250 ;
      RECT 0.0580 0.0150 0.0890 0.0250 ;
      RECT 0.0370 0.0150 0.0680 0.0250 ;
      RECT 0.1420 0.0550 0.1730 0.0650 ;
      RECT 0.1210 0.0550 0.1520 0.0650 ;
  END
END NOR4_X1

MACRO OAI21_X1
  CLASS CORE ;
  FOREIGN OAI21_X1 0 0 ;
  ORIGIN -0.0210 -0.0800 ;
  SIZE 0.1260 BY 0.1600 ;
  SITE FSFET ;
  SYMMETRY X Y ;
  PIN A
    DIRECTION INPUT ;
    USE SIGNAL ;
    PORT
      LAYER M1 ;
        RECT -0.0070 -0.0470 0.0070 -0.0330 ;
    END
  END A
  PIN ZN
    DIRECTION OUTPUT ;
    USE SIGNAL ;
    PORT
      LAYER M1 ;
        RECT 0.0350 0.0130 0.0490 0.0470 ;
        RECT 0.0350 0.0330 0.0490 0.0670 ;
    END
  END ZN
  PIN B2
    DIRECTION INPUT ;
    USE SIGNAL ;
    PORT
      LAYER M1 ;
        RECT 0.0770 0.0330 0.0910 0.0470 ;
    END
  END B2
  PIN B1
    DIRECTION INPUT ;
    USE SIGNAL ;
    PORT
      LAYER M1 ;
        RECT -0.0070 0.0330 0.0070 0.0470 ;
    END
  END B1
  PIN VDD
    DIRECTION INOUT ;
    USE POWER ;
    PORT
      LAYER M0 ;
        RECT -0.0370 0.0750 0.1210 0.0850 ;
    END
  END VDD
  PIN VSS
    DIRECTION INOUT ;
    USE GROUND ;
    PORT
      LAYER M0 ;
        RECT -0.0370 -0.0050 0.1210 0.0050 ;
    END
  END VSS
  PIN VDD
    DIRECTION INOUT ;
    USE POWER ;
    PORT
      LAYER M0 ;
        RECT -0.0370 -0.0850 0.1210 -0.0750 ;
    END
  END VDD
  OBS
    LAYER M1 ;
      RECT 0.0350 -0.0670 0.0490 -0.0330 ;
      RECT 0.0350 -0.0470 0.0490 -0.0130 ;
      RECT 0.0350 -0.0270 0.0490 0.0070 ;
      RECT 0.0350 -0.0070 0.0490 0.0270 ;
      RECT 0.0770 -0.0270 0.0910 0.0070 ;
      RECT 0.0770 -0.0070 0.0910 0.0270 ;
      RECT -0.0070 -0.0270 0.0070 0.0070 ;
      RECT -0.0070 -0.0070 0.0070 0.0270 ;
    LAYER M0 ;
      RECT -0.0050 -0.0450 0.0260 -0.0350 ;
      RECT 0.0580 0.0350 0.0890 0.0450 ;
      RECT -0.0050 0.0350 0.0260 0.0450 ;
      RECT 0.0370 -0.0650 0.0470 -0.0550 ;
      RECT 0.0370 0.0150 0.0470 0.0250 ;
      RECT 0.0790 0.0150 0.0890 0.0250 ;
      RECT -0.0050 0.0150 0.0050 0.0250 ;
      RECT 0.0160 0.0550 0.0470 0.0650 ;
      RECT -0.0050 0.0550 0.0260 0.0650 ;
      RECT 0.0580 -0.0250 0.0890 -0.0150 ;
      RECT 0.0370 -0.0250 0.0680 -0.0150 ;
      RECT 0.0160 -0.0250 0.0470 -0.0150 ;
      RECT -0.0050 -0.0250 0.0260 -0.0150 ;
  END
END OAI21_X1

MACRO OAI221_X1
  CLASS CORE ;
  FOREIGN OAI221_X1 0 0 ;
  ORIGIN -0.0210 -0.0800 ;
  SIZE 0.1680 BY 0.1600 ;
  SITE FSFET ;
  SYMMETRY X Y ;
  PIN C2
    DIRECTION INPUT ;
    USE SIGNAL ;
    PORT
      LAYER M1 ;
        RECT 0.0770 -0.0470 0.0910 -0.0330 ;
    END
  END C2
  PIN C1
    DIRECTION INPUT ;
    USE SIGNAL ;
    PORT
      LAYER M1 ;
        RECT -0.0070 -0.0670 0.0070 -0.0530 ;
    END
  END C1
  PIN B1
    DIRECTION INPUT ;
    USE SIGNAL ;
    PORT
      LAYER M1 ;
        RECT 0.1190 0.0530 0.1330 0.0670 ;
    END
  END B1
  PIN B2
    DIRECTION INPUT ;
    USE SIGNAL ;
    PORT
      LAYER M1 ;
        RECT 0.0770 0.0530 0.0910 0.0670 ;
    END
  END B2
  PIN A
    DIRECTION INPUT ;
    USE SIGNAL ;
    PORT
      LAYER M1 ;
        RECT -0.0070 0.0530 0.0070 0.0670 ;
    END
  END A
  PIN ZN
    DIRECTION OUTPUT ;
    USE SIGNAL ;
    PORT
      LAYER M1 ;
        RECT 0.0350 -0.0070 0.0490 0.0270 ;
        RECT 0.0350 0.0130 0.0490 0.0470 ;
        RECT 0.0350 0.0130 0.0490 0.0470 ;
    END
  END ZN
  PIN VDD
    DIRECTION INOUT ;
    USE POWER ;
    PORT
      LAYER M0 ;
        RECT -0.0370 -0.0850 0.1630 -0.0750 ;
    END
  END VDD
  PIN VSS
    DIRECTION INOUT ;
    USE GROUND ;
    PORT
      LAYER M0 ;
        RECT -0.0370 -0.0050 0.1630 0.0050 ;
    END
  END VSS
  PIN VDD
    DIRECTION INOUT ;
    USE POWER ;
    PORT
      LAYER M0 ;
        RECT -0.0370 0.0750 0.1630 0.0850 ;
    END
  END VDD
  OBS
    LAYER M1 ;
      RECT 0.0350 -0.0670 0.0490 -0.0330 ;
      RECT 0.0350 -0.0470 0.0490 -0.0130 ;
      RECT 0.0350 -0.0270 0.0490 0.0070 ;
      RECT 0.0350 0.0330 0.0490 0.0670 ;
      RECT 0.0770 -0.0270 0.0910 0.0470 ;
      RECT -0.0070 -0.0270 0.0070 0.0070 ;
      RECT -0.0070 -0.0070 0.0070 0.0470 ;
      RECT 0.0350 0.0530 0.0490 0.0670 ;
    LAYER M0 ;
      RECT 0.0580 -0.0450 0.0890 -0.0350 ;
      RECT -0.0050 -0.0650 0.0260 -0.0550 ;
      RECT 0.1000 0.0550 0.1310 0.0650 ;
      RECT 0.0580 0.0550 0.0890 0.0650 ;
      RECT -0.0050 0.0550 0.0260 0.0650 ;
      RECT 0.0370 -0.0250 0.0470 -0.0150 ;
      RECT 0.0370 0.0550 0.0470 0.0650 ;
      RECT 0.0790 -0.0250 0.0890 -0.0150 ;
      RECT -0.0050 -0.0250 0.0050 -0.0150 ;
      RECT -0.0050 0.0150 0.0050 0.0250 ;
      RECT 0.0580 -0.0650 0.0890 -0.0550 ;
      RECT 0.0370 -0.0650 0.0680 -0.0550 ;
      RECT 0.0580 0.0350 0.0890 0.0450 ;
      RECT 0.0370 0.0350 0.0680 0.0450 ;
      RECT 0.0160 0.0350 0.0470 0.0450 ;
      RECT -0.0050 0.0350 0.0260 0.0450 ;
      RECT 0.1000 0.0150 0.1310 0.0250 ;
      RECT 0.0790 0.0150 0.1100 0.0250 ;
      RECT 0.0580 0.0150 0.0890 0.0250 ;
      RECT 0.0370 0.0150 0.0680 0.0250 ;
  END
END OAI221_X1

MACRO OAI222_X1
  CLASS CORE ;
  FOREIGN OAI222_X1 0 0 ;
  ORIGIN -0.0210 -0.0800 ;
  SIZE 0.2100 BY 0.1600 ;
  SITE FSFET ;
  SYMMETRY X Y ;
  PIN ZN
    DIRECTION OUTPUT ;
    USE SIGNAL ;
    PORT
      LAYER M1 ;
        RECT 0.0350 0.0330 0.0490 0.0670 ;
    END
  END ZN
  PIN A2
    DIRECTION INPUT ;
    USE SIGNAL ;
    PORT
      LAYER M1 ;
        RECT 0.0770 -0.0670 0.0910 -0.0530 ;
    END
  END A2
  PIN A1
    DIRECTION INPUT ;
    USE SIGNAL ;
    PORT
      LAYER M1 ;
        RECT 0.1190 -0.0670 0.1330 -0.0530 ;
    END
  END A1
  PIN B2
    DIRECTION INPUT ;
    USE SIGNAL ;
    PORT
      LAYER M1 ;
        RECT 0.1610 0.0530 0.1750 0.0670 ;
    END
  END B2
  PIN B1
    DIRECTION INPUT ;
    USE SIGNAL ;
    PORT
      LAYER M1 ;
        RECT 0.1190 0.0530 0.1330 0.0670 ;
    END
  END B1
  PIN C1
    DIRECTION INPUT ;
    USE SIGNAL ;
    PORT
      LAYER M1 ;
        RECT -0.0070 0.0330 0.0070 0.0470 ;
    END
  END C1
  PIN C2
    DIRECTION INPUT ;
    USE SIGNAL ;
    PORT
      LAYER M1 ;
        RECT -0.0070 0.0530 0.0070 0.0670 ;
    END
  END C2
  PIN VSS
    DIRECTION INOUT ;
    USE GROUND ;
    PORT
      LAYER M0 ;
        RECT -0.0370 -0.0050 0.2050 0.0050 ;
    END
  END VSS
  PIN VDD
    DIRECTION INOUT ;
    USE POWER ;
    PORT
      LAYER M0 ;
        RECT -0.0370 -0.0850 0.2050 -0.0750 ;
    END
  END VDD
  PIN VDD
    DIRECTION INOUT ;
    USE POWER ;
    PORT
      LAYER M0 ;
        RECT -0.0370 0.0750 0.2050 0.0850 ;
    END
  END VDD
  OBS
    LAYER M1 ;
      RECT 0.1610 -0.0670 0.1750 -0.0330 ;
      RECT 0.1610 -0.0470 0.1750 -0.0130 ;
      RECT 0.0770 -0.0470 0.0910 -0.0130 ;
      RECT 0.0350 -0.0270 0.0490 0.0070 ;
      RECT 0.0350 -0.0070 0.0490 0.0270 ;
      RECT 0.0350 0.0130 0.0490 0.0470 ;
      RECT 0.1190 -0.0270 0.1330 0.0070 ;
      RECT 0.1190 -0.0070 0.1330 0.0270 ;
      RECT 0.1610 0.0130 0.1750 0.0470 ;
      RECT 0.0770 0.0130 0.0910 0.0470 ;
    LAYER M0 ;
      RECT 0.0790 -0.0650 0.1100 -0.0550 ;
      RECT 0.1210 -0.0650 0.1520 -0.0550 ;
      RECT 0.1420 0.0550 0.1730 0.0650 ;
      RECT 0.1000 0.0550 0.1310 0.0650 ;
      RECT -0.0050 0.0350 0.0680 0.0450 ;
      RECT -0.0050 0.0550 0.0260 0.0650 ;
      RECT 0.1630 -0.0650 0.1730 -0.0550 ;
      RECT 0.1630 -0.0250 0.1730 -0.0150 ;
      RECT 0.1210 -0.0250 0.1310 -0.0150 ;
      RECT 0.1210 0.0150 0.1310 0.0250 ;
      RECT 0.1630 0.0150 0.1730 0.0250 ;
      RECT 0.1420 -0.0450 0.1730 -0.0350 ;
      RECT 0.1210 -0.0450 0.1520 -0.0350 ;
      RECT 0.1000 -0.0450 0.1310 -0.0350 ;
      RECT 0.0790 -0.0450 0.1100 -0.0350 ;
      RECT 0.0580 -0.0250 0.0890 -0.0150 ;
      RECT 0.0370 -0.0250 0.0680 -0.0150 ;
      RECT 0.0580 0.0550 0.0890 0.0650 ;
      RECT 0.0370 0.0550 0.0680 0.0650 ;
      RECT 0.0580 0.0150 0.0890 0.0250 ;
      RECT 0.0370 0.0150 0.0680 0.0250 ;
      RECT 0.0160 0.0150 0.0470 0.0250 ;
      RECT -0.0050 0.0150 0.0260 0.0250 ;
      RECT 0.1420 0.0350 0.1730 0.0450 ;
      RECT 0.1210 0.0350 0.1520 0.0450 ;
      RECT 0.1000 0.0350 0.1310 0.0450 ;
      RECT 0.0790 0.0350 0.1100 0.0450 ;
  END
END OAI222_X1

MACRO OAI22_X1
  CLASS CORE ;
  FOREIGN OAI22_X1 0 0 ;
  ORIGIN -0.0210 -0.0800 ;
  SIZE 0.1260 BY 0.1600 ;
  SITE FSFET ;
  SYMMETRY X Y ;
  PIN A2
    DIRECTION INPUT ;
    USE SIGNAL ;
    PORT
      LAYER M1 ;
        RECT 0.0770 -0.0470 0.0910 -0.0330 ;
    END
  END A2
  PIN A1
    DIRECTION INPUT ;
    USE SIGNAL ;
    PORT
      LAYER M1 ;
        RECT -0.0070 -0.0470 0.0070 -0.0330 ;
    END
  END A1
  PIN ZN
    DIRECTION OUTPUT ;
    USE SIGNAL ;
    PORT
      LAYER M1 ;
        RECT 0.0350 0.0130 0.0490 0.0470 ;
        RECT 0.0350 0.0330 0.0490 0.0670 ;
    END
  END ZN
  PIN B1
    DIRECTION INPUT ;
    USE SIGNAL ;
    PORT
      LAYER M1 ;
        RECT 0.0770 0.0330 0.0910 0.0470 ;
    END
  END B1
  PIN B2
    DIRECTION INPUT ;
    USE SIGNAL ;
    PORT
      LAYER M1 ;
        RECT -0.0070 0.0530 0.0070 0.0670 ;
    END
  END B2
  PIN VDD
    DIRECTION INOUT ;
    USE POWER ;
    PORT
      LAYER M0 ;
        RECT -0.0370 -0.0850 0.1210 -0.0750 ;
    END
  END VDD
  PIN VDD
    DIRECTION INOUT ;
    USE POWER ;
    PORT
      LAYER M0 ;
        RECT -0.0370 0.0750 0.1210 0.0850 ;
    END
  END VDD
  PIN VSS
    DIRECTION INOUT ;
    USE GROUND ;
    PORT
      LAYER M0 ;
        RECT -0.0370 -0.0050 0.1210 0.0050 ;
    END
  END VSS
  OBS
    LAYER M1 ;
      RECT 0.0350 -0.0670 0.0490 -0.0330 ;
      RECT 0.0350 -0.0470 0.0490 -0.0130 ;
      RECT 0.0350 -0.0270 0.0490 0.0070 ;
      RECT 0.0350 -0.0070 0.0490 0.0270 ;
      RECT 0.0770 -0.0270 0.0910 0.0070 ;
      RECT 0.0770 -0.0070 0.0910 0.0270 ;
      RECT -0.0070 -0.0270 0.0070 0.0070 ;
      RECT -0.0070 -0.0070 0.0070 0.0270 ;
    LAYER M0 ;
      RECT 0.0580 -0.0450 0.0890 -0.0350 ;
      RECT -0.0050 -0.0450 0.0260 -0.0350 ;
      RECT 0.0580 0.0350 0.0890 0.0450 ;
      RECT -0.0050 0.0550 0.0260 0.0650 ;
      RECT 0.0370 0.0150 0.0470 0.0250 ;
      RECT 0.0790 0.0150 0.0890 0.0250 ;
      RECT -0.0050 0.0150 0.0050 0.0250 ;
      RECT 0.0580 -0.0650 0.0890 -0.0550 ;
      RECT 0.0370 -0.0650 0.0680 -0.0550 ;
      RECT 0.0580 0.0550 0.0890 0.0650 ;
      RECT 0.0370 0.0550 0.0680 0.0650 ;
      RECT 0.0580 -0.0250 0.0890 -0.0150 ;
      RECT 0.0370 -0.0250 0.0680 -0.0150 ;
      RECT 0.0160 -0.0250 0.0470 -0.0150 ;
      RECT -0.0050 -0.0250 0.0260 -0.0150 ;
  END
END OAI22_X1

MACRO OR2_X1
  CLASS CORE ;
  FOREIGN OR2_X1 0 0 ;
  ORIGIN -0.0210 0.0000 ;
  SIZE 0.1680 BY 0.0800 ;
  SITE FSFET ;
  SYMMETRY X Y ;
  PIN ZN
    DIRECTION OUTPUT ;
    USE SIGNAL ;
    PORT
      LAYER M1 ;
        RECT 0.1190 0.0130 0.1330 0.0470 ;
        RECT 0.1190 0.0330 0.1330 0.0670 ;
    END
  END ZN
  PIN A2
    DIRECTION INPUT ;
    USE SIGNAL ;
    PORT
      LAYER M1 ;
        RECT 0.0770 0.0530 0.0910 0.0670 ;
    END
  END A2
  PIN A1
    DIRECTION INPUT ;
    USE SIGNAL ;
    PORT
      LAYER M1 ;
        RECT -0.0070 0.0130 0.0070 0.0270 ;
    END
  END A1
  PIN VSS
    DIRECTION INOUT ;
    USE GROUND ;
    PORT
      LAYER M0 ;
        RECT -0.0370 -0.0050 0.1630 0.0050 ;
    END
  END VSS
  PIN VDD
    DIRECTION INOUT ;
    USE POWER ;
    PORT
      LAYER M0 ;
        RECT -0.0370 0.0750 0.1630 0.0850 ;
    END
  END VDD
  OBS
    LAYER M1 ;
      RECT 0.0350 0.0130 0.0490 0.0470 ;
      RECT 0.0350 0.0330 0.0490 0.0670 ;
    LAYER M0 ;
      RECT 0.0580 0.0550 0.0910 0.0650 ;
      RECT -0.0060 0.0150 0.0270 0.0250 ;
      RECT 0.1210 0.0150 0.1310 0.0250 ;
      RECT 0.1210 0.0550 0.1310 0.0650 ;
      RECT 0.0790 0.0150 0.1100 0.0250 ;
      RECT 0.0580 0.0150 0.0890 0.0250 ;
      RECT 0.0370 0.0150 0.0680 0.0250 ;
      RECT 0.0160 0.0550 0.0470 0.0650 ;
      RECT -0.0050 0.0550 0.0260 0.0650 ;
  END
END OR2_X1

MACRO OR2_X2
  CLASS CORE ;
  FOREIGN OR2_X2 0 0 ;
  ORIGIN -0.0210 0.0000 ;
  SIZE 0.2520 BY 0.0800 ;
  SITE FSFET ;
  SYMMETRY X Y ;
  PIN ZN
    DIRECTION OUTPUT ;
    USE SIGNAL ;
    PORT
      LAYER M1 ;
        RECT 0.1610 0.0130 0.1750 0.0470 ;
        RECT 0.1610 0.0330 0.1750 0.0670 ;
    END
  END ZN
  PIN A1
    DIRECTION INPUT ;
    USE SIGNAL ;
    PORT
      LAYER M1 ;
        RECT 0.0350 0.0330 0.0490 0.0470 ;
    END
  END A1
  PIN A2
    DIRECTION INPUT ;
    USE SIGNAL ;
    PORT
      LAYER M1 ;
        RECT -0.0070 0.0330 0.0070 0.0470 ;
    END
  END A2
  PIN VSS
    DIRECTION INOUT ;
    USE GROUND ;
    PORT
      LAYER M0 ;
        RECT -0.0370 -0.0050 0.2470 0.0050 ;
    END
  END VSS
  PIN VDD
    DIRECTION INOUT ;
    USE POWER ;
    PORT
      LAYER M0 ;
        RECT -0.0370 0.0750 0.2470 0.0850 ;
    END
  END VDD
  OBS
    LAYER M1 ;
      RECT 0.0770 0.0130 0.0910 0.0470 ;
      RECT 0.0770 0.0330 0.0910 0.0670 ;
    LAYER M0 ;
      RECT 0.0360 0.0350 0.0690 0.0450 ;
      RECT -0.0060 0.0350 0.0260 0.0450 ;
      RECT 0.0790 0.0550 0.0890 0.0650 ;
      RECT 0.1630 0.0150 0.1730 0.0250 ;
      RECT 0.1630 0.0550 0.1730 0.0650 ;
      RECT 0.0580 0.0150 0.0890 0.0250 ;
      RECT 0.0370 0.0150 0.0680 0.0250 ;
      RECT 0.1630 0.0350 0.1940 0.0450 ;
      RECT 0.1420 0.0350 0.1730 0.0450 ;
      RECT 0.1210 0.0350 0.1520 0.0450 ;
      RECT 0.1000 0.0350 0.1310 0.0450 ;
      RECT 0.0790 0.0350 0.1100 0.0450 ;
  END
END OR2_X2

MACRO OR2_X4
  CLASS CORE ;
  FOREIGN OR2_X4 0 0 ;
  ORIGIN -0.0210 0.0000 ;
  SIZE 0.3780 BY 0.0800 ;
  SITE FSFET ;
  SYMMETRY X Y ;
  PIN ZN
    DIRECTION OUTPUT ;
    USE SIGNAL ;
    PORT
      LAYER M1 ;
        RECT 0.2870 0.0130 0.3010 0.0470 ;
        RECT 0.2870 0.0330 0.3010 0.0670 ;
        RECT 0.2030 0.0130 0.2170 0.0470 ;
        RECT 0.2030 0.0330 0.2170 0.0670 ;
    END
  END ZN
  PIN A1
    DIRECTION INPUT ;
    USE SIGNAL ;
    PORT
      LAYER M1 ;
        RECT 0.0770 0.0130 0.0910 0.0270 ;
    END
  END A1
  PIN A2
    DIRECTION INPUT ;
    USE SIGNAL ;
    PORT
      LAYER M1 ;
        RECT -0.0070 0.0330 0.0070 0.0470 ;
    END
  END A2
  PIN VSS
    DIRECTION INOUT ;
    USE GROUND ;
    PORT
      LAYER M0 ;
        RECT -0.0370 -0.0050 0.3730 0.0050 ;
    END
  END VSS
  PIN VDD
    DIRECTION INOUT ;
    USE POWER ;
    PORT
      LAYER M0 ;
        RECT -0.0370 0.0750 0.3730 0.0850 ;
    END
  END VDD
  OBS
    LAYER M1 ;
      RECT 0.1610 0.0130 0.1750 0.0470 ;
      RECT 0.1190 0.0130 0.1330 0.0470 ;
      RECT 0.1190 0.0330 0.1330 0.0670 ;
      RECT 0.0350 0.0130 0.0490 0.0470 ;
      RECT 0.0350 0.0330 0.0490 0.0670 ;
    LAYER M0 ;
      RECT 0.2890 0.0150 0.2990 0.0250 ;
      RECT 0.2050 0.0150 0.2150 0.0250 ;
      RECT 0.0370 0.0150 0.0470 0.0250 ;
      RECT 0.0790 0.0150 0.1100 0.0250 ;
      RECT 0.0580 0.0150 0.0890 0.0250 ;
      RECT 0.1210 0.0350 0.1520 0.0450 ;
      RECT 0.1000 0.0350 0.1310 0.0450 ;
      RECT 0.0790 0.0350 0.1100 0.0450 ;
      RECT 0.0580 0.0350 0.0890 0.0450 ;
      RECT 0.0370 0.0350 0.0680 0.0450 ;
      RECT -0.0050 0.0350 0.0470 0.0450 ;
      RECT 0.2680 0.0550 0.2990 0.0650 ;
      RECT 0.2470 0.0550 0.2780 0.0650 ;
      RECT 0.2260 0.0550 0.2570 0.0650 ;
      RECT 0.2050 0.0550 0.2360 0.0650 ;
      RECT 0.1420 0.0150 0.1730 0.0250 ;
      RECT 0.1210 0.0150 0.1520 0.0250 ;
      RECT 0.2890 0.0350 0.3200 0.0450 ;
      RECT 0.2680 0.0350 0.2990 0.0450 ;
      RECT 0.2470 0.0350 0.2780 0.0450 ;
      RECT 0.2260 0.0350 0.2570 0.0450 ;
      RECT 0.2050 0.0350 0.2360 0.0450 ;
      RECT 0.1840 0.0350 0.2150 0.0450 ;
      RECT 0.1630 0.0350 0.1940 0.0450 ;
      RECT 0.1000 0.0550 0.1310 0.0650 ;
      RECT 0.0790 0.0550 0.1100 0.0650 ;
      RECT 0.0580 0.0550 0.0890 0.0650 ;
      RECT 0.0370 0.0550 0.0680 0.0650 ;
  END
END OR2_X4

MACRO OR3_X1
  CLASS CORE ;
  FOREIGN OR3_X1 0 0 ;
  ORIGIN -0.0210 0.0000 ;
  SIZE 0.2520 BY 0.0800 ;
  SITE FSFET ;
  SYMMETRY X Y ;
  PIN A3
    DIRECTION INPUT ;
    USE SIGNAL ;
    PORT
      LAYER M1 ;
        RECT 0.1190 0.0330 0.1330 0.0470 ;
    END
  END A3
  PIN A2
    DIRECTION INPUT ;
    USE SIGNAL ;
    PORT
      LAYER M1 ;
        RECT 0.0350 0.0330 0.0490 0.0470 ;
    END
  END A2
  PIN A1
    DIRECTION INPUT ;
    USE SIGNAL ;
    PORT
      LAYER M1 ;
        RECT -0.0070 0.0330 0.0070 0.0470 ;
    END
  END A1
  PIN ZN
    DIRECTION OUTPUT ;
    USE SIGNAL ;
    PORT
      LAYER M1 ;
        RECT 0.2030 0.0130 0.2170 0.0470 ;
        RECT 0.2030 0.0330 0.2170 0.0670 ;
    END
  END ZN
  PIN VSS
    DIRECTION INOUT ;
    USE GROUND ;
    PORT
      LAYER M0 ;
        RECT -0.0370 -0.0050 0.2470 0.0050 ;
    END
  END VSS
  PIN VDD
    DIRECTION INOUT ;
    USE POWER ;
    PORT
      LAYER M0 ;
        RECT -0.0370 0.0750 0.2470 0.0850 ;
    END
  END VDD
  OBS
    LAYER M1 ;
      RECT 0.0770 0.0130 0.0910 0.0470 ;
      RECT 0.0770 0.0330 0.0910 0.0670 ;
    LAYER M0 ;
      RECT 0.1000 0.0350 0.1310 0.0450 ;
      RECT 0.0370 0.0350 0.0680 0.0450 ;
      RECT -0.0050 0.0350 0.0260 0.0450 ;
      RECT 0.2050 0.0150 0.2150 0.0250 ;
      RECT 0.2050 0.0550 0.2150 0.0650 ;
      RECT 0.0580 0.0150 0.0890 0.0250 ;
      RECT 0.0370 0.0150 0.0680 0.0250 ;
      RECT 0.0160 0.0150 0.0470 0.0250 ;
      RECT -0.0050 0.0150 0.0260 0.0250 ;
      RECT 0.1630 0.0550 0.1940 0.0650 ;
      RECT 0.1420 0.0550 0.1730 0.0650 ;
      RECT 0.1210 0.0550 0.1520 0.0650 ;
      RECT 0.1000 0.0550 0.1310 0.0650 ;
      RECT 0.0790 0.0550 0.1100 0.0650 ;
  END
END OR3_X1

MACRO SDFF_X1
  CLASS CORE ;
  FOREIGN SDFF_X1 0 0 ;
  ORIGIN 0.0000 0.0000 ;
  SIZE 0.4200 BY 0.2400 ;
  SITE FSFET ;
  SYMMETRY X Y ;
  PIN CK
    DIRECTION INPUT ;
    USE CLOCK ;
    PORT
      LAYER M1 ;
        RECT 0.0560 0.0930 0.0700 0.1270 ;
    END
  END CK
  PIN Q
    DIRECTION OUTPUT ;
    USE SIGNAL ;
    PORT
      LAYER M1 ;
        RECT 0.0140 0.0330 0.0280 0.0670 ;
        RECT 0.0140 0.0130 0.0280 0.0470 ;
    END
  END Q
  PIN QN
    DIRECTION OUTPUT ;
    USE SIGNAL ;
    PORT
      LAYER M1 ;
        RECT 0.0140 0.1930 0.0280 0.2270 ;
        RECT 0.0140 0.1730 0.0280 0.2070 ;
    END
  END QN
  PIN D
    DIRECTION INPUT ;
    USE SIGNAL ;
    PORT
      LAYER M1 ;
        RECT 0.3910 0.0130 0.4050 0.0670 ;
    END
  END D
  PIN SE
    DIRECTION INPUT ;
    USE SIGNAL ;
    PORT
      LAYER M1 ;
        RECT 0.3910 0.0930 0.4050 0.1470 ;
    END
  END SE
  PIN SI
    DIRECTION INPUT ;
    USE SIGNAL ;
    PORT
      LAYER M1 ;
        RECT 0.3910 0.1730 0.4050 0.2270 ;
    END
  END SI
  PIN VDD
    DIRECTION INOUT ;
    USE POWER ;
    PORT
      LAYER M0 ;
        RECT -0.0160 0.2350 0.4360 0.2450 ;
    END
  END VDD
  PIN VDD
    DIRECTION INOUT ;
    USE POWER ;
    PORT
      LAYER M0 ;
        RECT -0.0160 0.0750 0.4360 0.0850 ;
    END
  END VDD
  PIN VSS
    DIRECTION INOUT ;
    USE GROUND ;
    PORT
      LAYER M0 ;
        RECT -0.0160 -0.0050 0.4360 0.0050 ;
    END
  END VSS
  PIN VSS
    DIRECTION INOUT ;
    USE GROUND ;
    PORT
      LAYER M0 ;
        RECT -0.0160 0.1550 0.4360 0.1650 ;
    END
  END VSS
  OBS
    LAYER M1 ;
      RECT 0.1820 0.1930 0.1960 0.2270 ;
      RECT 0.1820 0.1730 0.1960 0.2070 ;
      RECT 0.1820 0.1530 0.1960 0.1870 ;
      RECT 0.1820 0.1330 0.1960 0.1670 ;
      RECT 0.1820 0.1130 0.1960 0.1470 ;
      RECT 0.1820 0.0930 0.1960 0.1270 ;
      RECT 0.1820 0.0730 0.1960 0.1070 ;
      RECT 0.1820 0.0530 0.1960 0.0870 ;
      RECT 0.1820 0.0330 0.1960 0.0670 ;
      RECT 0.1820 0.0130 0.1960 0.0470 ;
      RECT 0.0980 0.1130 0.1120 0.1470 ;
      RECT 0.0980 0.0930 0.1120 0.1270 ;
      RECT 0.0140 0.1130 0.0280 0.1470 ;
      RECT 0.0140 0.0930 0.0280 0.1270 ;
      RECT 0.0560 0.1730 0.0700 0.2070 ;
      RECT 0.0560 0.1530 0.0700 0.1870 ;
      RECT 0.0560 0.1330 0.0700 0.1670 ;
      RECT 0.2660 0.1930 0.2800 0.2270 ;
      RECT 0.2660 0.1730 0.2800 0.2070 ;
      RECT 0.2660 0.1530 0.2800 0.1870 ;
      RECT 0.2660 0.1330 0.2800 0.1670 ;
      RECT 0.2660 0.1130 0.2800 0.1470 ;
      RECT 0.2660 0.0930 0.2800 0.1270 ;
      RECT 0.2660 0.0730 0.2800 0.1070 ;
      RECT 0.2660 0.0530 0.2800 0.0870 ;
      RECT 0.2660 0.0330 0.2800 0.0670 ;
      RECT 0.2660 0.0130 0.2800 0.0470 ;
      RECT 0.2240 0.1130 0.2380 0.1470 ;
      RECT 0.2240 0.0930 0.2380 0.1270 ;
      RECT 0.2240 0.0730 0.2380 0.1070 ;
      RECT 0.2240 0.0530 0.2380 0.0870 ;
      RECT 0.0980 0.1930 0.1120 0.2270 ;
      RECT 0.0980 0.1730 0.1120 0.2070 ;
      RECT 0.0980 0.0330 0.1120 0.0670 ;
      RECT 0.0980 0.0130 0.1120 0.0470 ;
      RECT 0.1400 0.1530 0.1540 0.1870 ;
      RECT 0.1400 0.1330 0.1540 0.1670 ;
      RECT 0.1400 0.1130 0.1540 0.1470 ;
      RECT 0.1400 0.0930 0.1540 0.1270 ;
      RECT 0.1400 0.0730 0.1540 0.1070 ;
      RECT 0.1400 0.0530 0.1540 0.0870 ;
      RECT 0.3500 0.0130 0.3640 0.1270 ;
      RECT 0.3500 0.1130 0.3640 0.2270 ;
      RECT 0.3080 0.0130 0.3220 0.0470 ;
      RECT 0.3080 0.0330 0.3220 0.0670 ;
      RECT 0.3080 0.0470 0.3220 0.2070 ;
      RECT 0.3080 0.1930 0.3220 0.2270 ;
    LAYER M0 ;
      RECT 0.1630 0.2150 0.1940 0.2250 ;
      RECT 0.1840 0.2150 0.2150 0.2250 ;
      RECT 0.1630 0.0150 0.1940 0.0250 ;
      RECT 0.1840 0.0150 0.2150 0.0250 ;
      RECT 0.1000 0.0950 0.1310 0.1050 ;
      RECT 0.1210 0.0950 0.1520 0.1050 ;
      RECT 0.1420 0.0950 0.1730 0.1050 ;
      RECT 0.0370 0.1950 0.0680 0.2050 ;
      RECT 0.0580 0.1950 0.0890 0.2050 ;
      RECT 0.0790 0.1950 0.1100 0.2050 ;
      RECT 0.1000 0.1950 0.1310 0.2050 ;
      RECT 0.0160 0.1350 0.0470 0.1450 ;
      RECT 0.0370 0.1350 0.0680 0.1450 ;
      RECT 0.2470 0.1150 0.2780 0.1250 ;
      RECT 0.1210 0.0350 0.1520 0.0450 ;
      RECT 0.1420 0.0350 0.1730 0.0450 ;
      RECT 0.1630 0.0350 0.1940 0.0450 ;
      RECT 0.1840 0.0350 0.2150 0.0450 ;
      RECT 0.2050 0.0350 0.2360 0.0450 ;
      RECT 0.2260 0.0350 0.2570 0.0450 ;
      RECT 0.2470 0.0350 0.2780 0.0450 ;
      RECT 0.2260 0.0550 0.2570 0.0650 ;
      RECT 0.1000 0.1750 0.1310 0.1850 ;
      RECT 0.1210 0.1750 0.1520 0.1850 ;
      RECT 0.1000 0.0550 0.1310 0.0650 ;
      RECT 0.1210 0.0550 0.1520 0.0650 ;
      RECT 0.0370 0.0150 0.0680 0.0250 ;
      RECT 0.0580 0.0150 0.0890 0.0250 ;
      RECT 0.0790 0.0150 0.1100 0.0250 ;
      RECT 0.0160 0.2150 0.0260 0.2250 ;
      RECT 0.0160 0.1750 0.0260 0.1850 ;
      RECT 0.0160 0.0550 0.0260 0.0650 ;
      RECT 0.0160 0.0150 0.0260 0.0250 ;
      RECT 0.1840 0.1350 0.1940 0.1450 ;
      RECT 0.1840 0.0950 0.1940 0.1050 ;
      RECT 0.1000 0.1350 0.1100 0.1450 ;
      RECT 0.0160 0.0950 0.0260 0.1050 ;
      RECT 0.2680 0.2150 0.2780 0.2250 ;
      RECT 0.2680 0.1750 0.2780 0.1850 ;
      RECT 0.2680 0.0550 0.2780 0.0650 ;
      RECT 0.2680 0.0150 0.2780 0.0250 ;
      RECT 0.2260 0.1350 0.2360 0.1450 ;
      RECT 0.2260 0.0950 0.2360 0.1050 ;
      RECT 0.1000 0.2150 0.1100 0.2250 ;
      RECT 0.2470 0.1950 0.3200 0.2050 ;
      RECT 0.0580 0.1150 0.0890 0.1250 ;
      RECT 0.1630 0.0550 0.2150 0.0650 ;
      RECT 0.3310 0.2150 0.3620 0.2250 ;
      RECT 0.3300 0.1150 0.4030 0.1250 ;
      RECT 0.3310 0.0150 0.3620 0.0250 ;
      RECT 0.3520 0.0950 0.3620 0.1050 ;
      RECT 0.3520 0.1350 0.3620 0.1450 ;
      RECT 0.3100 0.0150 0.3200 0.0250 ;
      RECT 0.3100 0.0550 0.3200 0.0650 ;
      RECT 0.3100 0.1750 0.3200 0.1850 ;
      RECT 0.3100 0.2150 0.3200 0.2250 ;
      RECT 0.3730 0.0350 0.4030 0.0450 ;
      RECT 0.3730 0.1950 0.4030 0.2050 ;
  END
END SDFF_X1

MACRO SDFF_X2
  CLASS CORE ;
  FOREIGN SDFF_X2 0 0 ;
  ORIGIN 0.0260 0.0150 ;
  SIZE 0.4620 BY 0.2400 ;
  SITE FSFET ;
  SYMMETRY X Y ;
  PIN SI
    DIRECTION INPUT ;
    USE SIGNAL ;
    PORT
      LAYER M1 ;
        RECT 0.4590 0.1880 0.4730 0.2420 ;
    END
  END SI
  PIN SE
    DIRECTION INPUT ;
    USE SIGNAL ;
    PORT
      LAYER M1 ;
        RECT 0.4590 0.1080 0.4730 0.1620 ;
    END
  END SE
  PIN D
    DIRECTION INPUT ;
    USE SIGNAL ;
    PORT
      LAYER M1 ;
        RECT 0.4590 0.0280 0.4730 0.0820 ;
    END
  END D
  PIN QN
    DIRECTION OUTPUT ;
    USE SIGNAL ;
    PORT
      LAYER M1 ;
        RECT 0.0820 0.1880 0.0960 0.2220 ;
        RECT 0.0820 0.2080 0.0960 0.2420 ;
    END
  END QN
  PIN Q
    DIRECTION OUTPUT ;
    USE SIGNAL ;
    PORT
      LAYER M1 ;
        RECT 0.0820 0.0280 0.0960 0.0620 ;
        RECT 0.0820 0.0480 0.0960 0.0820 ;
    END
  END Q
  PIN CK
    DIRECTION INPUT ;
    USE CLOCK ;
    PORT
      LAYER M1 ;
        RECT 0.1240 0.1080 0.1380 0.1420 ;
    END
  END CK
  PIN VSS
    DIRECTION INOUT ;
    USE GROUND ;
    PORT
      LAYER M0 ;
        RECT 0.0100 0.1700 0.5040 0.1800 ;
    END
  END VSS
  PIN VSS
    DIRECTION INOUT ;
    USE GROUND ;
    PORT
      LAYER M0 ;
        RECT 0.0100 0.0100 0.5040 0.0200 ;
    END
  END VSS
  PIN VDD
    DIRECTION INOUT ;
    USE POWER ;
    PORT
      LAYER M0 ;
        RECT 0.0100 0.0900 0.5040 0.1000 ;
    END
  END VDD
  PIN VDD
    DIRECTION INOUT ;
    USE POWER ;
    PORT
      LAYER M0 ;
        RECT 0.0100 0.2500 0.5040 0.2600 ;
    END
  END VDD
  OBS
    LAYER M1 ;
      RECT 0.3340 0.0880 0.3480 0.1220 ;
      RECT 0.3340 0.1080 0.3480 0.1420 ;
      RECT 0.3340 0.1280 0.3480 0.1620 ;
      RECT 0.3340 0.1480 0.3480 0.1820 ;
      RECT 0.3340 0.1680 0.3480 0.2020 ;
      RECT 0.3340 0.1880 0.3480 0.2220 ;
      RECT 0.3340 0.2080 0.3480 0.2420 ;
      RECT 0.1240 0.1480 0.1380 0.1820 ;
      RECT 0.2080 0.0680 0.2220 0.1020 ;
      RECT 0.2080 0.0880 0.2220 0.1220 ;
      RECT 0.2080 0.1080 0.2220 0.1420 ;
      RECT 0.2080 0.1480 0.2220 0.1820 ;
      RECT 0.1660 0.0280 0.1800 0.0620 ;
      RECT 0.2080 0.1680 0.2220 0.2020 ;
      RECT 0.1660 0.0480 0.1800 0.0820 ;
      RECT 0.2080 0.1280 0.2220 0.1620 ;
      RECT 0.3340 0.0680 0.3480 0.1020 ;
      RECT 0.3340 0.0480 0.3480 0.0820 ;
      RECT 0.3340 0.0280 0.3480 0.0620 ;
      RECT 0.2920 0.1280 0.3060 0.1620 ;
      RECT 0.2920 0.1080 0.3060 0.1420 ;
      RECT 0.2920 0.0880 0.3060 0.1220 ;
      RECT 0.2920 0.0680 0.3060 0.1020 ;
      RECT 0.1660 0.2080 0.1800 0.2420 ;
      RECT 0.1660 0.1880 0.1800 0.2220 ;
      RECT 0.1240 0.1680 0.1380 0.2020 ;
      RECT 0.1240 0.1880 0.1380 0.2220 ;
      RECT 0.0820 0.1080 0.0960 0.1420 ;
      RECT 0.0820 0.1280 0.0960 0.1620 ;
      RECT 0.1660 0.1080 0.1800 0.1420 ;
      RECT 0.1660 0.1280 0.1800 0.1620 ;
      RECT 0.2500 0.0280 0.2640 0.0620 ;
      RECT 0.2500 0.0480 0.2640 0.0820 ;
      RECT 0.2500 0.0680 0.2640 0.1020 ;
      RECT 0.2500 0.0880 0.2640 0.1220 ;
      RECT 0.2500 0.1080 0.2640 0.1420 ;
      RECT 0.2500 0.1280 0.2640 0.1620 ;
      RECT 0.2500 0.1480 0.2640 0.1820 ;
      RECT 0.2500 0.1680 0.2640 0.2020 ;
      RECT 0.2500 0.1880 0.2640 0.2220 ;
      RECT 0.2500 0.2080 0.2640 0.2420 ;
      RECT 0.4180 0.0280 0.4320 0.1420 ;
      RECT 0.4180 0.1280 0.4320 0.2420 ;
      RECT 0.3760 0.0280 0.3900 0.0620 ;
      RECT 0.3760 0.0480 0.3900 0.0820 ;
      RECT 0.3760 0.0620 0.3900 0.2220 ;
      RECT 0.3760 0.2080 0.3900 0.2420 ;
    LAYER M0 ;
      RECT 0.2520 0.0300 0.2830 0.0400 ;
      RECT 0.2310 0.0300 0.2620 0.0400 ;
      RECT 0.2520 0.2300 0.2830 0.2400 ;
      RECT 0.2310 0.2300 0.2620 0.2400 ;
      RECT 0.0630 0.2100 0.1360 0.2200 ;
      RECT 0.2100 0.1100 0.2410 0.1200 ;
      RECT 0.1890 0.1100 0.2200 0.1200 ;
      RECT 0.1680 0.1100 0.1990 0.1200 ;
      RECT 0.0840 0.0700 0.0940 0.0800 ;
      RECT 0.0840 0.1900 0.0940 0.2000 ;
      RECT 0.0840 0.2300 0.0940 0.2400 ;
      RECT 0.1470 0.0300 0.1780 0.0400 ;
      RECT 0.1680 0.2300 0.1780 0.2400 ;
      RECT 0.2940 0.1100 0.3040 0.1200 ;
      RECT 0.2940 0.1500 0.3040 0.1600 ;
      RECT 0.3360 0.0300 0.3460 0.0400 ;
      RECT 0.3360 0.0700 0.3460 0.0800 ;
      RECT 0.3360 0.1900 0.3460 0.2000 ;
      RECT 0.3360 0.2300 0.3460 0.2400 ;
      RECT 0.0840 0.1100 0.0940 0.1200 ;
      RECT 0.0840 0.0300 0.0940 0.0400 ;
      RECT 0.2520 0.1500 0.2620 0.1600 ;
      RECT 0.2520 0.1100 0.2620 0.1200 ;
      RECT 0.1680 0.1500 0.1780 0.1600 ;
      RECT 0.1050 0.1500 0.1360 0.1600 ;
      RECT 0.3150 0.1300 0.3460 0.1400 ;
      RECT 0.1890 0.0500 0.2200 0.0600 ;
      RECT 0.2100 0.0500 0.2410 0.0600 ;
      RECT 0.2310 0.0500 0.2620 0.0600 ;
      RECT 0.2520 0.0500 0.2830 0.0600 ;
      RECT 0.2730 0.0500 0.3040 0.0600 ;
      RECT 0.2940 0.0500 0.3250 0.0600 ;
      RECT 0.3150 0.0500 0.3460 0.0600 ;
      RECT 0.2940 0.0700 0.3250 0.0800 ;
      RECT 0.1680 0.1900 0.1990 0.2000 ;
      RECT 0.1890 0.1900 0.2200 0.2000 ;
      RECT 0.1680 0.0700 0.1990 0.0800 ;
      RECT 0.1890 0.0700 0.2200 0.0800 ;
      RECT 0.1050 0.0300 0.1360 0.0400 ;
      RECT 0.1260 0.0300 0.1570 0.0400 ;
      RECT 0.1260 0.2100 0.1570 0.2200 ;
      RECT 0.1470 0.2100 0.1780 0.2200 ;
      RECT 0.1680 0.2100 0.1990 0.2200 ;
      RECT 0.0840 0.1500 0.1150 0.1600 ;
      RECT 0.4410 0.2100 0.4710 0.2200 ;
      RECT 0.4410 0.0500 0.4710 0.0600 ;
      RECT 0.3780 0.2300 0.3880 0.2400 ;
      RECT 0.3780 0.1900 0.3880 0.2000 ;
      RECT 0.3780 0.0700 0.3880 0.0800 ;
      RECT 0.3780 0.0300 0.3880 0.0400 ;
      RECT 0.4200 0.1500 0.4300 0.1600 ;
      RECT 0.4200 0.1100 0.4300 0.1200 ;
      RECT 0.3990 0.0300 0.4300 0.0400 ;
      RECT 0.3980 0.1300 0.4710 0.1400 ;
      RECT 0.3990 0.2300 0.4300 0.2400 ;
      RECT 0.2310 0.0700 0.2830 0.0800 ;
      RECT 0.1260 0.1300 0.1570 0.1400 ;
      RECT 0.3150 0.2100 0.3880 0.2200 ;
      RECT 0.0630 0.0500 0.1150 0.0600 ;
  END
END SDFF_X2

MACRO XNOR2_X1
  CLASS CORE ;
  FOREIGN XNOR2_X1 0 0 ;
  ORIGIN -0.0210 0.0000 ;
  SIZE 0.2940 BY 0.0800 ;
  SITE FSFET ;
  SYMMETRY X Y ;
  PIN B
    DIRECTION INPUT ;
    USE SIGNAL ;
    PORT
      LAYER M1 ;
        RECT 0.1180 0.0530 0.1320 0.0670 ;
    END
  END B
  PIN A
    DIRECTION INPUT ;
    USE SIGNAL ;
    PORT
      LAYER M1 ;
        RECT 0.0770 0.0130 0.0910 0.0270 ;
    END
  END A
  PIN ZN
    DIRECTION OUTPUT ;
    USE SIGNAL ;
    PORT
      LAYER M1 ;
        RECT 0.2450 0.0130 0.2590 0.0470 ;
        RECT 0.2450 0.0330 0.2590 0.0670 ;
    END
  END ZN
  PIN VSS
    DIRECTION INOUT ;
    USE GROUND ;
    PORT
      LAYER M0 ;
        RECT -0.0370 -0.0050 0.2890 0.0050 ;
    END
  END VSS
  PIN VDD
    DIRECTION INOUT ;
    USE POWER ;
    PORT
      LAYER M0 ;
        RECT -0.0370 0.0750 0.2890 0.0850 ;
    END
  END VDD
  OBS
    LAYER M1 ;
      RECT 0.0350 0.0330 0.0490 0.0670 ;
      RECT -0.0070 0.0130 0.0070 0.0470 ;
    LAYER M0 ;
      RECT 0.0990 0.0550 0.1310 0.0650 ;
      RECT 0.2470 0.0150 0.2570 0.0250 ;
      RECT -0.0050 0.0150 0.0050 0.0250 ;
      RECT 0.0370 0.0550 0.0470 0.0650 ;
      RECT 0.1210 0.0550 0.1520 0.0650 ;
      RECT 0.1000 0.0550 0.1310 0.0650 ;
      RECT 0.0790 0.0550 0.1100 0.0650 ;
      RECT 0.0580 0.0550 0.0890 0.0650 ;
      RECT 0.0790 0.0150 0.1100 0.0250 ;
      RECT 0.0580 0.0150 0.0890 0.0250 ;
      RECT 0.0370 0.0150 0.0680 0.0250 ;
      RECT 0.0160 0.0150 0.0470 0.0250 ;
      RECT 0.1840 0.0150 0.2150 0.0250 ;
      RECT 0.1630 0.0150 0.1940 0.0250 ;
      RECT 0.1420 0.0150 0.1730 0.0250 ;
      RECT 0.1210 0.0150 0.1520 0.0250 ;
      RECT 0.2260 0.0550 0.2570 0.0650 ;
      RECT 0.2050 0.0550 0.2360 0.0650 ;
      RECT 0.1840 0.0550 0.2150 0.0650 ;
      RECT 0.1630 0.0550 0.1940 0.0650 ;
      RECT 0.2050 0.0350 0.2360 0.0450 ;
      RECT 0.1840 0.0350 0.2150 0.0450 ;
      RECT 0.1630 0.0350 0.1940 0.0450 ;
      RECT 0.1420 0.0350 0.1730 0.0450 ;
      RECT 0.1210 0.0350 0.1520 0.0450 ;
      RECT 0.1000 0.0350 0.1310 0.0450 ;
      RECT 0.0790 0.0350 0.1100 0.0450 ;
      RECT 0.0580 0.0350 0.0890 0.0450 ;
      RECT 0.0370 0.0350 0.0680 0.0450 ;
      RECT 0.0160 0.0350 0.0470 0.0450 ;
      RECT -0.0050 0.0350 0.0260 0.0450 ;
  END
END XNOR2_X1

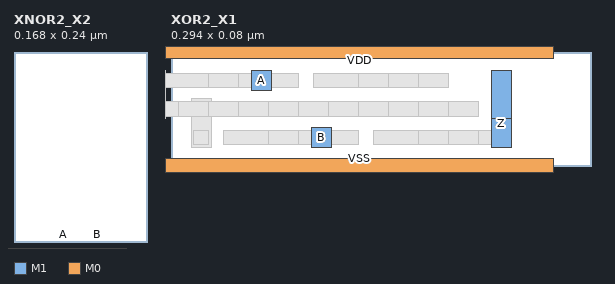
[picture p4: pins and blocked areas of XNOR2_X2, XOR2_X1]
MACRO XNOR2_X2
  CLASS CORE ;
  FOREIGN XNOR2_X2 0 0 ;
  ORIGIN -0.0210 -0.1600 ;
  SIZE 0.1680 BY 0.2400 ;
  SITE FSFET ;
  SYMMETRY X Y ;
  PIN A
    DIRECTION INPUT ;
    USE SIGNAL ;
    PORT
      LAYER M1 ;
        RECT 0.0770 0.0530 0.0910 0.0670 ;
    END
  END A
  PIN B
    DIRECTION INPUT ;
    USE SIGNAL ;
    PORT
      LAYER M1 ;
        RECT 0.1190 0.0530 0.1330 0.0670 ;
    END
  END B
  PIN ZN
    DIRECTION OUTPUT ;
    USE SIGNAL ;
    PORT
      LAYER M1 ;
        RECT 0.0770 -0.0670 0.0910 -0.0330 ;
        RECT 0.0770 -0.0470 0.0910 -0.0130 ;
    END
  END ZN
  PIN VDD
    DIRECTION INOUT ;
    USE POWER ;
    PORT
      LAYER M0 ;
        RECT -0.0370 -0.1650 0.1630 -0.1550 ;
    END
  END VDD
  PIN VSS
    DIRECTION INOUT ;
    USE GROUND ;
    PORT
      LAYER M0 ;
        RECT -0.0370 0.0750 0.1630 0.0850 ;
    END
  END VSS
  PIN VDD
    DIRECTION INOUT ;
    USE POWER ;
    PORT
      LAYER M0 ;
        RECT -0.0370 -0.0050 0.1630 0.0050 ;
    END
  END VDD
  PIN VSS
    DIRECTION INOUT ;
    USE GROUND ;
    PORT
      LAYER M0 ;
        RECT -0.0370 -0.0850 0.1630 -0.0750 ;
    END
  END VSS
  OBS
    LAYER M1 ;
      RECT 0.0770 -0.1470 0.0910 -0.1130 ;
      RECT 0.0770 -0.1270 0.0910 -0.0930 ;
      RECT 0.0770 -0.1070 0.0910 -0.0730 ;
      RECT 0.0770 -0.0870 0.0910 -0.0530 ;
      RECT 0.1190 -0.1270 0.1330 -0.0930 ;
      RECT 0.1190 -0.1070 0.1330 -0.0730 ;
      RECT 0.1190 -0.0870 0.1330 -0.0530 ;
      RECT 0.0350 -0.1270 0.0490 -0.0930 ;
      RECT 0.0350 -0.1070 0.0490 -0.0730 ;
      RECT 0.0350 -0.0870 0.0490 -0.0530 ;
      RECT 0.0350 -0.0470 0.0490 -0.0130 ;
      RECT 0.0350 -0.0270 0.0490 0.0070 ;
      RECT 0.0350 -0.0070 0.0490 0.0270 ;
      RECT 0.0350 0.0130 0.0490 0.0470 ;
      RECT 0.0350 0.0330 0.0490 0.0670 ;
    LAYER M0 ;
      RECT 0.0580 0.0550 0.0890 0.0650 ;
      RECT 0.0790 -0.1050 0.0890 -0.0950 ;
      RECT 0.0790 -0.0650 0.0890 -0.0550 ;
      RECT 0.1210 -0.1050 0.1310 -0.0950 ;
      RECT 0.0370 -0.1050 0.0470 -0.0950 ;
      RECT 0.1210 -0.0650 0.1310 -0.0550 ;
      RECT 0.0370 -0.0650 0.0470 -0.0550 ;
      RECT 0.0370 0.0550 0.0470 0.0650 ;
      RECT 0.0580 -0.1450 0.0890 -0.1350 ;
      RECT 0.0370 -0.1450 0.0680 -0.1350 ;
      RECT 0.0580 -0.0250 0.0890 -0.0150 ;
      RECT 0.0370 -0.0250 0.0680 -0.0150 ;
      RECT 0.1000 -0.1250 0.1310 -0.1150 ;
      RECT 0.0790 -0.1250 0.1100 -0.1150 ;
      RECT 0.0580 -0.1250 0.0890 -0.1150 ;
      RECT 0.0370 -0.1250 0.0680 -0.1150 ;
      RECT 0.0160 -0.0450 0.0470 -0.0350 ;
      RECT 0.0580 0.0150 0.0890 0.0250 ;
      RECT 0.0370 0.0150 0.0680 0.0250 ;
      RECT 0.1000 0.0550 0.1310 0.0650 ;
  END
END XNOR2_X2

MACRO XOR2_X1
  CLASS CORE ;
  FOREIGN XOR2_X1 0 0 ;
  ORIGIN -0.0210 0.0000 ;
  SIZE 0.2940 BY 0.0800 ;
  SITE FSFET ;
  SYMMETRY X Y ;
  PIN B
    DIRECTION INPUT ;
    USE SIGNAL ;
    PORT
      LAYER M1 ;
        RECT 0.1190 0.0130 0.1330 0.0270 ;
    END
  END B
  PIN A
    DIRECTION INPUT ;
    USE SIGNAL ;
    PORT
      LAYER M1 ;
        RECT 0.0770 0.0530 0.0910 0.0670 ;
    END
  END A
  PIN Z
    DIRECTION OUTPUT ;
    USE SIGNAL ;
    PORT
      LAYER M1 ;
        RECT 0.2450 0.0130 0.2590 0.0470 ;
        RECT 0.2450 0.0330 0.2590 0.0670 ;
    END
  END Z
  PIN VSS
    DIRECTION INOUT ;
    USE GROUND ;
    PORT
      LAYER M0 ;
        RECT -0.0370 -0.0050 0.2890 0.0050 ;
    END
  END VSS
  PIN VDD
    DIRECTION INOUT ;
    USE POWER ;
    PORT
      LAYER M0 ;
        RECT -0.0370 0.0750 0.2890 0.0850 ;
    END
  END VDD
  OBS
    LAYER M1 ;
      RECT 0.0350 0.0130 0.0490 0.0470 ;
      RECT -0.0070 0.0330 0.0070 0.0670 ;
    LAYER M0 ;
      RECT 0.1000 0.0150 0.1310 0.0250 ;
      RECT 0.0580 0.0550 0.0890 0.0650 ;
      RECT 0.2470 0.0550 0.2570 0.0650 ;
      RECT 0.0370 0.0150 0.0470 0.0250 ;
      RECT -0.0050 0.0550 0.0050 0.0650 ;
      RECT 0.1210 0.0150 0.1520 0.0250 ;
      RECT 0.1000 0.0150 0.1310 0.0250 ;
      RECT 0.0790 0.0150 0.1100 0.0250 ;
      RECT 0.0580 0.0150 0.0890 0.0250 ;
      RECT 0.0790 0.0550 0.1100 0.0650 ;
      RECT 0.0580 0.0550 0.0890 0.0650 ;
      RECT 0.0370 0.0550 0.0680 0.0650 ;
      RECT 0.0160 0.0550 0.0470 0.0650 ;
      RECT 0.2260 0.0150 0.2570 0.0250 ;
      RECT 0.2050 0.0150 0.2360 0.0250 ;
      RECT 0.1840 0.0150 0.2150 0.0250 ;
      RECT 0.1630 0.0150 0.1940 0.0250 ;
      RECT 0.1840 0.0550 0.2150 0.0650 ;
      RECT 0.1630 0.0550 0.1940 0.0650 ;
      RECT 0.1420 0.0550 0.1730 0.0650 ;
      RECT 0.1210 0.0550 0.1520 0.0650 ;
      RECT 0.2050 0.0350 0.2360 0.0450 ;
      RECT 0.1840 0.0350 0.2150 0.0450 ;
      RECT 0.1630 0.0350 0.1940 0.0450 ;
      RECT 0.1420 0.0350 0.1730 0.0450 ;
      RECT 0.1210 0.0350 0.1520 0.0450 ;
      RECT 0.1000 0.0350 0.1310 0.0450 ;
      RECT 0.0790 0.0350 0.1100 0.0450 ;
      RECT 0.0580 0.0350 0.0890 0.0450 ;
      RECT 0.0370 0.0350 0.0680 0.0450 ;
      RECT 0.0160 0.0350 0.0470 0.0450 ;
      RECT -0.0050 0.0350 0.0260 0.0450 ;
  END
END XOR2_X1

END LIBRARY
